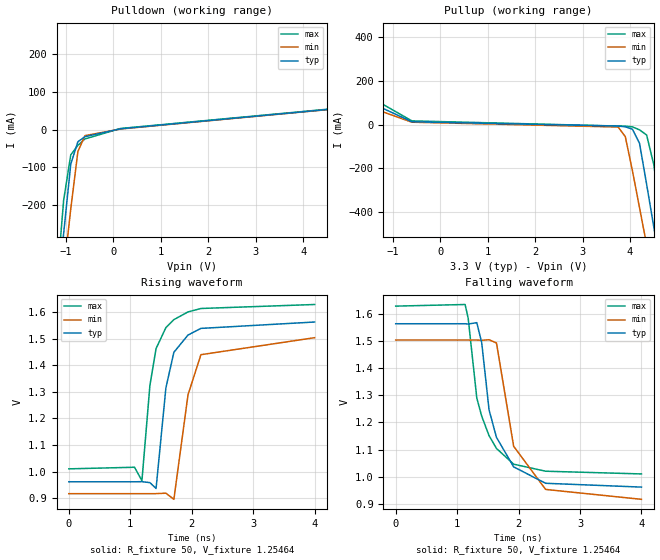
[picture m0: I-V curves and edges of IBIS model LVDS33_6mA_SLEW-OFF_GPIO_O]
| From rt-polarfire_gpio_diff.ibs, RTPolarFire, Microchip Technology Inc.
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|   Model LVDS33_6mA_SLEW-OFF_GPIO_O
[Model]   LVDS33_6mA_SLEW-OFF_GPIO_O
Model_type   Output
Polarity   Non-Inverting
Enable   Active-High
Vmeas =   1.2
Cref =   5p
Rref =   100
|   typ   min   max
C_comp_pullup   2.605e-12   2.605e-12   2.76e-12
C_comp_pulldown  2.605e-12   2.605e-12   2.76e-12
[Temperature Range]  25C   125C   -55C
[Voltage Range]  3.3   3.15   3.45
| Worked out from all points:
|   slope of the pulldown table from 0 to 0.495 V, typ, clamps not added: 91 ohm
|   slope of the pullup table from 0 to 0.495 V, typ, clamps not added: 102 ohm
|   rising waveform, R_fixture 50, V_fixture 1.25464: 20-80 % time 217ps typ, 238ps min, 232ps max; typ from 0.961 V to 1.56 V
|   falling waveform, R_fixture 50, V_fixture 1.25464: 20-80 % time 343ps typ, 341ps min, 346ps max; typ from 1.56 V to 0.961 V
[Pulldown]
|Voltage   I(typ)   I(min)   I(max)
-3.3V     -3.224A    -2.962A    -3.689A
-1.2V     -469.5mA   -550.8mA   -416.8mA
-1.05V    -275.6mA   -380.6mA   -187.3mA
-900mV    -91.45mA   -210.5mA   -66.79mA
-750mV    -31.79mA   -58.02mA   -41.54mA
-600mV    -18.41mA   -15.65mA   -24.42mA
150mV     2.545mA    1.949mA    3.354mA
4.5V      53.6mA     53.25mA    54.33mA
5.1V      120.5mA    109.3mA    127.7mA
6V        250.4mA    221.3mA    278.1mA
6.15V     274.9mA    242.6mA    305.6mA
6.6V      354.3mA    309.4mA    392.8mA
[Pullup]
|Voltage   I(typ)   I(min)   I(max)
-3.3V     376.5mA    307.5mA    447.5mA
-1.8V     133.6mA    104.2mA    166.2mA
-600mV    13.4mA     11.28mA    17.4mA
3.75V     -6.487mA   -10.85mA   -6.355mA
3.9V      -9.671mA   -54.64mA   -6.543mA
4.05V     -20.47mA   -210mA     -10.08mA
4.2V      -85.38mA   -379.9mA   -23.71mA
4.35V     -273.1mA   -549.9mA   -47.38mA
4.5V      -466.9mA   -719.7mA   -182.5mA
4.65V     -660.8mA   -889.7mA   -412mA
4.8V      -855mA     -1.06A     -641.6mA
6.6V      -3.219A    -3.132A    -3.444A
[Ramp]
| variable   typ   min   max
dV/dt_r 0.3794/0.2186e-9   0.3655/0.2404e-9   0.3986/0.2268e-9
dV/dt_f 0.3644/0.3414e-9   0.3549/0.3403e-9   0.3759/0.3446e-9
R_load = 50
[Rising waveform]
R_fixture= 50
V_fixture= 1.25464
V_fixture_min= 1.19616
V_fixture_max= 1.31676
|Time   V(typ)   V(min)   V(max)
0s        961.2mV    916.6mV    1.01V
1.07ns    961.2mV    916.6mV    1.016V
1.19ns    961.8mV    916.6mV    965.2mV
1.32ns    958.1mV    916.5mV    1.325V
1.42ns    936.1mV    916.7mV    1.463V
1.58ns    1.315V     918.3mV    1.542V
1.71ns    1.449V     895.2mV    1.572V
1.94ns    1.514V     1.289V     1.601V
2.15ns    1.539V     1.44V      1.614V
4ns       1.563V     1.504V     1.629V
[Falling waveform]
R_fixture= 50
V_fixture= 1.25464
V_fixture_min= 1.19616
V_fixture_max= 1.31676
|Time   V(typ)   V(min)   V(max)
0s        1.564V     1.504V     1.629V
1.13ns    1.564V     1.504V     1.635V
1.18ns    1.563V     1.504V     1.584V
1.32ns    1.568V     1.504V     1.29V
1.4ns     1.494V     1.503V     1.223V
1.52ns    1.246V     1.505V     1.151V
1.64ns    1.145V     1.493V     1.104V
1.92ns    1.036V     1.112V     1.046V
2.44ns    975.5mV    952.8mV    1.02V
4ns       961.4mV    916.3mV    1.01V
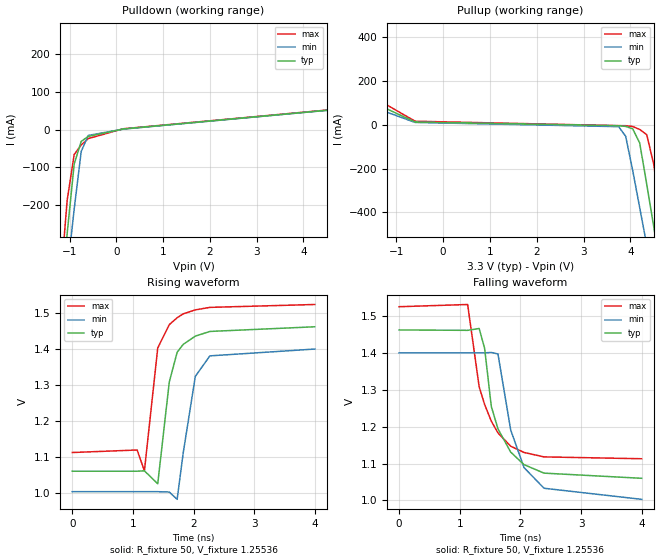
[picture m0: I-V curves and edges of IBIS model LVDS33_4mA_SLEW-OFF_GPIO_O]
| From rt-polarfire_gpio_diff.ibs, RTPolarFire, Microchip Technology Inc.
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|   Model LVDS33_4mA_SLEW-OFF_GPIO_O
[Model]   LVDS33_4mA_SLEW-OFF_GPIO_O
Model_type   Output
Polarity   Non-Inverting
Enable   Active-High
Vmeas =   1.2
Cref =   5p
Rref =   100
|   typ   min   max
C_comp_pullup   2.605e-12   2.605e-12   2.76e-12
C_comp_pulldown  2.605e-12   2.605e-12   2.76e-12
[Temperature Range]  25C   125C   -55C
[Voltage Range]  3.3   3.15   3.45
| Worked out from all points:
|   slope of the pulldown table from 0 to 0.495 V, typ, clamps not added: 137 ohm
|   slope of the pullup table from 0 to 0.495 V, typ, clamps not added: 138 ohm
|   rising waveform, R_fixture 50, V_fixture 1.25536: 20-80 % time 214ps typ, 213ps min, 229ps max; typ from 1.06 V to 1.46 V
|   falling waveform, R_fixture 50, V_fixture 1.25536: 20-80 % time 367ps typ, 352ps min, 364ps max; typ from 1.46 V to 1.06 V
[Pulldown]
|Voltage   I(typ)   I(min)   I(max)
-3.3V     -3.224A    -2.962A    -3.688A
-1.2V     -469.2mA   -550.5mA   -416.4mA
-1.05V    -275.2mA   -380.3mA   -186.9mA
-900mV    -90.84mA   -210.2mA   -65.68mA
-750mV    -30.98mA   -57.57mA   -40.48mA
-600mV    -17.67mA   -15.12mA   -23.45mA
150mV     2.057mA    1.632mA    2.625mA
4.5V      51.56mA    51.45mA    52.21mA
5.1V      118.4mA    107.5mA    125.6mA
6V        248.2mA    219.3mA    275.8mA
6.15V     272.7mA    240.6mA    303.2mA
6.6V      351.9mA    307.2mA    390.3mA
[Pullup]
|Voltage   I(typ)   I(min)   I(max)
-3.3V     375.9mA    307.3mA    445.8mA
-1.8V     131.5mA    103.2mA    163.5mA
-600mV    12.28mA    10.41mA    15.98mA
3.75V     -4.424mA   -8.823mA   -4.266mA
3.9V      -7.63mA    -52.76mA   -4.457mA
4.05V     -18.46mA   -208.2mA   -8.018mA
4.2V      -83.59mA   -378.1mA   -21.68mA
4.35V     -271.4mA   -548.1mA   -45.37mA
4.5V      -465.1mA   -717.9mA   -180.8mA
4.65V     -659.1mA   -887.9mA   -410.3mA
4.8V      -853.2mA   -1.058A    -639.9mA
6.6V      -3.217A    -3.13A     -3.442A
[Ramp]
| variable   typ   min   max
dV/dt_r 0.2623/0.2137e-9   0.2538/0.2185e-9   0.2782/0.2158e-9
dV/dt_f 0.2437/0.3650e-9   0.2408/0.3504e-9   0.2521/0.3622e-9
R_load = 50
[Rising waveform]
R_fixture= 50
V_fixture= 1.25536
V_fixture_min= 1.19490
V_fixture_max= 1.31638
|Time   V(typ)   V(min)   V(max)
0s        1.06V      1.003V     1.112V
1.07ns    1.06V      1.003V     1.119V
1.19ns    1.061V     1.003V     1.061V
1.41ns    1.025V     1.003V     1.403V
1.6ns     1.308V     1.002V     1.468V
1.73ns    1.391V     981.7mV    1.487V
1.83ns    1.413V     1.111V     1.498V
2.03ns    1.436V     1.324V     1.509V
2.27ns    1.449V     1.381V     1.516V
4ns       1.462V     1.4V       1.524V
[Falling waveform]
R_fixture= 50
V_fixture= 1.25536
V_fixture_min= 1.19490
V_fixture_max= 1.31638
|Time   V(typ)   V(min)   V(max)
0s        1.462V     1.4V       1.525V
1.13ns    1.461V     1.4V       1.531V
1.32ns    1.466V     1.4V       1.308V
1.41ns    1.412V     1.4V       1.26V
1.52ns    1.255V     1.401V     1.215V
1.63ns    1.194V     1.397V     1.183V
1.84ns    1.131V     1.191V     1.147V
2.06ns    1.097V     1.089V     1.13V
2.39ns    1.074V     1.033V     1.118V
4ns       1.06V      1.003V     1.113V
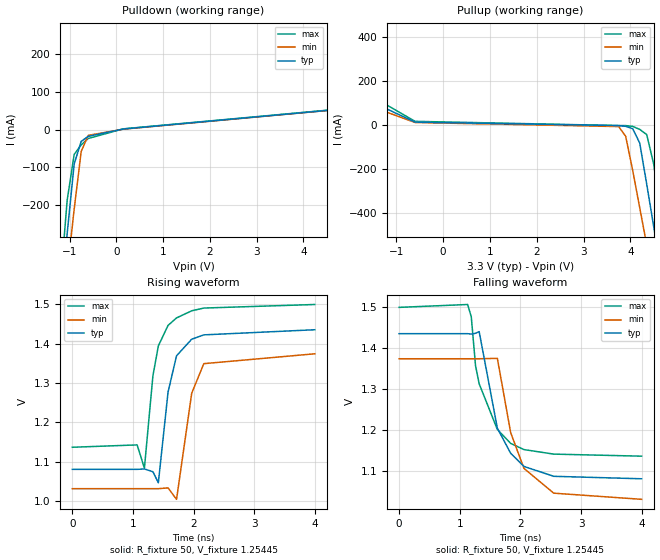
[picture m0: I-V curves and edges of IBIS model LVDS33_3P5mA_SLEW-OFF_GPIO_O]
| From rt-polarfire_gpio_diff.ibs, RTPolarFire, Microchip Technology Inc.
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|   Model LVDS33_3P5mA_SLEW-OFF_GPIO_O
[Model]   LVDS33_3P5mA_SLEW-OFF_GPIO_O
Model_type   Output
Polarity   Non-Inverting
Enable   Active-High
Vmeas =   1.2
Cref =   5p
Rref =   100
|   typ   min   max
C_comp_pullup   2.605e-12   2.605e-12   2.76e-12
C_comp_pulldown  2.605e-12   2.605e-12   2.76e-12
[Temperature Range]  25C   125C   -55C
[Voltage Range]  3.3   3.15   3.45
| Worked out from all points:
|   slope of the pulldown table from 0 to 0.495 V, typ, clamps not added: 154 ohm
|   slope of the pullup table from 0 to 0.495 V, typ, clamps not added: 154 ohm
|   rising waveform, R_fixture 50, V_fixture 1.25445: 20-80 % time 210ps typ, 211ps min, 227ps max; typ from 1.08 V to 1.44 V
|   falling waveform, R_fixture 50, V_fixture 1.25445: 20-80 % time 366ps typ, 358ps min, 375ps max; typ from 1.44 V to 1.08 V
[Pulldown]
|Voltage   I(typ)   I(min)   I(max)
-3.3V     -3.224A    -2.962A    -3.688A
-1.2V     -469.1mA   -550.4mA   -416.3mA
-1.05V    -275.1mA   -380.2mA   -186.7mA
-900mV    -90.69mA   -210.1mA   -65.38mA
-750mV    -30.77mA   -57.4mA    -40.19mA
-600mV    -17.48mA   -14.92mA   -23.17mA
150mV     1.916mA    1.491mA    2.401mA
4.5V      51.12mA    50.84mA    51.7mA
5.1V      118mA      106.9mA    125.1mA
6V        247.7mA    218.7mA    275.2mA
6.15V     272.2mA    239.9mA    302.6mA
6.6V      351.3mA    306.5mA    389.6mA
[Pullup]
|Voltage   I(typ)   I(min)   I(max)
-3.3V     375.8mA    307.2mA    445.5mA
-1.8V     130.9mA    103mA      162.8mA
-600mV    11.9mA     10.12mA    15.49mA
3.75V     -3.915mA   -8.323mA   -3.752mA
3.9V      -7.126mA   -52.3mA    -3.944mA
4.05V     -17.97mA   -207.8mA   -7.511mA
4.2V      -83.15mA   -377.7mA   -21.18mA
4.35V     -271mA     -547.6mA   -44.88mA
4.5V      -464.7mA   -717.5mA   -180.4mA
4.65V     -658.6mA   -887.5mA   -409.9mA
4.8V      -852.8mA   -1.058A    -639.5mA
6.6V      -3.216A    -3.13A     -3.442A
[Ramp]
| variable   typ   min   max
dV/dt_r 0.2351/0.2070e-9   0.2218/0.2171e-9   0.2493/0.2113e-9
dV/dt_f 0.2152/0.3633e-9   0.2079/0.3570e-9   0.2220/0.3715e-9
R_load = 50
[Rising waveform]
R_fixture= 50
V_fixture= 1.25445
V_fixture_min= 1.19435
V_fixture_max= 1.31632
|Time   V(typ)   V(min)   V(max)
0s        1.081V     1.032V     1.137V
1.07ns    1.081V     1.032V     1.143V
1.19ns    1.082V     1.032V     1.084V
1.33ns    1.075V     1.032V     1.318V
1.42ns    1.047V     1.032V     1.394V
1.58ns    1.277V     1.034V     1.446V
1.72ns    1.369V     1.005V     1.465V
1.97ns    1.411V     1.274V     1.483V
2.17ns    1.422V     1.349V     1.49V
4ns       1.435V     1.374V     1.499V
[Falling waveform]
R_fixture= 50
V_fixture= 1.25445
V_fixture_min= 1.19435
V_fixture_max= 1.31632
|Time   V(typ)   V(min)   V(max)
0s        1.435V     1.374V     1.499V
1.13ns    1.435V     1.374V     1.506V
1.19ns    1.434V     1.374V     1.476V
1.26ns    1.436V     1.374V     1.357V
1.32ns    1.44V      1.374V     1.313V
1.62ns    1.205V     1.375V     1.202V
1.84ns    1.144V     1.194V     1.168V
2.06ns    1.112V     1.107V     1.153V
2.55ns    1.088V     1.047V     1.142V
4ns       1.082V     1.032V     1.137V
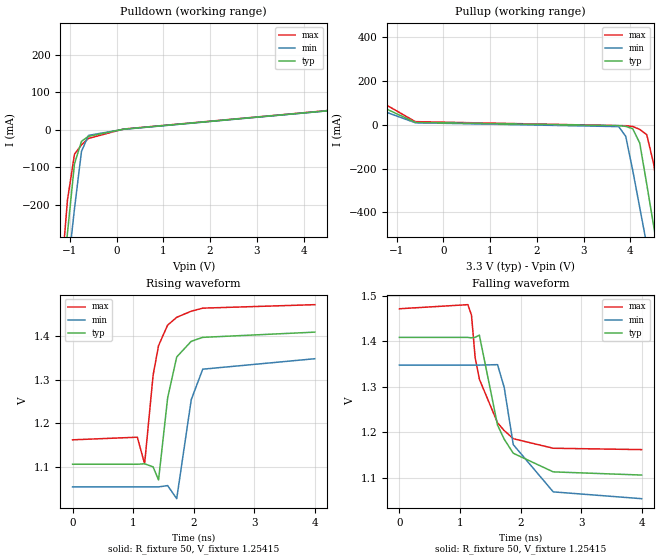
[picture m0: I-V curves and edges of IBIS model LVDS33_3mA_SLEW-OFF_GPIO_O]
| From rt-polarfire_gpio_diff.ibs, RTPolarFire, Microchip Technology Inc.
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|   Model LVDS33_3mA_SLEW-OFF_GPIO_O
[Model]   LVDS33_3mA_SLEW-OFF_GPIO_O
Model_type   Output
Polarity   Non-Inverting
Enable   Active-High
Vmeas =   1.2
Cref =   5p
Rref =   100
|   typ   min   max
C_comp_pullup   2.605e-12   2.605e-12   2.76e-12
C_comp_pulldown  2.605e-12   2.605e-12   2.76e-12
[Temperature Range]  25C   125C   -55C
[Voltage Range]  3.3   3.15   3.45
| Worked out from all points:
|   slope of the pulldown table from 0 to 0.495 V, typ, clamps not added: 181 ohm
|   slope of the pullup table from 0 to 0.495 V, typ, clamps not added: 176 ohm
|   rising waveform, R_fixture 50, V_fixture 1.25415: 20-80 % time 203ps typ, 206ps min, 227ps max; typ from 1.11 V to 1.41 V
|   falling waveform, R_fixture 50, V_fixture 1.25415: 20-80 % time 376ps typ, 366ps min, 386ps max; typ from 1.41 V to 1.11 V
[Pulldown]
|Voltage   I(typ)   I(min)   I(max)
-3.3V     -3.224A    -2.962A    -3.688A
-1.2V     -469mA     -550.4mA   -416.2mA
-1.05V    -275mA     -380.1mA   -186.6mA
-900mV    -90.51mA   -210mA     -65.03mA
-750mV    -30.52mA   -57.26mA   -39.85mA
-600mV    -17.24mA   -14.75mA   -22.86mA
150mV     1.734mA    1.364mA    2.137mA
4.5V      50.6mA     50.37mA    51.17mA
5.1V      117.5mA    106.4mA    124.6mA
6V        247.1mA    218.1mA    274.7mA
6.15V     271.6mA    239.3mA    302mA
6.6V      350.7mA    305.9mA    389mA
[Pullup]
|Voltage   I(typ)   I(min)   I(max)
-3.3V     375.6mA    307.1mA    445.3mA
-1.8V     130.3mA    102.8mA    162.1mA
-600mV    11.44mA    9.762mA    14.9mA
3.75V     -3.395mA   -7.812mA   -3.224mA
3.9V      -6.611mA   -51.82mA   -3.417mA
4.05V     -17.46mA   -207.3mA   -6.99mA
4.2V      -82.7mA    -377.2mA   -20.67mA
4.35V     -270.5mA   -547.2mA   -44.38mA
4.5V      -464.3mA   -717mA     -179.9mA
4.65V     -658.2mA   -887.1mA   -409.4mA
4.8V      -852.4mA   -1.057A    -639mA
6.6V      -3.216A    -3.129A    -3.441A
[Ramp]
| variable   typ   min   max
dV/dt_r 0.2049/0.2069e-9   0.1931/0.2142e-9   0.2187/0.2087e-9
dV/dt_f 0.1847/0.3732e-9   0.1787/0.3651e-9   0.1918/0.3808e-9
R_load = 50
[Rising waveform]
R_fixture= 50
V_fixture= 1.25415
V_fixture_min= 1.19418
V_fixture_max= 1.31585
|Time   V(typ)   V(min)   V(max)
0s        1.106V     1.054V     1.162V
1.07ns    1.106V     1.054V     1.168V
1.19ns    1.107V     1.054V     1.107V
1.33ns    1.1V       1.054V     1.31V
1.42ns    1.07V      1.054V     1.378V
1.57ns    1.258V     1.057V     1.425V
1.72ns    1.352V     1.027V     1.443V
1.96ns    1.388V     1.254V     1.457V
2.15ns    1.397V     1.324V     1.464V
4ns       1.409V     1.348V     1.472V
[Falling waveform]
R_fixture= 50
V_fixture= 1.25415
V_fixture_min= 1.19418
V_fixture_max= 1.31585
|Time   V(typ)   V(min)   V(max)
0s        1.409V     1.348V     1.472V
1.13ns    1.409V     1.348V     1.481V
1.19ns    1.408V     1.348V     1.458V
1.25ns    1.409V     1.348V     1.365V
1.32ns    1.414V     1.348V     1.317V
1.62ns    1.216V     1.349V     1.221V
1.73ns    1.185V     1.299V     1.204V
1.88ns    1.154V     1.173V     1.186V
2.54ns    1.113V     1.069V     1.165V
4ns       1.106V     1.054V     1.162V
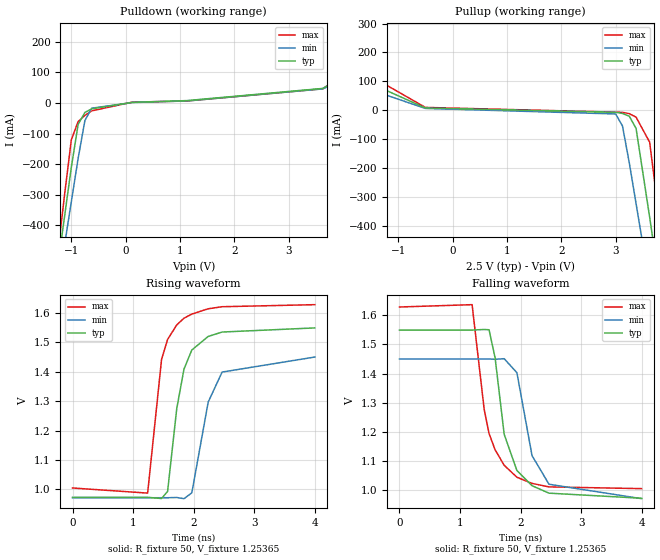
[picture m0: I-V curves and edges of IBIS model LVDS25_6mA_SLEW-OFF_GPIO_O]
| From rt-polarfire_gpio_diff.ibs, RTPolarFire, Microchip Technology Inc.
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|   Model LVDS25_6mA_SLEW-OFF_GPIO_O
[Model]   LVDS25_6mA_SLEW-OFF_GPIO_O
Model_type   Output
Polarity   Non-Inverting
Enable   Active-High
Vmeas =   1.2
Cref =   5p
Rref =   100
|   typ   min   max
C_comp_pullup   2.605e-12   2.605e-12   2.76e-12
C_comp_pulldown  2.605e-12   2.605e-12   2.76e-12
[Temperature Range]  25C   125C   -55C
[Voltage Range]  2.5   2.375   2.625
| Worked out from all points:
|   slope of the pulldown table from 0 to 0.375 V, typ, clamps not added: 79.1 ohm
|   slope of the pullup table from 0 to 0.375 V, typ, clamps not added: 103 ohm
|   rising waveform, R_fixture 50, V_fixture 1.25365: 20-80 % time 246ps typ, 296ps min, 239ps max; typ from 0.973 V to 1.55 V
|   falling waveform, R_fixture 50, V_fixture 1.25365: 20-80 % time 293ps typ, 294ps min, 302ps max; typ from 1.55 V to 0.973 V
[Pulldown]
|Voltage   I(typ)   I(min)   I(max)
-2.5V     -2.164A    -2.035A    -2.425A
-1.25V    -533.8mA   -607mA     -493mA
-1.125V   -372.1mA   -465.2mA   -301.5mA
-1V       -210.6mA   -323.3mA   -120.6mA
-875mV    -70.3mA    -181.7mA   -60.99mA
-750mV    -30.89mA   -57.23mA   -40.67mA
-625mV    -19.32mA   -17.05mA   -25.85mA
125mV     2.003mA    1.397mA    2.795mA
1.125V    7.725mA    6.579mA    6.369mA
3.625V    47.6mA     46.02mA    46.43mA
4.25V     111.7mA    97.85mA    122.6mA
5V        215.8mA    185.5mA    244.4mA
[Pullup]
|Voltage   I(typ)   I(min)   I(max)
-2.5V     231mA      182.9mA    284.8mA
-1.5V     92.37mA    70.56mA    117.7mA
-500mV    8.223mA    6.452mA    10.05mA
3V        -6.914mA   -12.63mA   -6.367mA
3.125V    -10.83mA   -54.39mA   -6.994mA
3.25V     -20.45mA   -181.5mA   -11.53mA
3.375V    -62.83mA   -323mA     -23.69mA
3.625V    -370mA     -606.3mA   -110.5mA
3.75V     -531.5mA   -747.8mA   -297.3mA
3.875V    -693.1mA   -889.5mA   -488.6mA
4V        -855mA     -1.031A    -679.9mA
5V        -2.159A    -2.177A    -2.222A
[Ramp]
| variable   typ   min   max
dV/dt_r 0.3510/0.2469e-9   0.2898/0.2956e-9   0.3843/0.2379e-9
dV/dt_f 0.3489/0.2929e-9   0.2898/0.2949e-9   0.3790/0.3006e-9
R_load = 50
[Rising waveform]
R_fixture= 50
V_fixture= 1.25365
V_fixture_min= 1.19649
V_fixture_max= 1.31735
|Time   V(typ)   V(min)   V(max)
0s        973.3mV    971.9mV    1.005V
1.24ns    973.3mV    971.9mV    987.7mV
1.47ns    969.3mV    971.9mV    1.442V
1.57ns    993.7mV    971.9mV    1.51V
1.72ns    1.274V     972.8mV    1.559V
1.84ns    1.409V     968.7mV    1.582V
1.97ns    1.474V     988.8mV    1.596V
2.24ns    1.52V      1.297V     1.614V
2.47ns    1.535V     1.399V     1.621V
4ns       1.549V     1.45V      1.628V
[Falling waveform]
R_fixture= 50
V_fixture= 1.25365
V_fixture_min= 1.19649
V_fixture_max= 1.31735
|Time   V(typ)   V(min)   V(max)
0s        1.549V     1.45V      1.628V
1.2ns     1.549V     1.45V      1.636V
1.4ns     1.551V     1.45V      1.277V
1.48ns    1.55V      1.45V      1.195V
1.58ns    1.454V     1.449V     1.139V
1.73ns    1.192V     1.451V     1.086V
1.94ns    1.068V     1.403V     1.045V
2.19ns    1.016V     1.119V     1.024V
2.47ns    990.5mV    1.021V     1.012V
4ns       973.1mV    971.6mV    1.006V
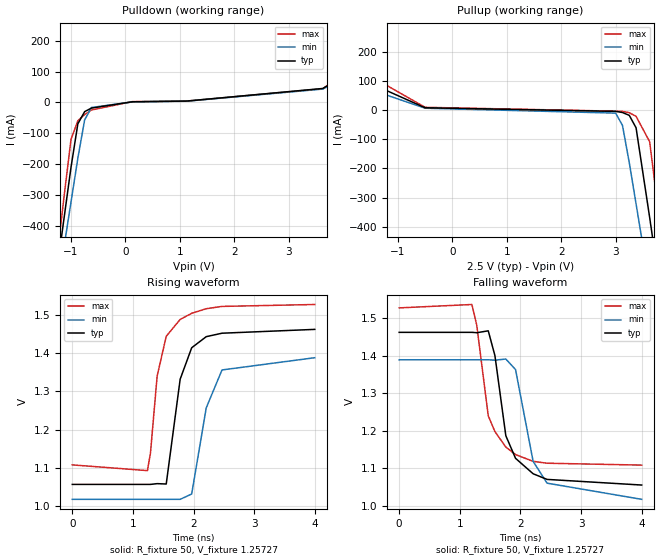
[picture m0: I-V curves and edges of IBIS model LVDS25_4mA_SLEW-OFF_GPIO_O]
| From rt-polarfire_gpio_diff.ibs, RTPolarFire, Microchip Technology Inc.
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|   Model LVDS25_4mA_SLEW-OFF_GPIO_O
[Model]   LVDS25_4mA_SLEW-OFF_GPIO_O
Model_type   Output
Polarity   Non-Inverting
Enable   Active-High
Vmeas =   1.2
Cref =   5p
Rref =   100
|   typ   min   max
C_comp_pullup   2.605e-12   2.605e-12   2.76e-12
C_comp_pulldown  2.605e-12   2.605e-12   2.76e-12
[Temperature Range]  25C   125C   -55C
[Voltage Range]  2.5   2.375   2.625
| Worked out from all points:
|   slope of the pulldown table from 0 to 0.375 V, typ, clamps not added: 105 ohm
|   slope of the pullup table from 0 to 0.375 V, typ, clamps not added: 129 ohm
|   rising waveform, R_fixture 50, V_fixture 1.25727: 20-80 % time 229ps typ, 269ps min, 230ps max; typ from 1.06 V to 1.46 V
|   falling waveform, R_fixture 50, V_fixture 1.25727: 20-80 % time 285ps typ, 299ps min, 295ps max; typ from 1.46 V to 1.06 V
[Pulldown]
|Voltage   I(typ)   I(min)   I(max)
-2.5V     -2.163A    -2.035A    -2.424A
-1.25V    -533.5mA   -606.9mA   -492.7mA
-1.125V   -371.8mA   -465.1mA   -301.1mA
-1V       -210.3mA   -323.2mA   -119.8mA
-875mV    -69.77mA   -181.5mA   -59.99mA
-750mV    -30.27mA   -56.99mA   -39.71mA
-625mV    -18.74mA   -16.77mA   -24.95mA
125mV     1.712mA    1.256mA    2.274mA
1.125V    4.045mA    3.602mA    4.215mA
3.625V    44.96mA    43.06mA    44.34mA
4.25V     110mA      96.86mA    120.4mA
5V        214mA      184.5mA    242.1mA
[Pullup]
|Voltage   I(typ)   I(min)   I(max)
-2.5V     229.4mA    182.5mA    282.3mA
-1.5V     90.6mA     69.32mA    115.4mA
-500mV    7.398mA    5.901mA    8.984mA
3V        -4.874mA   -10.84mA   -4.281mA
3.125V    -8.808mA   -52.72mA   -4.916mA
3.25V     -18.45mA   -179.9mA   -9.476mA
3.375V    -60.99mA   -321.4mA   -21.67mA
3.625V    -368.2mA   -604.7mA   -108.8mA
3.75V     -529.7mA   -746.2mA   -295.5mA
3.875V    -691.4mA   -887.9mA   -486.8mA
4V        -853.2mA   -1.03A     -678.2mA
5V        -2.158A    -2.175A    -2.221A
[Ramp]
| variable   typ   min   max
dV/dt_r 0.2476/0.2305e-9   0.2254/0.2707e-9   0.2606/0.2267e-9
dV/dt_f 0.2468/0.2839e-9   0.2248/0.3002e-9   0.2572/0.2923e-9
R_load = 50
[Rising waveform]
R_fixture= 50
V_fixture= 1.25727
V_fixture_min= 1.19545
V_fixture_max= 1.31876
|Time   V(typ)   V(min)   V(max)
0s        1.057V     1.018V     1.108V
1.24ns    1.057V     1.018V     1.093V
1.29ns    1.057V     1.018V     1.139V
1.4ns     1.059V     1.018V     1.34V
1.55ns    1.058V     1.018V     1.444V
1.78ns    1.332V     1.018V     1.488V
1.97ns    1.414V     1.032V     1.504V
2.21ns    1.443V     1.257V     1.516V
2.47ns    1.452V     1.356V     1.522V
4ns       1.462V     1.388V     1.527V
[Falling waveform]
R_fixture= 50
V_fixture= 1.25727
V_fixture_min= 1.19545
V_fixture_max= 1.31876
|Time   V(typ)   V(min)   V(max)
0s        1.462V     1.389V     1.527V
1.2ns     1.462V     1.389V     1.536V
1.28ns    1.461V     1.389V     1.481V
1.47ns    1.466V     1.389V     1.24V
1.58ns    1.4V       1.388V     1.198V
1.76ns    1.187V     1.391V     1.157V
1.92ns    1.127V     1.363V     1.137V
2.21ns    1.086V     1.119V     1.119V
2.44ns    1.071V     1.061V     1.114V
4ns       1.056V     1.018V     1.109V
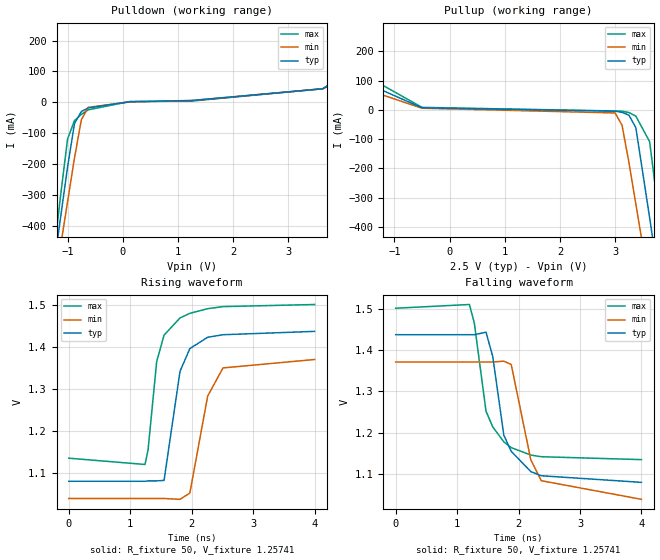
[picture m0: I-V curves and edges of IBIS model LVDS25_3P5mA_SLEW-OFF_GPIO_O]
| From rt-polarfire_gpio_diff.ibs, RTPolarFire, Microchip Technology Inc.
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|   Model LVDS25_3P5mA_SLEW-OFF_GPIO_O
[Model]   LVDS25_3P5mA_SLEW-OFF_GPIO_O
Model_type   Output
Polarity   Non-Inverting
Enable   Active-High
Vmeas =   1.2
Cref =   5p
Rref =   100
|   typ   min   max
C_comp_pullup   2.605e-12   2.605e-12   2.76e-12
C_comp_pulldown  2.605e-12   2.605e-12   2.76e-12
[Temperature Range]  25C   125C   -55C
[Voltage Range]  2.5   2.375   2.625
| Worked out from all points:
|   slope of the pulldown table from 0 to 0.375 V, typ, clamps not added: 118 ohm
|   slope of the pullup table from 0 to 0.375 V, typ, clamps not added: 141 ohm
|   rising waveform, R_fixture 50, V_fixture 1.25741: 20-80 % time 230ps typ, 264ps min, 227ps max; typ from 1.08 V to 1.44 V
|   falling waveform, R_fixture 50, V_fixture 1.25741: 20-80 % time 293ps typ, 278ps min, 293ps max; typ from 1.44 V to 1.08 V
[Pulldown]
|Voltage   I(typ)   I(min)   I(max)
-2.5V     -2.163A    -2.035A    -2.424A
-1.25V    -533.5mA   -606.8mA   -492.6mA
-1.125V   -371.7mA   -465mA     -301mA
-1V       -210.2mA   -323.1mA   -119.6mA
-875mV    -69.6mA    -181.5mA   -59.67mA
-750mV    -30.07mA   -56.89mA   -39.41mA
-625mV    -18.56mA   -16.65mA   -24.67mA
125mV     1.606mA    1.189mA    2.093mA
1.25V     5.644mA    5.273mA    3.76mA
3.625V    43.49mA    43.68mA    43.78mA
4.25V     109.6mA    96.47mA    119.9mA
5V        213.5mA    184mA      241.5mA
[Pullup]
|Voltage   I(typ)   I(min)   I(max)
-2.5V     229.1mA    182.4mA    281.7mA
-1.5V     90.1mA     69.01mA    114.7mA
-500mV    7.112mA    5.707mA    8.615mA
3V        -4.368mA   -10.36mA   -3.767mA
3.125V    -8.306mA   -52.28mA   -4.405mA
3.25V     -17.96mA   -179.5mA   -8.971mA
3.375V    -60.54mA   -321mA     -21.17mA
3.625V    -367.8mA   -604.2mA   -108.3mA
3.75V     -529.3mA   -745.8mA   -295.1mA
3.875V    -691mA     -887.5mA   -486.4mA
4V        -852.8mA   -1.029A    -677.7mA
5V        -2.157A    -2.175A    -2.22A
[Ramp]
| variable   typ   min   max
dV/dt_r 0.2195/0.2297e-9   0.2021/0.2664e-9   0.2292/0.2263e-9
dV/dt_f 0.2180/0.2930e-9   0.2017/0.2807e-9   0.2255/0.2891e-9
R_load = 50
[Rising waveform]
R_fixture= 50
V_fixture= 1.25741
V_fixture_min= 1.19791
V_fixture_max= 1.31823
|Time   V(typ)   V(min)   V(max)
0s        1.08V      1.039V     1.135V
1.24ns    1.08V      1.039V     1.12V
1.29ns    1.081V     1.039V     1.155V
1.43ns    1.081V     1.039V     1.365V
1.55ns    1.082V     1.039V     1.428V
1.81ns    1.342V     1.037V     1.469V
1.97ns    1.396V     1.052V     1.48V
2.26ns    1.423V     1.283V     1.491V
2.51ns    1.429V     1.35V      1.496V
4ns       1.437V     1.37V      1.501V
[Falling waveform]
R_fixture= 50
V_fixture= 1.25741
V_fixture_min= 1.19791
V_fixture_max= 1.31823
|Time   V(typ)   V(min)   V(max)
0s        1.437V     1.371V     1.501V
1.2ns     1.437V     1.371V     1.51V
1.28ns    1.437V     1.371V     1.465V
1.47ns    1.443V     1.371V     1.252V
1.58ns    1.384V     1.371V     1.214V
1.76ns    1.194V     1.373V     1.178V
1.88ns    1.155V     1.365V     1.164V
2.2ns     1.106V     1.134V     1.146V
2.37ns    1.096V     1.084V     1.142V
4ns       1.08V      1.039V     1.135V
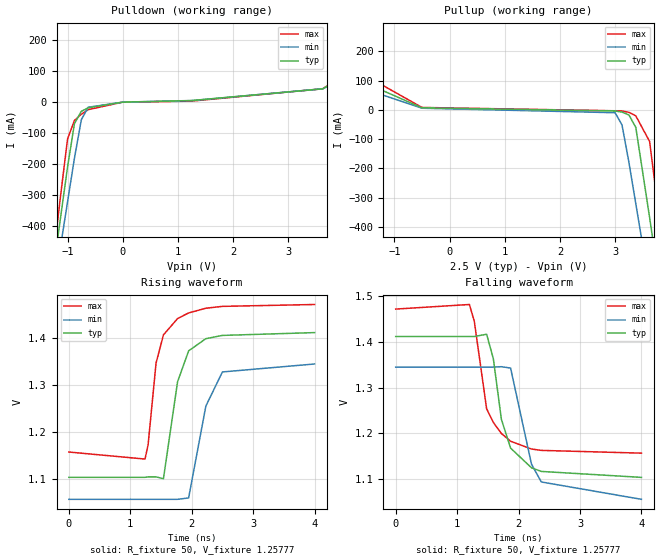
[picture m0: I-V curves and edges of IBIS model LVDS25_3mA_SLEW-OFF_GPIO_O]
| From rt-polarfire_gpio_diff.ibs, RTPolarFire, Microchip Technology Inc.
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|   Model LVDS25_3mA_SLEW-OFF_GPIO_O
[Model]   LVDS25_3mA_SLEW-OFF_GPIO_O
Model_type   Output
Polarity   Non-Inverting
Enable   Active-High
Vmeas =   1.2
Cref =   5p
Rref =   100
|   typ   min   max
C_comp_pullup   2.605e-12   2.605e-12   2.76e-12
C_comp_pulldown  2.605e-12   2.605e-12   2.76e-12
[Temperature Range]  25C   125C   -55C
[Voltage Range]  2.5   2.375   2.625
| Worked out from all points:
|   slope of the pulldown table from 0 to 0.375 V, typ, clamps not added: 135 ohm
|   slope of the pullup table from 0 to 0.375 V, typ, clamps not added: 158 ohm
|   rising waveform, R_fixture 50, V_fixture 1.25777: 20-80 % time 221ps typ, 252ps min, 225ps max; typ from 1.1 V to 1.41 V
|   falling waveform, R_fixture 50, V_fixture 1.25777: 20-80 % time 278ps typ, 273ps min, 293ps max; typ from 1.41 V to 1.1 V
[Pulldown]
|Voltage   I(typ)   I(min)   I(max)
-2.5V     -2.163A    -2.035A    -2.424A
-1.25V    -533.4mA   -606.7mA   -492.5mA
-1.125V   -371.6mA   -464.9mA   -300.9mA
-1V       -210.1mA   -323.1mA   -119.4mA
-875mV    -69.42mA   -181.4mA   -59.37mA
-750mV    -29.85mA   -56.78mA   -39.11mA
-625mV    -18.36mA   -16.51mA   -24.39mA
0V        -62.81uA   -53.34uA   -77.3uA
1.25V     5.17mA     4.865mA    3.241mA
3.625V    43.03mA    43.28mA    43.28mA
4.25V     109.1mA    96.06mA    119.4mA
5V        213mA      183.6mA    241mA
[Pullup]
|Voltage   I(typ)   I(min)   I(max)
-2.5V     228.9mA    182.4mA    281mA
-1.5V     89.55mA    68.71mA    114mA
-500mV    6.764mA    5.471mA    8.163mA
3V        -3.849mA   -9.862mA   -3.24mA
3.125V    -7.793mA   -51.81mA   -3.879mA
3.25V     -17.45mA   -179.1mA   -8.452mA
3.375V    -60.07mA   -320.6mA   -20.66mA
3.625V    -367.4mA   -603.8mA   -107.9mA
3.75V     -528.9mA   -745.3mA   -294.7mA
3.875V    -690.6mA   -887mA     -486mA
4V        -852.4mA   -1.029A    -677.3mA
5V        -2.157A    -2.174A    -2.22A
[Ramp]
| variable   typ   min   max
dV/dt_r 0.1904/0.2241e-9   0.1770/0.2550e-9   0.1987/0.2228e-9
dV/dt_f 0.1888/0.2766e-9   0.1763/0.2755e-9   0.1952/0.2896e-9
R_load = 50
[Rising waveform]
R_fixture= 50
V_fixture= 1.25777
V_fixture_min= 1.19496
V_fixture_max= 1.31587
|Time   V(typ)   V(min)   V(max)
0s        1.103V     1.056V     1.157V
1.24ns    1.103V     1.056V     1.142V
1.29ns    1.104V     1.056V     1.172V
1.42ns    1.104V     1.056V     1.347V
1.54ns    1.1V       1.056V     1.407V
1.77ns    1.307V     1.056V     1.442V
1.95ns    1.373V     1.059V     1.454V
2.23ns    1.399V     1.255V     1.464V
2.5ns     1.406V     1.328V     1.468V
4ns       1.412V     1.345V     1.472V
[Falling waveform]
R_fixture= 50
V_fixture= 1.25777
V_fixture_min= 1.19496
V_fixture_max= 1.31587
|Time   V(typ)   V(min)   V(max)
0s        1.412V     1.345V     1.472V
1.2ns     1.412V     1.345V     1.482V
1.28ns    1.412V     1.345V     1.445V
1.48ns    1.417V     1.345V     1.254V
1.59ns    1.363V     1.345V     1.224V
1.72ns    1.231V     1.346V     1.2V
1.87ns    1.168V     1.343V     1.183V
2.21ns    1.125V     1.133V     1.166V
2.37ns    1.117V     1.094V     1.163V
4ns       1.104V     1.056V     1.157V
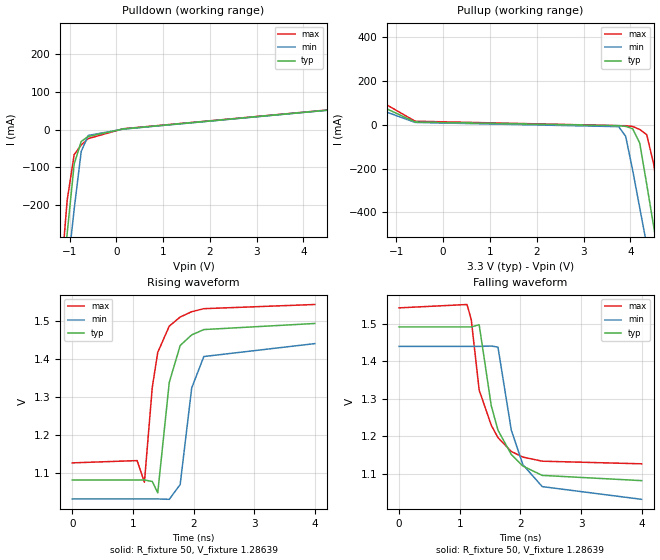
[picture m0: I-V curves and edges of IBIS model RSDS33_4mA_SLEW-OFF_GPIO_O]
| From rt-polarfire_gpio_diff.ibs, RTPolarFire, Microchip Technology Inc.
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|   Model RSDS33_4mA_SLEW-OFF_GPIO_O
[Model]   RSDS33_4mA_SLEW-OFF_GPIO_O
Model_type   Output
Polarity   Non-Inverting
Enable   Active-High
Vmeas =   1.2
Cref =   5p
Rref =   100
|   typ   min   max
C_comp_pullup   2.605e-12   2.605e-12   2.76e-12
C_comp_pulldown  2.605e-12   2.605e-12   2.76e-12
[Temperature Range]  25C   125C   -55C
[Voltage Range]  3.3   3.15   3.45
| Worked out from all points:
|   slope of the pulldown table from 0 to 0.495 V, typ, clamps not added: 131 ohm
|   slope of the pullup table from 0 to 0.495 V, typ, clamps not added: 138 ohm
|   rising waveform, R_fixture 50, V_fixture 1.28639: 20-80 % time 217ps typ, 219ps min, 227ps max; typ from 1.08 V to 1.49 V
|   falling waveform, R_fixture 50, V_fixture 1.28639: 20-80 % time 361ps typ, 347ps min, 369ps max; typ from 1.49 V to 1.08 V
[Pulldown]
|Voltage   I(typ)   I(min)   I(max)
-3.3V     -3.224A    -2.962A    -3.688A
-1.2V     -469.2mA   -550.6mA   -416.4mA
-1.05V    -275.2mA   -380.3mA   -186.9mA
-900mV    -90.9mA    -210.2mA   -65.72mA
-750mV    -31.06mA   -57.62mA   -40.52mA
-600mV    -17.74mA   -15.19mA   -23.48mA
150mV     2.109mA    1.673mA    2.65mA
4.5V      51.75mA    51.65mA    52.27mA
5.1V      118.6mA    107.7mA    125.7mA
6V        248.4mA    219.5mA    275.9mA
6.15V     272.9mA    240.8mA    303.3mA
6.6V      352.1mA    307.4mA    390.3mA
[Pullup]
|Voltage   I(typ)   I(min)   I(max)
-3.3V     375.8mA    307.2mA    445.7mA
-1.8V     131.4mA    103.2mA    163.5mA
-600mV    12.28mA    10.41mA    15.97mA
3.75V     -4.425mA   -8.826mA   -4.267mA
3.9V      -7.632mA   -52.76mA   -4.458mA
4.05V     -18.47mA   -208.2mA   -8.02mA
4.2V      -83.6mA    -378.1mA   -21.69mA
4.35V     -271.4mA   -548.1mA   -45.38mA
4.5V      -465.1mA   -717.9mA   -180.8mA
4.65V     -659.1mA   -887.9mA   -410.3mA
4.8V      -853.2mA   -1.058A    -639.9mA
6.6V      -3.217A    -3.13A     -3.442A
[Ramp]
| variable   typ   min   max
dV/dt_r 0.2683/0.2154e-9   0.2601/0.2231e-9   0.2810/0.2141e-9
dV/dt_f 0.2502/0.3593e-9   0.2478/0.3459e-9   0.2555/0.3655e-9
R_load = 50
[Rising waveform]
R_fixture= 50
V_fixture= 1.28639
V_fixture_min= 1.23495
V_fixture_max= 1.33430
|Time   V(typ)   V(min)   V(max)
0s        1.081V     1.031V     1.126V
1.07ns    1.081V     1.031V     1.132V
1.19ns    1.081V     1.031V     1.075V
1.32ns    1.077V     1.031V     1.325V
1.41ns    1.047V     1.031V     1.417V
1.6ns     1.338V     1.03V      1.486V
1.78ns    1.435V     1.069V     1.51V
1.97ns    1.463V     1.323V     1.524V
2.17ns    1.477V     1.406V     1.532V
4ns       1.493V     1.44V      1.543V
[Falling waveform]
R_fixture= 50
V_fixture= 1.28639
V_fixture_min= 1.23495
V_fixture_max= 1.33430
|Time   V(typ)   V(min)   V(max)
0s        1.492V     1.44V      1.543V
1.12ns    1.492V     1.44V      1.552V
1.19ns    1.492V     1.44V      1.511V
1.32ns    1.498V     1.44V      1.323V
1.52ns    1.281V     1.441V     1.229V
1.63ns    1.216V     1.438V     1.196V
1.85ns    1.151V     1.216V     1.159V
2.04ns    1.12V      1.124V     1.144V
2.36ns    1.095V     1.065V     1.133V
4ns       1.081V     1.031V     1.126V
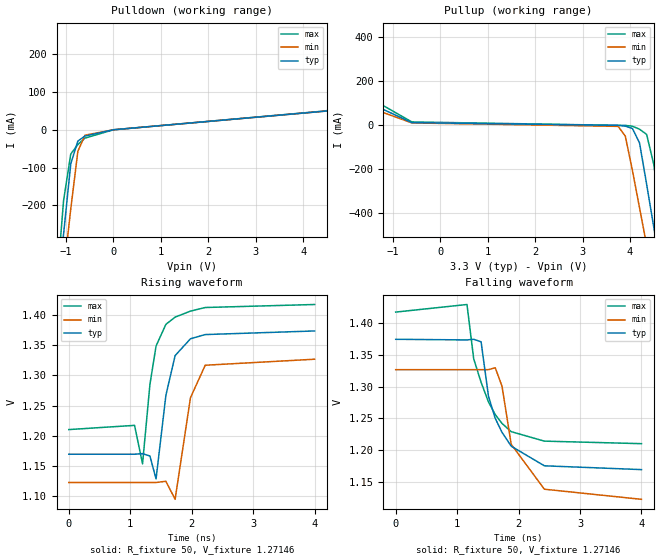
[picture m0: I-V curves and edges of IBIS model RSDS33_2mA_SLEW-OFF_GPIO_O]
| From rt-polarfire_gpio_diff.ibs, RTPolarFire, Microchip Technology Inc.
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|   Model RSDS33_2mA_SLEW-OFF_GPIO_O
[Model]   RSDS33_2mA_SLEW-OFF_GPIO_O
Model_type   Output
Polarity   Non-Inverting
Enable   Active-High
Vmeas =   1.2
Cref =   5p
Rref =   100
|   typ   min   max
C_comp_pullup   2.605e-12   2.605e-12   2.76e-12
C_comp_pulldown  2.605e-12   2.605e-12   2.76e-12
[Temperature Range]  25C   125C   -55C
[Voltage Range]  3.3   3.15   3.45
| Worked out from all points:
|   slope of the pulldown table from 0 to 0.495 V, typ, clamps not added: 267 ohm
|   slope of the pullup table from 0 to 0.495 V, typ, clamps not added: 256 ohm
|   rising waveform, R_fixture 50, V_fixture 1.27146: 20-80 % time 212ps typ, 208ps min, 240ps max; typ from 1.17 V to 1.37 V
|   falling waveform, R_fixture 50, V_fixture 1.27146: 20-80 % time 395ps typ, 381ps min, 417ps max; typ from 1.37 V to 1.17 V
[Pulldown]
|Voltage   I(typ)   I(min)   I(max)
-3.3V     -3.224A    -2.962A    -3.688A
-1.2V     -468.8mA   -550.2mA   -415.9mA
-1.05V    -274.8mA   -380mA     -186.3mA
-900mV    -90.14mA   -209.9mA   -64.27mA
-750mV    -30.01mA   -57.01mA   -39.12mA
-600mV    -16.77mA   -14.45mA   -22.17mA
0V        -62.59uA   -54.71uA   -75.48uA
4.5V      49.65mA    49.58mA    50.15mA
5.1V      116.5mA    105.6mA    123.6mA
6V        246mA      217.2mA    273.5mA
6.15V     270.4mA    238.4mA    300.8mA
6.6V      349.5mA    304.9mA    387.7mA
[Pullup]
|Voltage   I(typ)   I(min)   I(max)
-3.3V     375.4mA    307mA      445mA
-1.8V     129.3mA    102.6mA    160.7mA
-600mV    10.23mA    8.856mA    13.36mA
3.75V     -2.36mA    -6.798mA   -2.175mA
3.9V      -5.587mA   -50.88mA   -2.369mA
4.05V     -16.46mA   -206.5mA   -5.954mA
4.2V      -81.81mA   -376.3mA   -19.65mA
4.35V     -269.7mA   -546.3mA   -43.38mA
4.5V      -463.4mA   -716.1mA   -179.1mA
4.65V     -657.3mA   -886.2mA   -408.6mA
4.8V      -851.5mA   -1.056A    -638.2mA
6.6V      -3.215A    -3.128A    -3.44A
[Ramp]
| variable   typ   min   max
dV/dt_r 0.1484/0.2067e-9   0.1412/0.2192e-9   0.1597/0.2101e-9
dV/dt_f 0.1273/0.3909e-9   0.1260/0.3784e-9   0.1319/0.4079e-9
R_load = 50
[Rising waveform]
R_fixture= 50
V_fixture= 1.27146
V_fixture_min= 1.22475
V_fixture_max= 1.31409
|Time   V(typ)   V(min)   V(max)
0s        1.169V     1.122V     1.21V
1.07ns    1.169V     1.122V     1.217V
1.2ns     1.17V      1.122V     1.153V
1.32ns    1.166V     1.122V     1.285V
1.42ns    1.128V     1.122V     1.349V
1.58ns    1.267V     1.124V     1.385V
1.73ns    1.333V     1.094V     1.397V
1.98ns    1.361V     1.263V     1.407V
2.22ns    1.368V     1.317V     1.413V
4ns       1.374V     1.327V     1.418V
[Falling waveform]
R_fixture= 50
V_fixture= 1.27146
V_fixture_min= 1.22475
V_fixture_max= 1.31409
|Time   V(typ)   V(min)   V(max)
0s        1.375V     1.327V     1.418V
1.16ns    1.374V     1.327V     1.43V
1.27ns    1.375V     1.327V     1.344V
1.39ns    1.371V     1.327V     1.307V
1.51ns    1.285V     1.327V     1.276V
1.62ns    1.25V      1.33V      1.256V
1.73ns    1.228V     1.301V     1.242V
1.88ns    1.206V     1.209V     1.229V
2.42ns    1.175V     1.138V     1.214V
4ns       1.169V     1.122V     1.21V
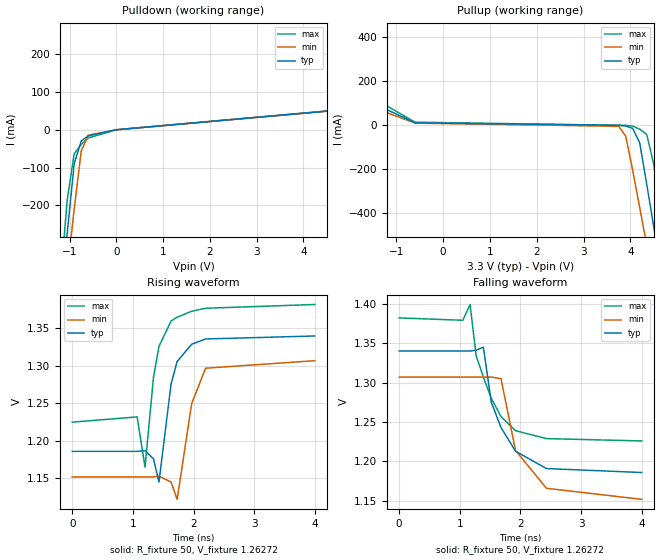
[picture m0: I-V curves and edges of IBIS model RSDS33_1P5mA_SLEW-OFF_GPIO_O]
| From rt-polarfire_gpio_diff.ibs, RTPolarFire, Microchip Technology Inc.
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|   Model RSDS33_1P5mA_SLEW-OFF_GPIO_O
[Model]   RSDS33_1P5mA_SLEW-OFF_GPIO_O
Model_type   Output
Polarity   Non-Inverting
Enable   Active-High
Vmeas =   1.2
Cref =   5p
Rref =   100
|   typ   min   max
C_comp_pullup   2.605e-12   2.605e-12   2.76e-12
C_comp_pulldown  2.605e-12   2.605e-12   2.76e-12
[Temperature Range]  25C   125C   -55C
[Voltage Range]  3.3   3.15   3.45
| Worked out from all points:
|   slope of the pulldown table from 0 to 0.495 V, typ, clamps not added: 360 ohm
|   slope of the pullup table from 0 to 0.495 V, typ, clamps not added: 335 ohm
|   rising waveform, R_fixture 50, V_fixture 1.26272: 20-80 % time 213ps typ, 204ps min, 251ps max; typ from 1.19 V to 1.34 V
|   falling waveform, R_fixture 50, V_fixture 1.26272: 20-80 % time 424ps typ, 411ps min, 439ps max; typ from 1.34 V to 1.19 V
[Pulldown]
|Voltage   I(typ)   I(min)   I(max)
-3.3V     -3.224A    -2.962A    -3.688A
-1.2V     -468.7mA   -550.1mA   -415.8mA
-1.05V    -274.7mA   -379.8mA   -186.1mA
-900mV    -89.9mA    -209.7mA   -63.83mA
-750mV    -29.68mA   -56.81mA   -38.69mA
-600mV    -16.47mA   -14.22mA   -21.77mA
0V        -61.09uA   -53.92uA   -73.62uA
4.5V      49.13mA    49.06mA    49.63mA
5.1V      116mA      105.1mA    123.1mA
6V        245.4mA    216.6mA    272.9mA
6.15V     269.8mA    237.8mA    300.2mA
6.6V      348.9mA    304.3mA    387mA
[Pullup]
|Voltage   I(typ)   I(min)   I(max)
-3.3V     375.3mA    306.9mA    444.9mA
-1.8V     128.9mA    102.5mA    160mA
-600mV    9.431mA    8.282mA    12.31mA
3.75V     -1.849mA   -6.295mA   -1.658mA
3.9V      -5.081mA   -50.42mA   -1.853mA
4.05V     -15.96mA   -206mA     -5.443mA
4.2V      -81.37mA   -375.9mA   -19.15mA
4.35V     -269.2mA   -545.9mA   -42.88mA
4.5V      -463mA     -715.7mA   -178.7mA
4.65V     -656.9mA   -885.7mA   -408.1mA
4.8V      -851.1mA   -1.056A    -637.7mA
6.6V      -3.215A    -3.128A    -3.44A
[Ramp]
| variable   typ   min   max
dV/dt_r 0.1188/0.2116e-9   0.1116/0.2199e-9   0.1304/0.2137e-9
dV/dt_f 97.1275e-3/0.4202e-9   96.2225e-3/0.4029e-9   0.1044/0.4253e-9
R_load = 50
[Rising waveform]
R_fixture= 50
V_fixture= 1.26272
V_fixture_min= 1.23014
V_fixture_max= 1.30355
|Time   V(typ)   V(min)   V(max)
0s        1.186V     1.152V     1.225V
1.07ns    1.186V     1.152V     1.232V
1.2ns     1.187V     1.152V     1.165V
1.34ns    1.176V     1.152V     1.285V
1.43ns    1.145V     1.153V     1.326V
1.63ns    1.276V     1.145V     1.36V
1.73ns    1.306V     1.122V     1.365V
1.97ns    1.329V     1.25V      1.373V
2.2ns     1.336V     1.297V     1.377V
4ns       1.34V      1.307V     1.382V
[Falling waveform]
R_fixture= 50
V_fixture= 1.26272
V_fixture_min= 1.23014
V_fixture_max= 1.30355
|Time   V(typ)   V(min)   V(max)
0s        1.34V      1.307V     1.382V
1.05ns    1.34V      1.307V     1.379V
1.17ns    1.34V      1.307V     1.399V
1.27ns    1.341V     1.307V     1.334V
1.39ns    1.345V     1.307V     1.307V
1.52ns    1.275V     1.307V     1.28V
1.68ns    1.243V     1.305V     1.257V
1.92ns    1.213V     1.214V     1.239V
2.43ns    1.191V     1.166V     1.229V
4ns       1.186V     1.152V     1.226V
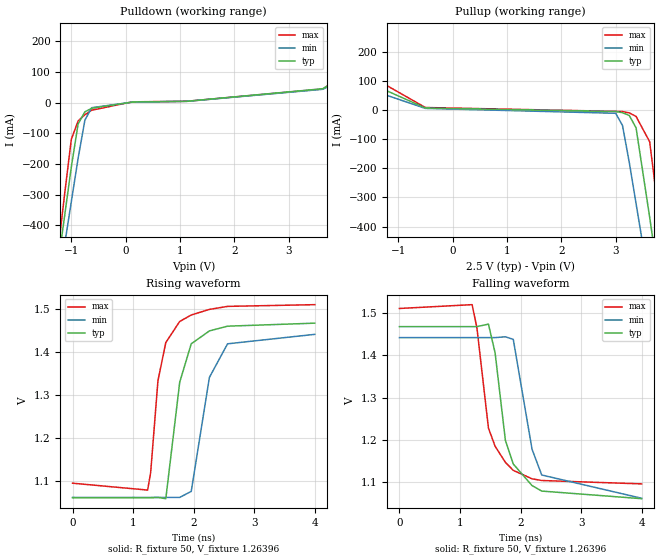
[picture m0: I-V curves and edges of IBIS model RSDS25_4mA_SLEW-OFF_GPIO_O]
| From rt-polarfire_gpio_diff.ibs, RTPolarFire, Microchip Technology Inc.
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|   Model RSDS25_4mA_SLEW-OFF_GPIO_O
[Model]   RSDS25_4mA_SLEW-OFF_GPIO_O
Model_type   Output
Polarity   Non-Inverting
Enable   Active-High
Vmeas =   1.2
Cref =   5p
Rref =   100
|   typ   min   max
C_comp_pullup   2.605e-12   2.605e-12   2.76e-12
C_comp_pulldown  2.605e-12   2.605e-12   2.76e-12
[Temperature Range]  25C   125C   -55C
[Voltage Range]  2.5   2.375   2.625
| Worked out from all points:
|   slope of the pulldown table from 0 to 0.375 V, typ, clamps not added: 104 ohm
|   slope of the pullup table from 0 to 0.375 V, typ, clamps not added: 129 ohm
|   rising waveform, R_fixture 50, V_fixture 1.26396: 20-80 % time 237ps typ, 278ps min, 234ps max; typ from 1.06 V to 1.47 V
|   falling waveform, R_fixture 50, V_fixture 1.26396: 20-80 % time 285ps typ, 277ps min, 298ps max; typ from 1.47 V to 1.06 V
[Pulldown]
|Voltage   I(typ)   I(min)   I(max)
-2.5V     -2.163A    -2.035A    -2.424A
-1.25V    -533.5mA   -606.9mA   -492.7mA
-1.125V   -371.8mA   -465.1mA   -301.1mA
-1V       -210.3mA   -323.2mA   -119.8mA
-875mV    -69.78mA   -181.6mA   -59.96mA
-750mV    -30.28mA   -57.04mA   -39.68mA
-625mV    -18.76mA   -16.82mA   -24.92mA
125mV     1.72mA     1.283mA    2.259mA
1.125V    4.083mA    3.793mA    4.153mA
3.625V    45mA       43.23mA    44.29mA
4.25V     110.1mA    97.03mA    120.4mA
5V        214mA      184.6mA    242.1mA
[Pullup]
|Voltage   I(typ)   I(min)   I(max)
-2.5V     229.4mA    182.5mA    282.3mA
-1.5V     90.6mA     69.32mA    115.4mA
-500mV    7.398mA    5.899mA    8.985mA
3V        -4.875mA   -10.84mA   -4.28mA
3.125V    -8.809mA   -52.73mA   -4.915mA
3.25V     -18.45mA   -179.9mA   -9.474mA
3.375V    -60.99mA   -321.4mA   -21.67mA
3.625V    -368.2mA   -604.7mA   -108.8mA
3.75V     -529.7mA   -746.2mA   -295.5mA
3.875V    -691.4mA   -887.9mA   -486.8mA
4V        -853.2mA   -1.03A     -678.2mA
5V        -2.158A    -2.175A    -2.221A
[Ramp]
| variable   typ   min   max
dV/dt_r 0.2489/0.2374e-9   0.2301/0.2798e-9   0.2596/0.2304e-9
dV/dt_f 0.2480/0.2848e-9   0.2301/0.2785e-9   0.2549/0.2952e-9
R_load = 50
[Rising waveform]
R_fixture= 50
V_fixture= 1.26396
V_fixture_min= 1.25128
V_fixture_max= 1.30289
|Time   V(typ)   V(min)   V(max)
0s        1.062V     1.063V     1.096V
1.24ns    1.062V     1.063V     1.08V
1.29ns    1.062V     1.063V     1.121V
1.41ns    1.063V     1.063V     1.334V
1.54ns    1.06V      1.063V     1.423V
1.77ns    1.331V     1.063V     1.472V
1.96ns    1.42V      1.077V     1.487V
2.26ns    1.45V      1.342V     1.5V
2.56ns    1.461V     1.42V      1.507V
4ns       1.468V     1.442V     1.511V
[Falling waveform]
R_fixture= 50
V_fixture= 1.26396
V_fixture_min= 1.25128
V_fixture_max= 1.30289
|Time   V(typ)   V(min)   V(max)
0s        1.468V     1.442V     1.511V
1.2ns     1.468V     1.442V     1.52V
1.28ns    1.468V     1.442V     1.465V
1.47ns    1.474V     1.442V     1.228V
1.58ns    1.406V     1.442V     1.185V
1.75ns    1.199V     1.444V     1.147V
1.88ns    1.143V     1.438V     1.128V
2.19ns    1.092V     1.178V     1.108V
2.35ns    1.079V     1.117V     1.104V
4ns       1.061V     1.062V     1.096V
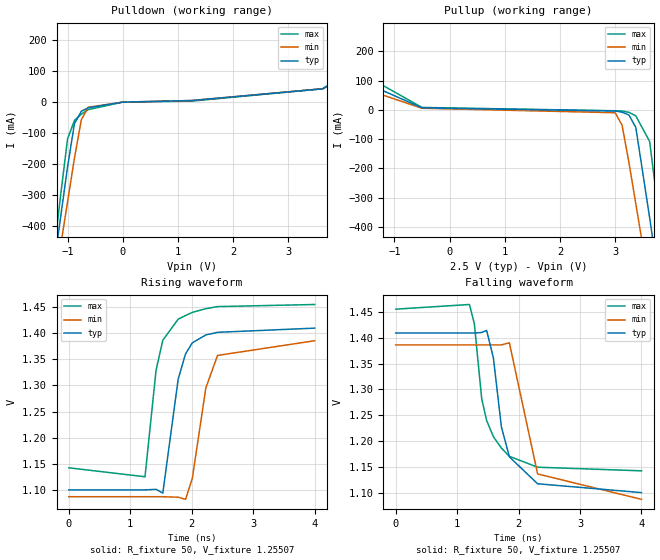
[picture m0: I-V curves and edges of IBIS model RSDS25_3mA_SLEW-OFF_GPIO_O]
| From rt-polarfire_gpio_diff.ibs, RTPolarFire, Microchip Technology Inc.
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|   Model RSDS25_3mA_SLEW-OFF_GPIO_O
[Model]   RSDS25_3mA_SLEW-OFF_GPIO_O
Model_type   Output
Polarity   Non-Inverting
Enable   Active-High
Vmeas =   1.2
Cref =   5p
Rref =   100
|   typ   min   max
C_comp_pullup   2.605e-12   2.605e-12   2.76e-12
C_comp_pulldown  2.605e-12   2.605e-12   2.76e-12
[Temperature Range]  25C   125C   -55C
[Voltage Range]  2.5   2.375   2.625
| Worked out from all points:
|   slope of the pulldown table from 0 to 0.375 V, typ, clamps not added: 136 ohm
|   slope of the pullup table from 0 to 0.375 V, typ, clamps not added: 158 ohm
|   rising waveform, R_fixture 50, V_fixture 1.25507: 20-80 % time 221ps typ, 255ps min, 220ps max; typ from 1.1 V to 1.41 V
|   falling waveform, R_fixture 50, V_fixture 1.25507: 20-80 % time 281ps typ, 271ps min, 296ps max; typ from 1.41 V to 1.1 V
[Pulldown]
|Voltage   I(typ)   I(min)   I(max)
-2.5V     -2.163A    -2.035A    -2.424A
-1.25V    -533.4mA   -606.8mA   -492.4mA
-1.125V   -371.6mA   -465mA     -300.9mA
-1V       -210.1mA   -323.1mA   -119.3mA
-875mV    -69.41mA   -181.4mA   -59.34mA
-750mV    -29.85mA   -56.83mA   -39.08mA
-625mV    -18.35mA   -16.57mA   -24.36mA
0V        -62.69uA   -54.79uA   -76.42uA
1.25V     5.159mA    5.034mA    3.187mA
3.625V    43.02mA    43.43mA    43.24mA
4.25V     109.1mA    96.22mA    119.3mA
5V        213mA      183.7mA    240.9mA
[Pullup]
|Voltage   I(typ)   I(min)   I(max)
-2.5V     228.9mA    182.4mA    281mA
-1.5V     89.55mA    68.71mA    114mA
-500mV    6.765mA    5.47mA     8.164mA
3V        -3.849mA   -9.865mA   -3.239mA
3.125V    -7.793mA   -51.82mA   -3.878mA
3.25V     -17.45mA   -179.1mA   -8.45mA
3.375V    -60.07mA   -320.6mA   -20.66mA
3.625V    -367.4mA   -603.8mA   -107.9mA
3.75V     -528.9mA   -745.3mA   -294.7mA
3.875V    -690.6mA   -887mA     -486mA
4V        -852.4mA   -1.029A    -677.3mA
5V        -2.157A    -2.174A    -2.22A
[Ramp]
| variable   typ   min   max
dV/dt_r 0.1901/0.2238e-9   0.1817/0.2585e-9   0.1971/0.2179e-9
dV/dt_f 0.1889/0.2803e-9   0.1815/0.2734e-9   0.1931/0.2913e-9
R_load = 50
[Rising waveform]
R_fixture= 50
V_fixture= 1.25507
V_fixture_min= 1.23614
V_fixture_max= 1.29855
|Time   V(typ)   V(min)   V(max)
0s        1.101V     1.088V     1.143V
1.24ns    1.101V     1.088V     1.126V
1.42ns    1.102V     1.088V     1.329V
1.53ns    1.095V     1.088V     1.386V
1.78ns    1.312V     1.087V     1.426V
1.9ns     1.36V      1.083V     1.433V
2.01ns    1.381V     1.123V     1.439V
2.23ns    1.396V     1.295V     1.446V
2.42ns    1.401V     1.357V     1.45V
4ns       1.409V     1.385V     1.454V
[Falling waveform]
R_fixture= 50
V_fixture= 1.25507
V_fixture_min= 1.23614
V_fixture_max= 1.29855
|Time   V(typ)   V(min)   V(max)
0s        1.409V     1.386V     1.455V
1.2ns     1.409V     1.386V     1.464V
1.28ns    1.409V     1.386V     1.427V
1.4ns     1.41V      1.386V     1.282V
1.48ns    1.414V     1.386V     1.24V
1.59ns    1.361V     1.386V     1.209V
1.72ns    1.228V     1.386V     1.187V
1.85ns    1.17V      1.39V      1.171V
2.31ns    1.118V     1.137V     1.15V
4ns       1.101V     1.088V     1.143V
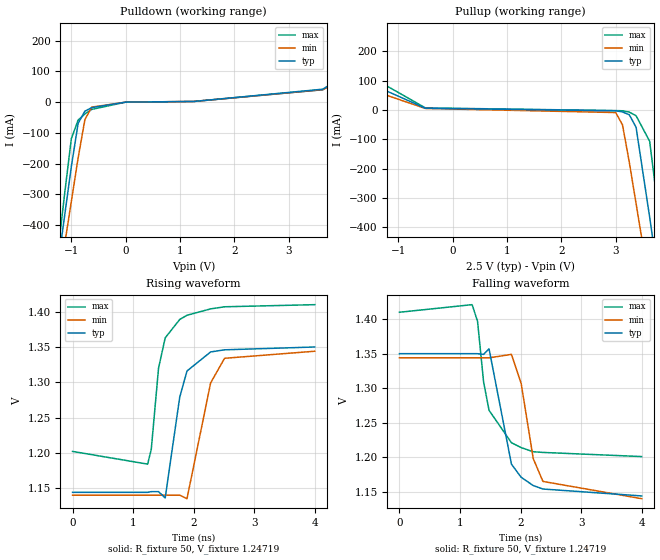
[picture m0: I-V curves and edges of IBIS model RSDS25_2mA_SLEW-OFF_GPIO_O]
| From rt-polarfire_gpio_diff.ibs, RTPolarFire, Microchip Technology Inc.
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|   Model RSDS25_2mA_SLEW-OFF_GPIO_O
[Model]   RSDS25_2mA_SLEW-OFF_GPIO_O
Model_type   Output
Polarity   Non-Inverting
Enable   Active-High
Vmeas =   1.2
Cref =   5p
Rref =   100
|   typ   min   max
C_comp_pullup   2.605e-12   2.605e-12   2.76e-12
C_comp_pulldown  2.605e-12   2.605e-12   2.76e-12
[Temperature Range]  25C   125C   -55C
[Voltage Range]  2.5   2.375   2.625
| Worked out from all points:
|   slope of the pulldown table from 0 to 0.375 V, typ, clamps not added: 205 ohm
|   slope of the pullup table from 0 to 0.375 V, typ, clamps not added: 218 ohm
|   rising waveform, R_fixture 50, V_fixture 1.24719: 20-80 % time 208ps typ, 248ps min, 227ps max; typ from 1.14 V to 1.35 V
|   falling waveform, R_fixture 50, V_fixture 1.24719: 20-80 % time 260ps typ, 254ps min, 304ps max; typ from 1.35 V to 1.14 V
[Pulldown]
|Voltage   I(typ)   I(min)   I(max)
-2.5V     -2.163A    -2.035A    -2.424A
-1.25V    -533.2mA   -606.6mA   -492.2mA
-1.125V   -371.4mA   -464.8mA   -300.6mA
-1V       -209.9mA   -322.9mA   -118.8mA
-875mV    -68.97mA   -181.3mA   -58.61mA
-750mV    -29.33mA   -56.54mA   -38.37mA
-625mV    -17.87mA   -16.23mA   -23.69mA
0V        -60.23uA   -53.32uA   -74.21uA
1.25V     2.109mA    2.079mA    2.112mA
3.625V    41.99mA    40.49mA    40.18mA
4.25V     108mA      95.24mA    118.3mA
5V        211.8mA    182.7mA    239.7mA
[Pullup]
|Voltage   I(typ)   I(min)   I(max)
-2.5V     228.6mA    182.3mA    279.8mA
-1.5V     88.49mA    68.24mA    112.6mA
-500mV    5.853mA    5.055mA    6.983mA
3V        -2.816mA   -8.861mA   -2.191mA
3.125V    -6.77mA    -50.88mA   -2.835mA
3.25V     -16.44mA   -178.2mA   -7.419mA
3.375V    -59.15mA   -319.7mA   -19.64mA
3.625V    -366.5mA   -602.9mA   -107mA
3.75V     -528mA     -744.5mA   -293.8mA
3.875V    -689.7mA   -886.1mA   -485.1mA
4V        -851.5mA   -1.028A    -676.4mA
5V        -2.156A    -2.174A    -2.219A
[Ramp]
| variable   typ   min   max
dV/dt_r 0.1293/0.2102e-9   0.1258/0.2521e-9   0.1356/0.2162e-9
dV/dt_f 0.1277/0.2585e-9   0.1258/0.2596e-9   0.1320/0.2965e-9
R_load = 50
[Rising waveform]
R_fixture= 50
V_fixture= 1.24719
V_fixture_min= 1.24240
V_fixture_max= 1.30595
|Time   V(typ)   V(min)   V(max)
0s        1.144V     1.14V      1.202V
1.24ns    1.144V     1.14V      1.184V
1.3ns     1.145V     1.14V      1.205V
1.42ns    1.145V     1.14V      1.32V
1.53ns    1.136V     1.14V      1.363V
1.77ns    1.279V     1.14V      1.389V
1.89ns    1.316V     1.135V     1.395V
2.28ns    1.343V     1.299V     1.404V
2.51ns    1.346V     1.334V     1.407V
4ns       1.35V      1.344V     1.41V
[Falling waveform]
R_fixture= 50
V_fixture= 1.24719
V_fixture_min= 1.24240
V_fixture_max= 1.30595
|Time   V(typ)   V(min)   V(max)
0s        1.35V      1.344V     1.41V
1.2ns     1.35V      1.344V     1.421V
1.29ns    1.35V      1.344V     1.397V
1.39ns    1.349V     1.344V     1.309V
1.48ns    1.357V     1.344V     1.268V
1.85ns    1.19V      1.349V     1.221V
2.01ns    1.171V     1.307V     1.214V
2.21ns    1.159V     1.198V     1.208V
2.37ns    1.154V     1.165V     1.207V
4ns       1.144V     1.14V      1.201V
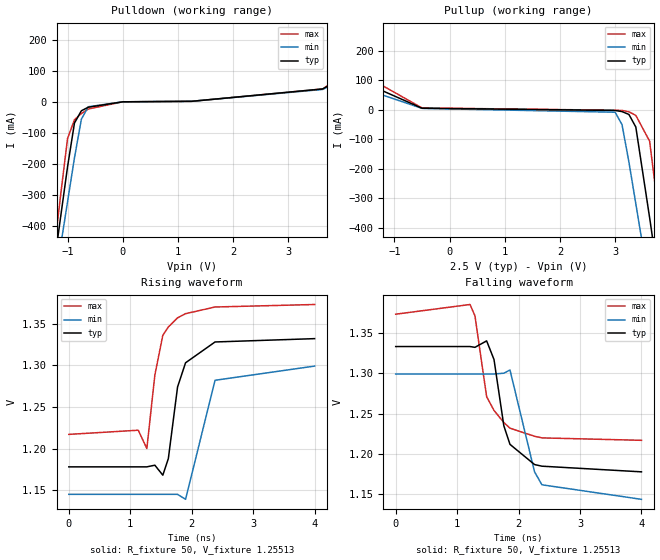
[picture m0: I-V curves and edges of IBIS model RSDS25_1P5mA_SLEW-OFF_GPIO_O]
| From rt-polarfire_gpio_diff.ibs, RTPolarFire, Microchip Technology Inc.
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|   Model RSDS25_1P5mA_SLEW-OFF_GPIO_O
[Model]   RSDS25_1P5mA_SLEW-OFF_GPIO_O
Model_type   Output
Polarity   Non-Inverting
Enable   Active-High
Vmeas =   1.2
Cref =   5p
Rref =   100
|   typ   min   max
C_comp_pullup   2.605e-12   2.605e-12   2.76e-12
C_comp_pulldown  2.605e-12   2.605e-12   2.76e-12
[Temperature Range]  25C   125C   -55C
[Voltage Range]  2.5   2.375   2.625
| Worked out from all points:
|   slope of the pulldown table from 0 to 0.375 V, typ, clamps not added: 278 ohm
|   slope of the pullup table from 0 to 0.375 V, typ, clamps not added: 279 ohm
|   rising waveform, R_fixture 50, V_fixture 1.25513: 20-80 % time 238ps typ, 241ps min, 237ps max; typ from 1.18 V to 1.33 V
|   falling waveform, R_fixture 50, V_fixture 1.25513: 20-80 % time 252ps typ, 249ps min, 317ps max; typ from 1.33 V to 1.18 V
[Pulldown]
|Voltage   I(typ)   I(min)   I(max)
-2.5V     -2.163A    -2.035A    -2.424A
-1.25V    -533mA     -606.5mA   -492mA
-1.125V   -371.3mA   -464.7mA   -300.5mA
-1V       -209.8mA   -322.8mA   -118.5mA
-875mV    -68.71mA   -181.2mA   -58.17mA
-750mV    -29.02mA   -56.37mA   -37.95mA
-625mV    -17.57mA   -16.02mA   -23.29mA
0V        -59.52uA   -51.69uA   -72.38uA
1.25V     1.571mA    1.577mA    1.564mA
3.625V    41.46mA    40mA       41.64mA
4.25V     107.5mA    94.74mA    117.7mA
5V        211.2mA    182.1mA    239.1mA
[Pullup]
|Voltage   I(typ)   I(min)   I(max)
-2.5V     228.5mA    182.2mA    279.3mA
-1.5V     87.98mA    68.07mA    111.9mA
-500mV    5.224mA    4.609mA    6.169mA
3V        -2.308mA   -8.358mA   -1.674mA
3.125V    -6.267mA   -50.41mA   -2.32mA
3.25V     -15.95mA   -177.7mA   -6.91mA
3.375V    -58.69mA   -319.2mA   -19.14mA
3.625V    -366.1mA   -602.5mA   -106.6mA
3.75V     -527.6mA   -744mA     -293.4mA
3.875V    -689.3mA   -885.7mA   -484.7mA
4V        -851.1mA   -1.028A    -676mA
5V        -2.156A    -2.173A    -2.218A
[Ramp]
| variable   typ   min   max
dV/dt_r 98.8284e-3/0.2384e-9   97.1399e-3/0.2512e-9   0.1054/0.2205e-9
dV/dt_f 97.7235e-3/0.2493e-9   96.6032e-3/0.2549e-9   0.1011/0.3045e-9
R_load = 50
[Rising waveform]
R_fixture= 50
V_fixture= 1.25513
V_fixture_min= 1.22206
V_fixture_max= 1.29493
|Time   V(typ)   V(min)   V(max)
0s        1.178V     1.145V     1.217V
1.13ns    1.178V     1.145V     1.222V
1.27ns    1.178V     1.145V     1.2V
1.4ns     1.18V      1.145V     1.288V
1.53ns    1.168V     1.145V     1.336V
1.62ns    1.188V     1.145V     1.346V
1.77ns    1.274V     1.145V     1.357V
1.9ns     1.303V     1.139V     1.362V
2.38ns    1.328V     1.282V     1.37V
4ns       1.332V     1.299V     1.373V
[Falling waveform]
R_fixture= 50
V_fixture= 1.25513
V_fixture_min= 1.22206
V_fixture_max= 1.29493
|Time   V(typ)   V(min)   V(max)
0s        1.333V     1.299V     1.373V
1.21ns    1.333V     1.299V     1.385V
1.29ns    1.332V     1.299V     1.371V
1.48ns    1.34V      1.299V     1.271V
1.6ns     1.317V     1.299V     1.254V
1.76ns    1.235V     1.3V       1.239V
1.86ns    1.212V     1.304V     1.232V
2.26ns    1.187V     1.178V     1.222V
2.38ns    1.185V     1.162V     1.22V
4ns       1.178V     1.144V     1.217V
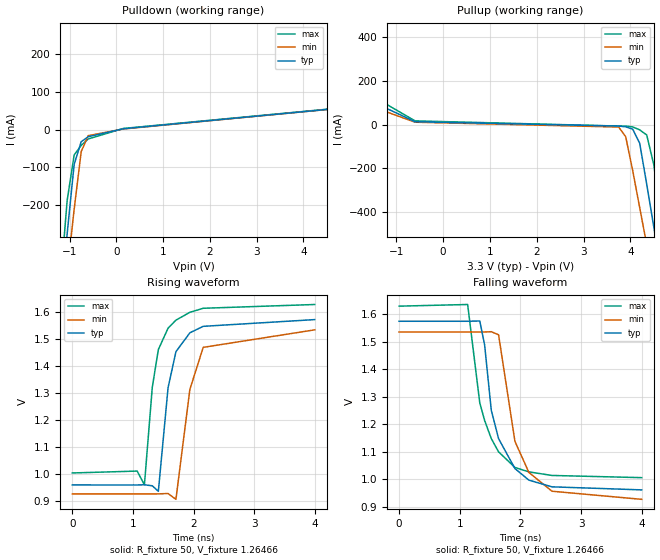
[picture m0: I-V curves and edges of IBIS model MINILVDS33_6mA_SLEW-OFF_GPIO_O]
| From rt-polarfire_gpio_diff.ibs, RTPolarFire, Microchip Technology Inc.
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|   Model MINILVDS33_6mA_SLEW-OFF_GPIO_O
[Model]   MINILVDS33_6mA_SLEW-OFF_GPIO_O
Model_type   Output
Polarity   Non-Inverting
Enable   Active-High
Vmeas =   1.2
Cref =   5p
Rref =   100
|   typ   min   max
C_comp_pullup   2.605e-12   2.605e-12   2.76e-12
C_comp_pulldown  2.605e-12   2.605e-12   2.76e-12
[Temperature Range]  25C   125C   -55C
[Voltage Range]  3.3   3.15   3.45
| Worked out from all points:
|   slope of the pulldown table from 0 to 0.495 V, typ, clamps not added: 87.8 ohm
|   slope of the pullup table from 0 to 0.495 V, typ, clamps not added: 102 ohm
|   rising waveform, R_fixture 50, V_fixture 1.26466: 20-80 % time 221ps typ, 241ps min, 232ps max; typ from 0.96 V to 1.57 V
|   falling waveform, R_fixture 50, V_fixture 1.26466: 20-80 % time 340ps typ, 338ps min, 346ps max; typ from 1.57 V to 0.961 V
[Pulldown]
|Voltage   I(typ)   I(min)   I(max)
-3.3V     -3.224A    -2.962A    -3.689A
-1.2V     -469.6mA   -550.9mA   -416.8mA
-1.05V    -275.6mA   -380.6mA   -187.4mA
-900mV    -91.51mA   -210.5mA   -66.84mA
-750mV    -31.88mA   -58.11mA   -41.59mA
-600mV    -18.49mA   -15.76mA   -24.47mA
150mV     2.591mA    2.01mA     3.387mA
4.5V      53.84mA    53.69mA    54.45mA
5.1V      120.7mA    109.8mA    127.8mA
6V        250.7mA    221.8mA    278.2mA
6.15V     275.2mA    243.1mA    305.7mA
6.6V      354.6mA    309.9mA    392.9mA
[Pullup]
|Voltage   I(typ)   I(min)   I(max)
-3.3V     376.5mA    307.5mA    447.5mA
-1.8V     133.6mA    104.2mA    166.2mA
-600mV    13.4mA     11.28mA    17.4mA
3.75V     -6.487mA   -10.85mA   -6.355mA
3.9V      -9.67mA    -54.64mA   -6.542mA
4.05V     -20.47mA   -210mA     -10.08mA
4.2V      -85.38mA   -379.9mA   -23.71mA
4.35V     -273.1mA   -549.9mA   -47.38mA
4.5V      -466.9mA   -719.7mA   -182.5mA
4.65V     -660.8mA   -889.7mA   -412mA
4.8V      -855mA     -1.06A     -641.6mA
6.6V      -3.219A    -3.132A    -3.444A
[Ramp]
| variable   typ   min   max
dV/dt_r 0.3863/0.2177e-9   0.3780/0.2430e-9   0.4016/0.2273e-9
dV/dt_f 0.3709/0.3390e-9   0.3680/0.3372e-9   0.3791/0.3443e-9
R_load = 50
[Rising waveform]
R_fixture= 50
V_fixture= 1.26466
V_fixture_min= 1.22785
V_fixture_max= 1.31682
|Time   V(typ)   V(min)   V(max)
0s        959.6mV    926.3mV    1.004V
1.07ns    959.5mV    926.3mV    1.011V
1.19ns    960.2mV    926.3mV    960.3mV
1.32ns    956.4mV    926.2mV    1.322V
1.42ns    936mV      926.4mV    1.462V
1.58ns    1.32V      927.8mV    1.541V
1.71ns    1.454V     906.2mV    1.571V
1.94ns    1.524V     1.314V     1.6V
2.16ns    1.548V     1.47V      1.615V
4ns       1.573V     1.535V     1.629V
[Falling waveform]
R_fixture= 50
V_fixture= 1.26466
V_fixture_min= 1.22785
V_fixture_max= 1.31682
|Time   V(typ)   V(min)   V(max)
0s        1.574V     1.535V     1.629V
1.13ns    1.574V     1.535V     1.635V
1.33ns    1.575V     1.535V     1.277V
1.41ns    1.488V     1.535V     1.213V
1.52ns    1.25V      1.536V     1.147V
1.64ns    1.147V     1.525V     1.099V
1.91ns    1.038V     1.137V     1.042V
2.14ns    995.9mV    1.024V     1.026V
2.52ns    971.6mV    955.6mV    1.013V
4ns       960.5mV    926.1mV    1.005V
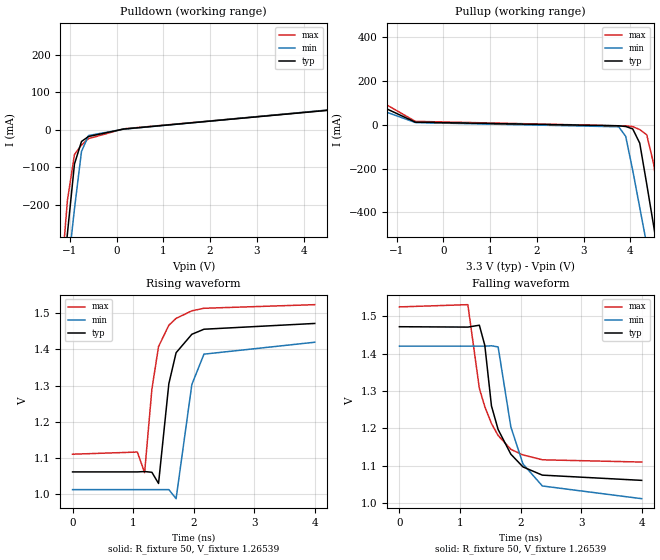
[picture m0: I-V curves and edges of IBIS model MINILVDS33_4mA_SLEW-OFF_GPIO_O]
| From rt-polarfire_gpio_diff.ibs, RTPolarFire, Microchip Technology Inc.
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|   Model MINILVDS33_4mA_SLEW-OFF_GPIO_O
[Model]   MINILVDS33_4mA_SLEW-OFF_GPIO_O
Model_type   Output
Polarity   Non-Inverting
Enable   Active-High
Vmeas =   1.2
Cref =   5p
Rref =   100
|   typ   min   max
C_comp_pullup   2.605e-12   2.605e-12   2.76e-12
C_comp_pulldown  2.605e-12   2.605e-12   2.76e-12
[Temperature Range]  25C   125C   -55C
[Voltage Range]  3.3   3.15   3.45
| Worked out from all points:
|   slope of the pulldown table from 0 to 0.495 V, typ, clamps not added: 131 ohm
|   slope of the pullup table from 0 to 0.495 V, typ, clamps not added: 138 ohm
|   rising waveform, R_fixture 50, V_fixture 1.26539: 20-80 % time 215ps typ, 219ps min, 232ps max; typ from 1.06 V to 1.47 V
|   falling waveform, R_fixture 50, V_fixture 1.26539: 20-80 % time 354ps typ, 349ps min, 364ps max; typ from 1.47 V to 1.06 V
[Pulldown]
|Voltage   I(typ)   I(min)   I(max)
-3.3V     -3.224A    -2.962A    -3.688A
-1.2V     -469.2mA   -550.6mA   -416.4mA
-1.05V    -275.2mA   -380.3mA   -186.9mA
-900mV    -90.9mA    -210.2mA   -65.71mA
-750mV    -31.06mA   -57.63mA   -40.51mA
-600mV    -17.74mA   -15.19mA   -23.47mA
150mV     2.11mA     1.675mA    2.647mA
4.5V      51.75mA    52.66mA    52.26mA
5.1V      118.6mA    107.7mA    125.7mA
6V        248.4mA    219.5mA    275.9mA
6.15V     272.9mA    240.8mA    303.3mA
6.6V      352.1mA    307.4mA    390.3mA
[Pullup]
|Voltage   I(typ)   I(min)   I(max)
-3.3V     375.9mA    307.2mA    445.8mA
-1.8V     131.5mA    103.2mA    163.5mA
-600mV    12.28mA    10.41mA    15.98mA
3.75V     -4.424mA   -8.824mA   -4.266mA
3.9V      -7.63mA    -52.76mA   -4.457mA
4.05V     -18.46mA   -208.2mA   -8.018mA
4.2V      -83.59mA   -378.1mA   -21.68mA
4.35V     -271.4mA   -548.1mA   -45.37mA
4.5V      -465.1mA   -717.9mA   -180.8mA
4.65V     -659.1mA   -887.9mA   -410.3mA
4.8V      -853.2mA   -1.058A    -639.9mA
6.6V      -3.217A    -3.13A     -3.442A
[Ramp]
| variable   typ   min   max
dV/dt_r 0.2678/0.2157e-9   0.2600/0.2226e-9   0.2795/0.2177e-9
dV/dt_f 0.2493/0.3518e-9   0.2474/0.3488e-9   0.2536/0.3619e-9
R_load = 50
[Rising waveform]
R_fixture= 50
V_fixture= 1.26539
V_fixture_min= 1.21493
V_fixture_max= 1.31643
|Time   V(typ)   V(min)   V(max)
0s        1.061V     1.012V     1.11V
1.07ns    1.061V     1.012V     1.116V
1.19ns    1.062V     1.012V     1.059V
1.31ns    1.06V      1.012V     1.29V
1.42ns    1.029V     1.012V     1.408V
1.59ns    1.305V     1.012V     1.467V
1.71ns    1.391V     986.9mV    1.486V
1.97ns    1.442V     1.303V     1.507V
2.17ns    1.456V     1.387V     1.514V
4ns       1.472V     1.42V      1.524V
[Falling waveform]
R_fixture= 50
V_fixture= 1.26539
V_fixture_min= 1.21493
V_fixture_max= 1.31643
|Time   V(typ)   V(min)   V(max)
0s        1.472V     1.42V      1.525V
1.13ns    1.471V     1.42V      1.531V
1.32ns    1.476V     1.42V      1.307V
1.41ns    1.422V     1.42V      1.258V
1.52ns    1.26V      1.421V     1.213V
1.63ns    1.197V     1.418V     1.181V
1.84ns    1.131V     1.204V     1.144V
2.04ns    1.097V     1.105V     1.129V
2.36ns    1.075V     1.046V     1.116V
4ns       1.061V     1.012V     1.11V
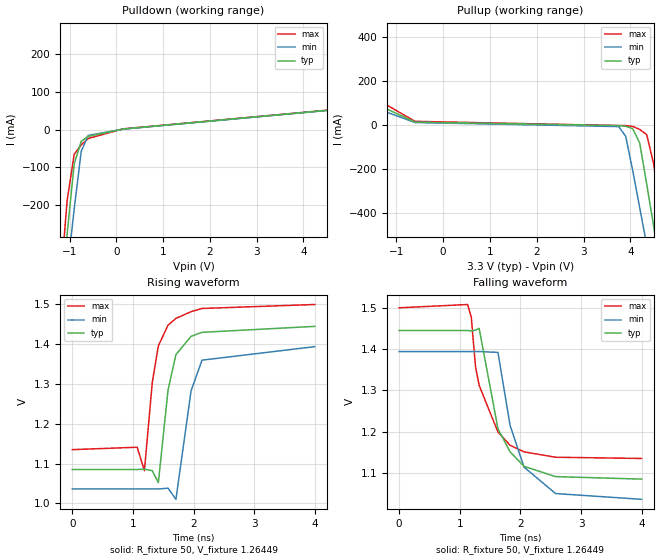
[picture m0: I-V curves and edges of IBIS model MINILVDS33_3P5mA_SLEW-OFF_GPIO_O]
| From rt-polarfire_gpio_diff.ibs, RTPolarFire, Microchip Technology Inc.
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|   Model MINILVDS33_3P5mA_SLEW-OFF_GPIO_O
[Model]   MINILVDS33_3P5mA_SLEW-OFF_GPIO_O
Model_type   Output
Polarity   Non-Inverting
Enable   Active-High
Vmeas =   1.2
Cref =   5p
Rref =   100
|   typ   min   max
C_comp_pullup   2.605e-12   2.605e-12   2.76e-12
C_comp_pulldown  2.605e-12   2.605e-12   2.76e-12
[Temperature Range]  25C   125C   -55C
[Voltage Range]  3.3   3.15   3.45
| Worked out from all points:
|   slope of the pulldown table from 0 to 0.495 V, typ, clamps not added: 149 ohm
|   slope of the pullup table from 0 to 0.495 V, typ, clamps not added: 154 ohm
|   rising waveform, R_fixture 50, V_fixture 1.26449: 20-80 % time 211ps typ, 211ps min, 224ps max; typ from 1.08 V to 1.45 V
|   falling waveform, R_fixture 50, V_fixture 1.26449: 20-80 % time 364ps typ, 352ps min, 371ps max; typ from 1.45 V to 1.08 V
[Pulldown]
|Voltage   I(typ)   I(min)   I(max)
-3.3V     -3.224A    -2.962A    -3.688A
-1.2V     -469.1mA   -550.5mA   -416.3mA
-1.05V    -275.2mA   -380.2mA   -186.7mA
-900mV    -90.73mA   -210.1mA   -65.42mA
-750mV    -30.83mA   -57.49mA   -40.23mA
-600mV    -17.53mA   -15.03mA   -23.21mA
150mV     1.956mA    1.567mA    2.432mA
4.5V      51.24mA    51.16mA    51.77mA
5.1V      118.1mA    107.2mA    125.2mA
6V        247.8mA    219mA      275.3mA
6.15V     272.3mA    240.2mA    302.7mA
6.6V      351.5mA    306.8mA    389.7mA
[Pullup]
|Voltage   I(typ)   I(min)   I(max)
-3.3V     375.7mA    307.2mA    445.5mA
-1.8V     130.9mA    103mA      162.8mA
-600mV    11.9mA     10.12mA    15.49mA
3.75V     -3.915mA   -8.323mA   -3.752mA
3.9V      -7.126mA   -52.3mA    -3.943mA
4.05V     -17.97mA   -207.8mA   -7.51mA
4.2V      -83.15mA   -377.7mA   -21.18mA
4.35V     -271mA     -547.6mA   -44.88mA
4.5V      -464.7mA   -717.5mA   -180.4mA
4.65V     -658.7mA   -887.5mA   -409.9mA
4.8V      -852.8mA   -1.058A    -639.5mA
6.6V      -3.216A    -3.13A     -3.442A
[Ramp]
| variable   typ   min   max
dV/dt_r 0.2385/0.2084e-9   0.2308/0.2175e-9   0.2511/0.2156e-9
dV/dt_f 0.2190/0.3612e-9   0.2177/0.3509e-9   0.2246/0.3670e-9
R_load = 50
[Rising waveform]
R_fixture= 50
V_fixture= 1.26449
V_fixture_min= 1.21440
V_fixture_max= 1.31725
|Time   V(typ)   V(min)   V(max)
0s        1.085V     1.036V     1.135V
1.07ns    1.085V     1.036V     1.141V
1.19ns    1.086V     1.036V     1.082V
1.32ns    1.082V     1.036V     1.304V
1.42ns    1.052V     1.036V     1.396V
1.58ns    1.285V     1.038V     1.448V
1.71ns    1.374V     1.01V      1.465V
1.96ns    1.42V      1.283V     1.482V
2.14ns    1.43V      1.36V      1.49V
4ns       1.445V     1.394V     1.5V
[Falling waveform]
R_fixture= 50
V_fixture= 1.26449
V_fixture_min= 1.21440
V_fixture_max= 1.31725
|Time   V(typ)   V(min)   V(max)
0s        1.445V     1.394V     1.5V
1.13ns    1.445V     1.394V     1.508V
1.19ns    1.444V     1.394V     1.477V
1.26ns    1.446V     1.394V     1.357V
1.32ns    1.45V      1.394V     1.312V
1.63ns    1.207V     1.392V     1.199V
1.83ns    1.151V     1.215V     1.167V
2.06ns    1.116V     1.114V     1.151V
2.58ns    1.091V     1.05V      1.138V
4ns       1.085V     1.036V     1.135V
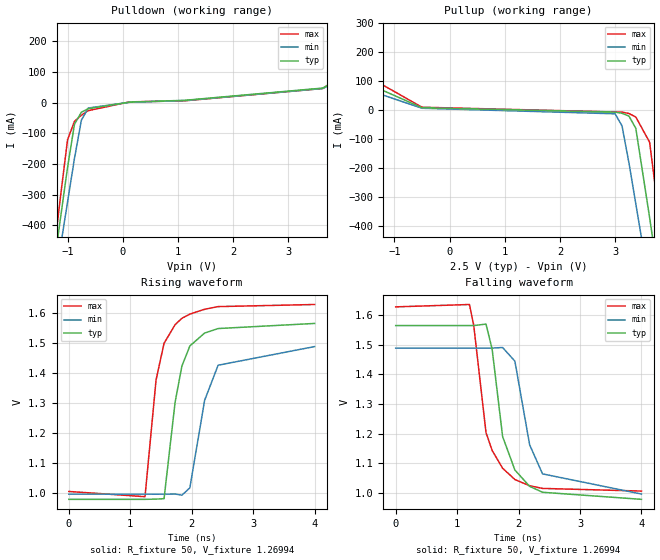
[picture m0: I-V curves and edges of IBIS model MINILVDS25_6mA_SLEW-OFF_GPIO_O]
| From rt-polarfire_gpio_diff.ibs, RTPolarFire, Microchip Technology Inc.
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|   Model MINILVDS25_6mA_SLEW-OFF_GPIO_O
[Model]   MINILVDS25_6mA_SLEW-OFF_GPIO_O
Model_type   Output
Polarity   Non-Inverting
Enable   Active-High
Vmeas =   1.2
Cref =   5p
Rref =   100
|   typ   min   max
C_comp_pullup   2.605e-12   2.605e-12   2.76e-12
C_comp_pulldown  2.605e-12   2.605e-12   2.76e-12
[Temperature Range]  25C   125C   -55C
[Voltage Range]  2.5   2.375   2.625
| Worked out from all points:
|   slope of the pulldown table from 0 to 0.375 V, typ, clamps not added: 77.2 ohm
|   slope of the pullup table from 0 to 0.375 V, typ, clamps not added: 103 ohm
|   rising waveform, R_fixture 50, V_fixture 1.26994: 20-80 % time 246ps typ, 295ps min, 239ps max; typ from 0.979 V to 1.56 V
|   falling waveform, R_fixture 50, V_fixture 1.26994: 20-80 % time 290ps typ, 296ps min, 302ps max; typ from 1.56 V to 0.978 V
[Pulldown]
|Voltage   I(typ)   I(min)   I(max)
-2.5V     -2.164A    -2.035A    -2.425A
-1.25V    -533.8mA   -607.1mA   -493mA
-1.125V   -372.1mA   -465.3mA   -301.5mA
-1V       -210.6mA   -323.4mA   -120.6mA
-875mV    -70.37mA   -181.7mA   -60.98mA
-750mV    -30.96mA   -57.31mA   -40.66mA
-625mV    -19.38mA   -17.15mA   -25.84mA
125mV     2.033mA    1.441mA    2.791mA
1.125V    7.937mA    6.946mA    6.35mA
3.625V    47.81mA    46.37mA    46.41mA
4.25V     111.9mA    98.2mA     122.5mA
5V        216mA      185.9mA    244.4mA
[Pullup]
|Voltage   I(typ)   I(min)   I(max)
-2.5V     231mA      182.9mA    284.8mA
-1.5V     92.37mA    70.56mA    117.7mA
-500mV    8.222mA    6.451mA    10.05mA
3V        -6.915mA   -12.63mA   -6.367mA
3.125V    -10.83mA   -54.39mA   -6.994mA
3.25V     -20.45mA   -181.5mA   -11.53mA
3.375V    -62.83mA   -323mA     -23.69mA
3.625V    -370mA     -606.3mA   -110.5mA
3.75V     -531.5mA   -747.8mA   -297.3mA
3.875V    -693.2mA   -889.5mA   -488.6mA
4V        -855mA     -1.031A    -679.9mA
5V        -2.159A    -2.177A    -2.222A
[Ramp]
| variable   typ   min   max
dV/dt_r 0.3562/0.2473e-9   0.2974/0.2949e-9   0.3837/0.2379e-9
dV/dt_f 0.3552/0.2901e-9   0.2979/0.2959e-9   0.3785/0.3006e-9
R_load = 50
[Rising waveform]
R_fixture= 50
V_fixture= 1.26994
V_fixture_min= 1.23959
V_fixture_max= 1.31635
|Time   V(typ)   V(min)   V(max)
0s        978.8mV    996mV      1.005V
1.24ns    978.8mV    996mV      987.6mV
1.42ns    979.5mV    995.9mV    1.376V
1.55ns    981mV      996mV      1.498V
1.73ns    1.302V     996.5mV    1.56V
1.84ns    1.422V     992.5mV    1.581V
1.97ns    1.489V     1.017V     1.595V
2.21ns    1.532V     1.308V     1.611V
2.43ns    1.547V     1.425V     1.62V
4ns       1.564V     1.487V     1.627V
[Falling waveform]
R_fixture= 50
V_fixture= 1.26994
V_fixture_min= 1.23959
V_fixture_max= 1.31635
|Time   V(typ)   V(min)   V(max)
0s        1.564V     1.488V     1.627V
1.2ns     1.564V     1.488V     1.635V
1.27ns    1.564V     1.488V     1.565V
1.47ns    1.569V     1.488V     1.203V
1.57ns    1.484V     1.488V     1.143V
1.74ns    1.19V      1.49V      1.083V
1.94ns    1.077V     1.444V     1.045V
2.18ns    1.022V     1.162V     1.024V
2.39ns    1.002V     1.064V     1.015V
4ns       978.2mV    996mV      1.006V
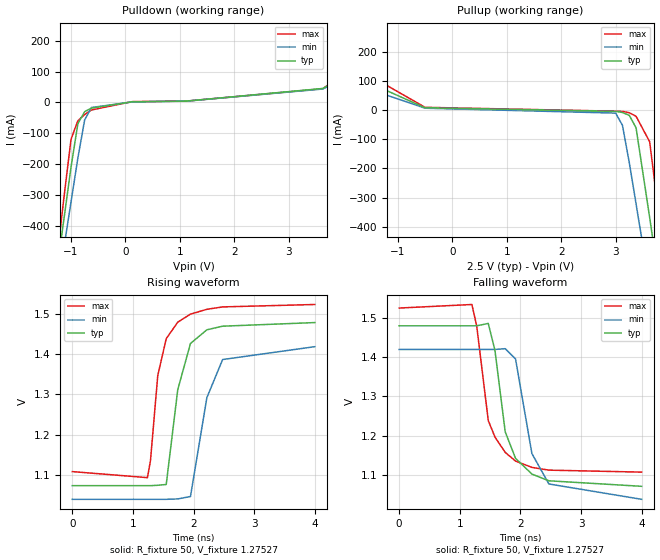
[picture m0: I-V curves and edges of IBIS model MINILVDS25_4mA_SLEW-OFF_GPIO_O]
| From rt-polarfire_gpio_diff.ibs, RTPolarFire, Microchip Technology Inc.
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|   Model MINILVDS25_4mA_SLEW-OFF_GPIO_O
[Model]   MINILVDS25_4mA_SLEW-OFF_GPIO_O
Model_type   Output
Polarity   Non-Inverting
Enable   Active-High
Vmeas =   1.2
Cref =   5p
Rref =   100
|   typ   min   max
C_comp_pullup   2.605e-12   2.605e-12   2.76e-12
C_comp_pulldown  2.605e-12   2.605e-12   2.76e-12
[Temperature Range]  25C   125C   -55C
[Voltage Range]  2.5   2.375   2.625
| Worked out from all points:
|   slope of the pulldown table from 0 to 0.375 V, typ, clamps not added: 104 ohm
|   slope of the pullup table from 0 to 0.375 V, typ, clamps not added: 129 ohm
|   rising waveform, R_fixture 50, V_fixture 1.27527: 20-80 % time 229ps typ, 272ps min, 236ps max; typ from 1.07 V to 1.48 V
|   falling waveform, R_fixture 50, V_fixture 1.27527: 20-80 % time 284ps typ, 290ps min, 295ps max; typ from 1.48 V to 1.07 V
[Pulldown]
|Voltage   I(typ)   I(min)   I(max)
-2.5V     -2.163A    -2.035A    -2.424A
-1.25V    -533.5mA   -606.9mA   -492.7mA
-1.125V   -371.8mA   -465.1mA   -301.1mA
-1V       -210.3mA   -323.2mA   -119.8mA
-875mV    -69.78mA   -181.6mA   -59.96mA
-750mV    -30.28mA   -57.04mA   -39.68mA
-625mV    -18.75mA   -16.83mA   -24.92mA
125mV     1.717mA    1.287mA    2.257mA
1.125V    4.077mA    3.809mA    4.158mA
3.625V    44.98mA    43.26mA    44.29mA
4.25V     110.1mA    97.06mA    120.4mA
5V        214mA      184.7mA    242.1mA
[Pullup]
|Voltage   I(typ)   I(min)   I(max)
-2.5V     229.4mA    182.5mA    282.3mA
-1.5V     90.6mA     69.32mA    115.4mA
-500mV    7.397mA    5.9mA      8.984mA
3V        -4.875mA   -10.84mA   -4.281mA
3.125V    -8.81mA    -52.72mA   -4.916mA
3.25V     -18.46mA   -179.9mA   -9.476mA
3.375V    -61mA      -321.4mA   -21.67mA
3.625V    -368.2mA   -604.7mA   -108.8mA
3.75V     -529.7mA   -746.2mA   -295.5mA
3.875V    -691.4mA   -887.9mA   -486.8mA
4V        -853.2mA   -1.03A     -678.2mA
5V        -2.158A    -2.175A    -2.221A
[Ramp]
| variable   typ   min   max
dV/dt_r 0.2483/0.2312e-9   0.2309/0.2738e-9   0.2595/0.2322e-9
dV/dt_f 0.2480/0.2833e-9   0.2306/0.2903e-9   0.2555/0.2925e-9
R_load = 50
[Rising waveform]
R_fixture= 50
V_fixture= 1.27527
V_fixture_min= 1.22745
V_fixture_max= 1.31572
|Time   V(typ)   V(min)   V(max)
0s        1.073V     1.039V     1.108V
1.24ns    1.073V     1.039V     1.093V
1.29ns    1.073V     1.039V     1.135V
1.41ns    1.074V     1.039V     1.347V
1.55ns    1.076V     1.039V     1.439V
1.74ns    1.312V     1.04V      1.48V
1.95ns    1.427V     1.046V     1.5V
2.22ns    1.461V     1.292V     1.512V
2.48ns    1.47V      1.387V     1.518V
4ns       1.479V     1.419V     1.524V
[Falling waveform]
R_fixture= 50
V_fixture= 1.27527
V_fixture_min= 1.22745
V_fixture_max= 1.31572
|Time   V(typ)   V(min)   V(max)
0s        1.479V     1.419V     1.524V
1.2ns     1.479V     1.419V     1.533V
1.28ns    1.479V     1.419V     1.478V
1.47ns    1.485V     1.419V     1.239V
1.58ns    1.417V     1.419V     1.197V
1.75ns    1.21V      1.421V     1.158V
1.92ns    1.143V     1.395V     1.136V
2.19ns    1.103V     1.155V     1.12V
2.47ns    1.086V     1.078V     1.113V
4ns       1.072V     1.039V     1.108V
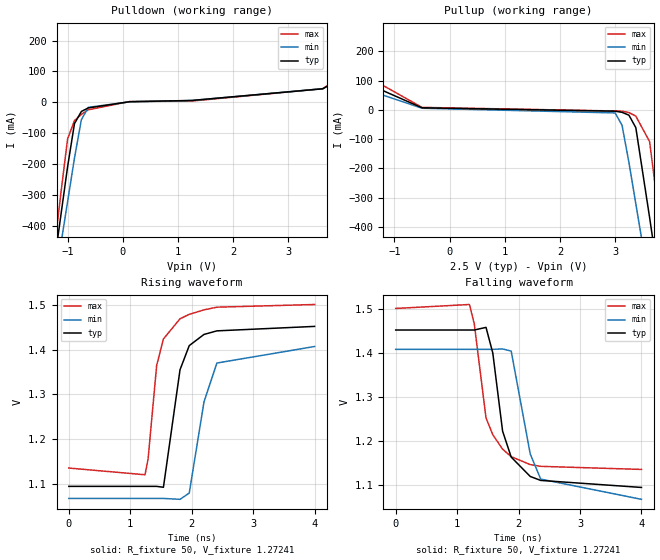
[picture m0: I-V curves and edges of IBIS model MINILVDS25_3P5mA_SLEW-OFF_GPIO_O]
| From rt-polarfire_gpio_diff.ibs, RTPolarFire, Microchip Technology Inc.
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|   Model MINILVDS25_3P5mA_SLEW-OFF_GPIO_O
[Model]   MINILVDS25_3P5mA_SLEW-OFF_GPIO_O
Model_type   Output
Polarity   Non-Inverting
Enable   Active-High
Vmeas =   1.2
Cref =   5p
Rref =   100
|   typ   min   max
C_comp_pullup   2.605e-12   2.605e-12   2.76e-12
C_comp_pulldown  2.605e-12   2.605e-12   2.76e-12
[Temperature Range]  25C   125C   -55C
[Voltage Range]  2.5   2.375   2.625
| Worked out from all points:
|   slope of the pulldown table from 0 to 0.375 V, typ, clamps not added: 117 ohm
|   slope of the pullup table from 0 to 0.375 V, typ, clamps not added: 141 ohm
|   rising waveform, R_fixture 50, V_fixture 1.27241: 20-80 % time 229ps typ, 265ps min, 227ps max; typ from 1.09 V to 1.45 V
|   falling waveform, R_fixture 50, V_fixture 1.27241: 20-80 % time 268ps typ, 273ps min, 293ps max; typ from 1.45 V to 1.09 V
[Pulldown]
|Voltage   I(typ)   I(min)   I(max)
-2.5V     -2.163A    -2.035A    -2.424A
-1.25V    -533.5mA   -606.8mA   -492.6mA
-1.125V   -371.7mA   -465mA     -301mA
-1V       -210.2mA   -323.2mA   -119.6mA
-875mV    -69.6mA    -181.5mA   -59.67mA
-750mV    -30.07mA   -56.94mA   -39.41mA
-625mV    -18.56mA   -16.71mA   -24.67mA
125mV     1.608mA    1.22mA     2.093mA
1.25V     5.661mA    5.459mA    3.76mA
3.625V    43.5mA     43.85mA    43.78mA
4.25V     109.6mA    96.65mA    119.9mA
5V        213.5mA    184.2mA    241.5mA
[Pullup]
|Voltage   I(typ)   I(min)   I(max)
-2.5V     229.1mA    182.4mA    281.7mA
-1.5V     90.1mA     69.01mA    114.7mA
-500mV    7.111mA    5.706mA    8.615mA
3V        -4.369mA   -10.36mA   -3.767mA
3.125V    -8.308mA   -52.28mA   -4.405mA
3.25V     -17.96mA   -179.5mA   -8.971mA
3.375V    -60.54mA   -321mA     -21.17mA
3.625V    -367.8mA   -604.2mA   -108.3mA
3.75V     -529.3mA   -745.8mA   -295.1mA
3.875V    -691mA     -887.5mA   -486.4mA
4V        -852.8mA   -1.029A    -677.7mA
5V        -2.157A    -2.175A    -2.22A
[Ramp]
| variable   typ   min   max
dV/dt_r 0.2200/0.2303e-9   0.2071/0.2667e-9   0.2292/0.2263e-9
dV/dt_f 0.2187/0.2674e-9   0.2072/0.2751e-9   0.2255/0.2891e-9
R_load = 50
[Rising waveform]
R_fixture= 50
V_fixture= 1.27241
V_fixture_min= 1.23619
V_fixture_max= 1.31823
|Time   V(typ)   V(min)   V(max)
0s        1.094V     1.067V     1.135V
1.24ns    1.094V     1.067V     1.12V
1.29ns    1.094V     1.067V     1.155V
1.43ns    1.094V     1.067V     1.365V
1.54ns    1.092V     1.067V     1.424V
1.81ns    1.355V     1.065V     1.469V
1.96ns    1.409V     1.079V     1.479V
2.2ns     1.434V     1.283V     1.489V
2.41ns    1.442V     1.37V      1.495V
4ns       1.452V     1.407V     1.501V
[Falling waveform]
R_fixture= 50
V_fixture= 1.27241
V_fixture_min= 1.23619
V_fixture_max= 1.31823
|Time   V(typ)   V(min)   V(max)
0s        1.452V     1.408V     1.501V
1.2ns     1.452V     1.408V     1.51V
1.28ns    1.452V     1.408V     1.465V
1.47ns    1.458V     1.408V     1.252V
1.58ns    1.4V       1.408V     1.214V
1.74ns    1.222V     1.409V     1.181V
1.88ns    1.163V     1.404V     1.164V
2.19ns    1.119V     1.17V      1.146V
2.36ns    1.11V      1.113V     1.142V
4ns       1.094V     1.067V     1.135V
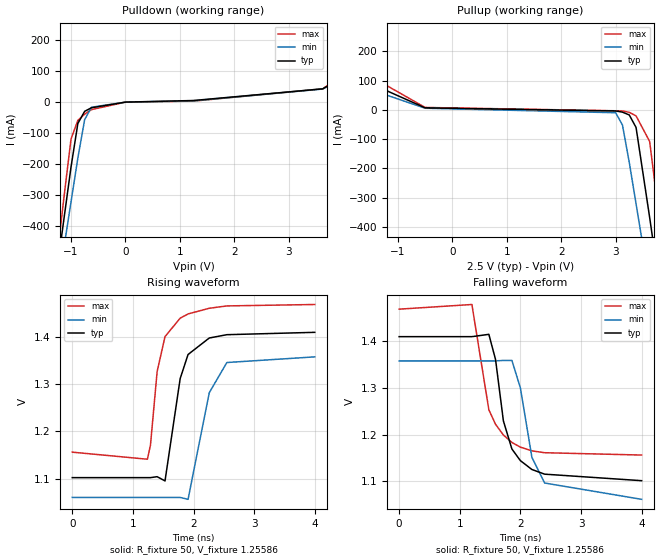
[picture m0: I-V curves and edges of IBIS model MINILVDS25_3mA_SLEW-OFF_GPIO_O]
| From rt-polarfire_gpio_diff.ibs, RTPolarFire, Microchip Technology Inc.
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|   Model MINILVDS25_3mA_SLEW-OFF_GPIO_O
[Model]   MINILVDS25_3mA_SLEW-OFF_GPIO_O
Model_type   Output
Polarity   Non-Inverting
Enable   Active-High
Vmeas =   1.2
Cref =   5p
Rref =   100
|   typ   min   max
C_comp_pullup   2.605e-12   2.605e-12   2.76e-12
C_comp_pulldown  2.605e-12   2.605e-12   2.76e-12
[Temperature Range]  25C   125C   -55C
[Voltage Range]  2.5   2.375   2.625
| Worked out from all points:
|   slope of the pulldown table from 0 to 0.375 V, typ, clamps not added: 135 ohm
|   slope of the pullup table from 0 to 0.375 V, typ, clamps not added: 158 ohm
|   rising waveform, R_fixture 50, V_fixture 1.25586: 20-80 % time 221ps typ, 261ps min, 224ps max; typ from 1.1 V to 1.41 V
|   falling waveform, R_fixture 50, V_fixture 1.25586: 20-80 % time 281ps typ, 269ps min, 292ps max; typ from 1.41 V to 1.1 V
[Pulldown]
|Voltage   I(typ)   I(min)   I(max)
-2.5V     -2.163A    -2.035A    -2.424A
-1.25V    -533.4mA   -606.8mA   -492.4mA
-1.125V   -371.6mA   -465mA     -300.9mA
-1V       -210.1mA   -323.1mA   -119.3mA
-875mV    -69.41mA   -181.4mA   -59.35mA
-750mV    -29.85mA   -56.83mA   -39.09mA
-625mV    -18.36mA   -16.57mA   -24.37mA
0V        -62.73uA   -53.8uA    -77.15uA
1.25V     5.161mA    4.037mA    3.201mA
3.625V    43.02mA    42.44mA    43.24mA
4.25V     109.1mA    96.23mA    119.3mA
5V        213mA      183.8mA    240.9mA
[Pullup]
|Voltage   I(typ)   I(min)   I(max)
-2.5V     228.9mA    182.4mA    281mA
-1.5V     89.55mA    68.71mA    114mA
-500mV    6.765mA    5.47mA     8.163mA
3V        -3.849mA   -9.862mA   -3.24mA
3.125V    -7.793mA   -51.81mA   -3.879mA
3.25V     -17.45mA   -179.1mA   -8.452mA
3.375V    -60.07mA   -320.6mA   -20.66mA
3.625V    -367.4mA   -603.8mA   -107.9mA
3.75V     -528.9mA   -745.3mA   -294.7mA
3.875V    -690.6mA   -887mA     -486mA
4V        -852.4mA   -1.029A    -677.3mA
5V        -2.157A    -2.174A    -2.22A
[Ramp]
| variable   typ   min   max
dV/dt_r 0.1902/0.2239e-9   0.1817/0.2632e-9   0.1976/0.2223e-9
dV/dt_f 0.1890/0.2802e-9   0.1806/0.2721e-9   0.1939/0.2893e-9
R_load = 50
[Rising waveform]
R_fixture= 50
V_fixture= 1.25586
V_fixture_min= 1.20819
V_fixture_max= 1.31287
|Time   V(typ)   V(min)   V(max)
0s        1.102V     1.06V      1.156V
1.24ns    1.102V     1.06V      1.141V
1.29ns    1.102V     1.06V      1.171V
1.4ns     1.104V     1.06V      1.327V
1.53ns    1.095V     1.06V      1.401V
1.78ns    1.312V     1.06V      1.44V
1.91ns    1.363V     1.056V     1.449V
2.26ns    1.398V     1.282V     1.461V
2.55ns    1.405V     1.346V     1.466V
4ns       1.41V      1.358V     1.469V
[Falling waveform]
R_fixture= 50
V_fixture= 1.25586
V_fixture_min= 1.20819
V_fixture_max= 1.31287
|Time   V(typ)   V(min)   V(max)
0s        1.41V      1.358V     1.469V
1.2ns     1.41V      1.358V     1.479V
1.48ns    1.415V     1.358V     1.253V
1.59ns    1.361V     1.358V     1.222V
1.72ns    1.229V     1.359V     1.199V
1.86ns    1.169V     1.359V     1.183V
2ns       1.144V     1.3V       1.173V
2.19ns    1.125V     1.151V     1.165V
2.4ns     1.115V     1.096V     1.161V
4ns       1.101V     1.061V     1.156V
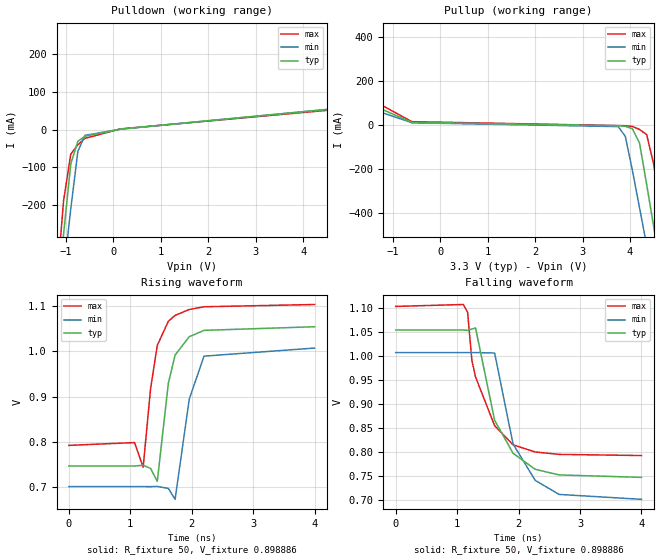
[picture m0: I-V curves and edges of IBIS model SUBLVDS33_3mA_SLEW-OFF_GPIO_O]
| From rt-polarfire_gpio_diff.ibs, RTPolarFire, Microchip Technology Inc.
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|   Model SUBLVDS33_3mA_SLEW-OFF_GPIO_O
[Model]   SUBLVDS33_3mA_SLEW-OFF_GPIO_O
Model_type   Output
Polarity   Non-Inverting
Enable   Active-High
Vmeas =   0.9
Cref =   5p
Rref =   100
|   typ   min   max
C_comp_pullup   2.605e-12   2.605e-12   2.76e-12
C_comp_pulldown  2.605e-12   2.605e-12   2.76e-12
[Temperature Range]  25C   125C   -55C
[Voltage Range]  3.3   3.15   3.45
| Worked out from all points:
|   slope of the pulldown table from 0 to 0.495 V, typ, clamps not added: 171 ohm
|   slope of the pullup table from 0 to 0.495 V, typ, clamps not added: 176 ohm
|   rising waveform, R_fixture 50, V_fixture 0.898886: 20-80 % time 213ps typ, 206ps min, 213ps max; typ from 0.747 V to 1.05 V
|   falling waveform, R_fixture 50, V_fixture 0.898886: 20-80 % time 418ps typ, 411ps min, 405ps max; typ from 1.05 V to 0.747 V
[Pulldown]
|Voltage   I(typ)   I(min)   I(max)
-3.3V     -3.224A    -2.962A    -3.688A
-1.2V     -469mA     -550.4mA   -416.1mA
-1.05V    -275mA     -380.2mA   -186.6mA
-900mV    -90.53mA   -210.1mA   -65.04mA
-750mV    -30.57mA   -57.34mA   -39.87mA
-600mV    -17.3mA    -14.85mA   -22.89mA
150mV     1.814mA    1.475mA    2.206mA
4.5V      53.8mA     53.75mA    51.33mA
5.1V      117.8mA    106.8mA    124.8mA
6V        247.4mA    218.6mA    274.9mA
6.15V     271.9mA    239.9mA    302.3mA
6.6V      351.1mA    306.5mA    389.3mA
[Pullup]
|Voltage   I(typ)   I(min)   I(max)
-3.3V     376.6mA    307.7mA    446.4mA
-1.65V    110.7mA    87.05mA    138.5mA
-600mV    11.45mA    9.774mA    14.93mA
3.75V     -3.373mA   -7.762mA   -3.204mA
3.9V      -6.563mA   -51.77mA   -3.393mA
4.05V     -17.37mA   -207.3mA   -6.939mA
4.2V      -82.62mA   -377.2mA   -20.57mA
4.35V     -270.5mA   -547.2mA   -44.24mA
4.5V      -464.2mA   -717mA     -179.9mA
4.65V     -658.2mA   -887mA     -409.3mA
4.8V      -852.3mA   -1.057A    -638.8mA
6.6V      -3.216A    -3.129A    -3.441A
[Ramp]
| variable   typ   min   max
dV/dt_r 0.2069/0.2152e-9   0.2003/0.2147e-9   0.2159/0.2091e-9
dV/dt_f 0.1869/0.4150e-9   0.1867/0.4100e-9   0.1891/0.4033e-9
R_load = 50
[Rising waveform]
R_fixture= 50
V_fixture= 0.898886
V_fixture_min= 0.853055
V_fixture_max= 0.946985
|Time   V(typ)   V(min)   V(max)
0s        747.2mV    701.7mV    792.5mV
1.07ns    747.1mV    701.7mV    798.7mV
1.21ns    748.6mV    701.7mV    744.2mV
1.33ns    741.7mV    701.6mV    916.7mV
1.44ns    713.3mV    702mV      1.013V
1.62ns    929.6mV    697.7mV    1.066V
1.73ns    991.7mV    673.6mV    1.079V
1.96ns    1.032V     894.2mV    1.092V
2.2ns     1.046V     989.2mV    1.098V
4ns       1.054V     1.007V     1.103V
[Falling waveform]
R_fixture= 50
V_fixture= 0.898886
V_fixture_min= 0.853055
V_fixture_max= 0.946985
|Time   V(typ)   V(min)   V(max)
0s        1.054V     1.007V     1.103V
1.1ns     1.054V     1.007V     1.107V
1.17ns    1.053V     1.007V     1.091V
1.24ns    1.056V     1.007V     990.6mV
1.3ns     1.058V     1.007V     956mV
1.61ns    866.1mV    1.006V     855mV
1.91ns    797.5mV    816.8mV    815mV
2.27ns    764.1mV    741.1mV    800.2mV
2.66ns    752.4mV    711.8mV    795.1mV
4ns       747.3mV    701.6mV    792.7mV
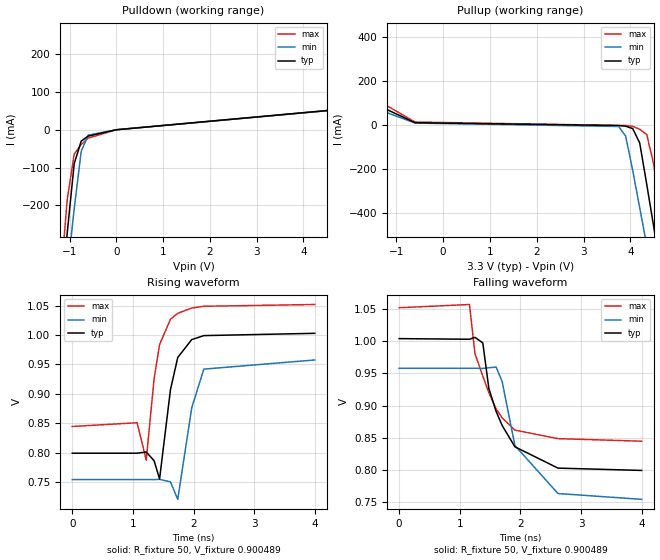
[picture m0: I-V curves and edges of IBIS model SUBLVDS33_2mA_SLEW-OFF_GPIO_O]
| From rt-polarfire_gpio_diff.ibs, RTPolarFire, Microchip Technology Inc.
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|   Model SUBLVDS33_2mA_SLEW-OFF_GPIO_O
[Model]   SUBLVDS33_2mA_SLEW-OFF_GPIO_O
Model_type   Output
Polarity   Non-Inverting
Enable   Active-High
Vmeas =   0.9
Cref =   5p
Rref =   100
|   typ   min   max
C_comp_pullup   2.605e-12   2.605e-12   2.76e-12
C_comp_pulldown  2.605e-12   2.605e-12   2.76e-12
[Temperature Range]  25C   125C   -55C
[Voltage Range]  3.3   3.15   3.45
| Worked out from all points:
|   slope of the pulldown table from 0 to 0.495 V, typ, clamps not added: 259 ohm
|   slope of the pullup table from 0 to 0.495 V, typ, clamps not added: 256 ohm
|   rising waveform, R_fixture 50, V_fixture 0.900489: 20-80 % time 201ps typ, 213ps min, 217ps max; typ from 0.799 V to 1 V
|   falling waveform, R_fixture 50, V_fixture 0.900489: 20-80 % time 442ps typ, 446ps min, 437ps max; typ from 1 V to 0.799 V
[Pulldown]
|Voltage   I(typ)   I(min)   I(max)
-3.3V     -3.224A    -2.962A    -3.688A
-1.2V     -468.8mA   -550.2mA   -415.9mA
-1.05V    -274.8mA   -380mA     -186.2mA
-900mV    -90.12mA   -209.8mA   -64.26mA
-750mV    -30mA      -57mA      -39.12mA
-600mV    -16.77mA   -14.44mA   -22.18mA
0V        -45.85uA   -39.7uA    -56.12uA
4.5V      50.74mA    50.67mA    50.27mA
5.1V      116.7mA    105.8mA    123.7mA
6V        246.3mA    217.4mA    273.7mA
6.15V     270.7mA    238.6mA    301.1mA
6.6V      349.8mA    305.2mA    387.9mA
[Pullup]
|Voltage   I(typ)   I(min)   I(max)
-3.3V     376.3mA    307.5mA    446mA
-1.8V     129.6mA    102.7mA    161.1mA
-600mV    10.25mA    8.868mA    13.39mA
3.75V     -2.338mA   -6.748mA   -2.155mA
3.9V      -5.54mA    -50.83mA   -2.346mA
4.05V     -16.37mA   -206.4mA   -5.905mA
4.2V      -81.72mA   -376.3mA   -19.55mA
4.35V     -269.6mA   -546.3mA   -43.22mA
4.5V      -463.3mA   -716.1mA   -179mA
4.65V     -657.3mA   -886.1mA   -408.5mA
4.8V      -851.4mA   -1.056A    -637.9mA
6.6V      -3.215A    -3.128A    -3.44A
[Ramp]
| variable   typ   min   max
dV/dt_r 0.1497/0.4588e-9   0.1433/0.2234e-9   0.1600/0.2133e-9
dV/dt_f 0.1254/0.4377e-9   0.1251/0.4455e-9   0.1276/0.4354e-9
R_load = 50
[Rising waveform]
R_fixture= 50
V_fixture= 0.900489
V_fixture_min= 0.855159
V_fixture_max= 0.948409
|Time   V(typ)   V(min)   V(max)
0s        799.1mV    754.3mV    844.6mV
1.07ns    799.1mV    754.3mV    850.9mV
1.22ns    801.3mV    754.3mV    787.3mV
1.35ns    786.3mV    754.2mV    925.8mV
1.44ns    755.2mV    754.7mV    983.8mV
1.62ns    907.3mV    750.4mV    1.027V
1.74ns    961.9mV    720.7mV    1.037V
1.97ns    992.3mV    876mV      1.046V
2.17ns    999.1mV    942.1mV    1.049V
4ns       1.003V     957.7mV    1.052V
[Falling waveform]
R_fixture= 50
V_fixture= 0.900489
V_fixture_min= 0.855159
V_fixture_max= 0.948409
|Time   V(typ)   V(min)   V(max)
0s        1.004V     957.9mV    1.052V
1.16ns    1.003V     957.9mV    1.057V
1.25ns    1.006V     957.9mV    980.7mV
1.38ns    997.3mV    957.7mV    945.8mV
1.48ns    926.5mV    958.7mV    919.8mV
1.6ns     890.8mV    959.8mV    894.6mV
1.7ns     868.9mV    937.1mV    880.8mV
1.91ns    835.9mV    837.9mV    861.8mV
2.62ns    802.8mV    763.3mV    848.6mV
4ns       799.2mV    754.3mV    844.6mV
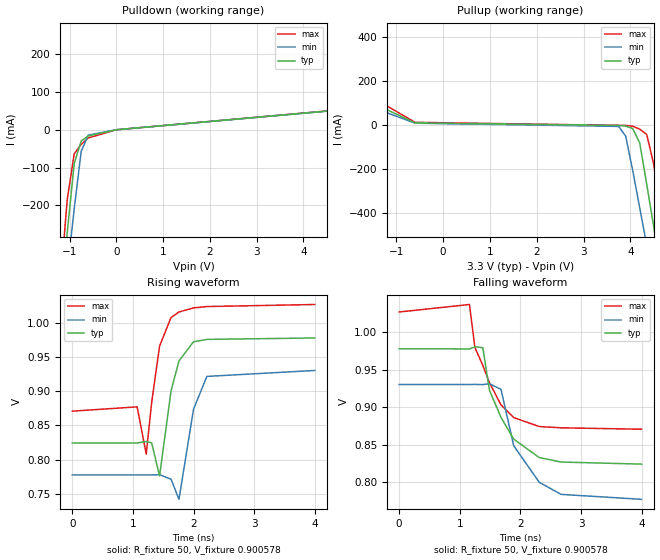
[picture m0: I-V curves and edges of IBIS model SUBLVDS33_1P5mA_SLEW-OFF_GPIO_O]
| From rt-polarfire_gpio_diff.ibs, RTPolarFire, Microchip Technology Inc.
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|   Model SUBLVDS33_1P5mA_SLEW-OFF_GPIO_O
[Model]   SUBLVDS33_1P5mA_SLEW-OFF_GPIO_O
Model_type   Output
Polarity   Non-Inverting
Enable   Active-High
Vmeas =   0.9
Cref =   5p
Rref =   100
|   typ   min   max
C_comp_pullup   2.605e-12   2.605e-12   2.76e-12
C_comp_pulldown  2.605e-12   2.605e-12   2.76e-12
[Temperature Range]  25C   125C   -55C
[Voltage Range]  3.3   3.15   3.45
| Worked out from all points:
|   slope of the pulldown table from 0 to 0.495 V, typ, clamps not added: 347 ohm
|   slope of the pullup table from 0 to 0.495 V, typ, clamps not added: 335 ohm
|   rising waveform, R_fixture 50, V_fixture 0.900578: 20-80 % time 213ps typ, 208ps min, 228ps max; typ from 0.824 V to 0.978 V
|   falling waveform, R_fixture 50, V_fixture 0.900578: 20-80 % time 470ps typ, 476ps min, 466ps max; typ from 0.978 V to 0.824 V
[Pulldown]
|Voltage   I(typ)   I(min)   I(max)
-3.3V     -3.224A    -2.962A    -3.688A
-1.2V     -468.6mA   -550.1mA   -415.7mA
-1.05V    -274.7mA   -379.8mA   -186mA
-900mV    -89.88mA   -209.7mA   -63.79mA
-750mV    -29.67mA   -56.8mA    -38.67mA
-600mV    -16.47mA   -14.21mA   -21.76mA
0V        -44.72uA   -38.59uA   -54.8uA
4.5V      49.21mA    49.14mA    49.72mA
5.1V      116.2mA    105.2mA    123.2mA
6V        245.7mA    216.8mA    273.1mA
6.15V     270mA      238mA      300.4mA
6.6V      349.1mA    304.5mA    387.2mA
[Pullup]
|Voltage   I(typ)   I(min)   I(max)
-3.3V     376.2mA    307.5mA    445.8mA
-1.8V     129.2mA    102.6mA    160.4mA
-600mV    9.446mA    8.295mA    12.34mA
3.75V     -1.827mA   -6.246mA   -1.639mA
3.9V      -5.035mA   -50.36mA   -1.83mA
4.05V     -15.87mA   -206mA     -5.396mA
4.2V      -81.27mA   -375.9mA   -19.05mA
4.35V     -269.2mA   -545.8mA   -42.72mA
4.5V      -462.9mA   -715.7mA   -178.6mA
4.65V     -656.9mA   -885.7mA   -408mA
4.8V      -851mA     -1.056A    -637.5mA
6.6V      -3.215A    -3.128A    -3.44A
[Ramp]
| variable   typ   min   max
dV/dt_r 0.1218/0.2205e-9   0.1153/0.5920e-9   0.1317/0.2118e-9
dV/dt_f 94.9196e-3/0.4670e-9   94.4457e-3/0.4734e-9   99.9939e-3/0.4585e-9
R_load = 50
[Rising waveform]
R_fixture= 50
V_fixture= 0.900578
V_fixture_min= 0.853258
V_fixture_max= 0.948392
|Time   V(typ)   V(min)   V(max)
0s        824.2mV    777.4mV    870.8mV
1.07ns    824.2mV    777.4mV    877.1mV
1.22ns    826.4mV    777.4mV    808mV
1.31ns    824.3mV    777.4mV    883.8mV
1.44ns    775.9mV    777.8mV    966mV
1.63ns    900.7mV    771.2mV    1.008V
1.76ns    944.3mV    741.7mV    1.016V
2ns       972.4mV    873.5mV    1.022V
2.22ns    975.9mV    921.7mV    1.024V
4ns       978mV      930.4mV    1.027V
[Falling waveform]
R_fixture= 50
V_fixture= 0.900578
V_fixture_min= 0.853258
V_fixture_max= 0.948392
|Time   V(typ)   V(min)   V(max)
0s        978mV      930.4mV    1.027V
1.16ns    977.8mV    930.4mV    1.037V
1.25ns    980.6mV    930.5mV    979.6mV
1.38ns    979.5mV    930.3mV    955.9mV
1.49ns    922.6mV    931.4mV    932.8mV
1.68ns    886.6mV    924mV      903.2mV
1.89ns    857.6mV    848.8mV    886.3mV
2.31ns    833.1mV    800.2mV    874.4mV
2.67ns    827.1mV    784mV      872.7mV
4ns       824.3mV    777.4mV    870.8mV
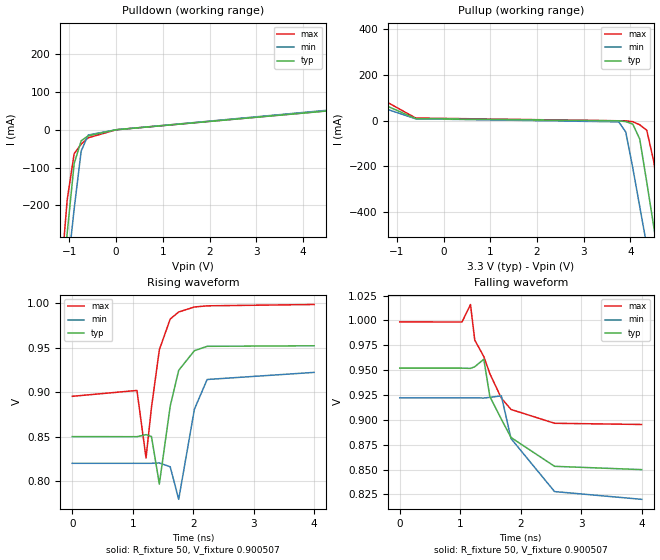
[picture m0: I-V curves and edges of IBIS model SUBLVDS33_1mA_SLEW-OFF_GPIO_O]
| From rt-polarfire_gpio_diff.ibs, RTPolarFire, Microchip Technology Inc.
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|   Model SUBLVDS33_1mA_SLEW-OFF_GPIO_O
[Model]   SUBLVDS33_1mA_SLEW-OFF_GPIO_O
Model_type   Output
Polarity   Non-Inverting
Enable   Active-High
Vmeas =   0.9
Cref =   5p
Rref =   100
|   typ   min   max
C_comp_pullup   2.605e-12   2.605e-12   2.76e-12
C_comp_pulldown  2.605e-12   2.605e-12   2.76e-12
[Temperature Range]  25C   125C   -55C
[Voltage Range]  3.3   3.15   3.45
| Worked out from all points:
|   slope of the pulldown table from 0 to 0.495 V, typ, clamps not added: 533 ohm
|   slope of the pullup table from 0 to 0.495 V, typ, clamps not added: 495 ohm
|   rising waveform, R_fixture 50, V_fixture 0.900507: 20-80 % time 226ps typ, 216ps min, 227ps max; typ from 0.85 V to 0.952 V
|   falling waveform, R_fixture 50, V_fixture 0.900507: 20-80 % time 519ps typ, 531ps min, 506ps max; typ from 0.952 V to 0.85 V
[Pulldown]
|Voltage   I(typ)   I(min)   I(max)
-3.3V     -3.223A    -2.962A    -3.688A
-1.2V     -468.5mA   -549.9mA   -415.5mA
-1.05V    -274.5mA   -379.7mA   -185.8mA
-900mV    -89.6mA    -209.6mA   -63.26mA
-750mV    -29.27mA   -56.56mA   -38.14mA
-600mV    -16.09mA   -13.91mA   -21.27mA
0V        -43.57uA   -38.27uA   -53.36uA
4.5V      49.42mA    51.32mA    49.86mA
5.1V      107.6mA    93.31mA    116.9mA
6.15V     242.5mA    202mA      278.2mA
6.3V      263.8mA    218.8mA    302.7mA
6.6V      307.6mA    252.5mA    353mA
[Pullup]
|Voltage   I(typ)   I(min)   I(max)
-3.3V     335.5mA    261.9mA    407.7mA
-1.65V    102.3mA    79.1mA     129.9mA
-600mV    8.394mA    7.543mA    10.94mA
3.75V     -1.307mA   -5.739mA   -1.111mA
3.9V      -4.521mA   -49.89mA   -1.303mA
4.05V     -15.36mA   -205.5mA   -4.876mA
4.2V      -80.82mA   -375.4mA   -18.54mA
4.35V     -268.7mA   -545.4mA   -42.21mA
4.5V      -462.5mA   -715.2mA   -178.1mA
4.65V     -656.4mA   -885.2mA   -407.6mA
4.8V      -850.6mA   -1.056A    -637mA
6.6V      -3.214A    -3.127A    -3.439A
[Ramp]
| variable   typ   min   max
dV/dt_r 93.3555e-3/0.2232e-9   87.1165e-3/0.2413e-9   0.1036/0.2219e-9
dV/dt_f 67.0868e-3/0.5121e-9   63.5041e-3/0.5237e-9   72.7160e-3/0.4878e-9
R_load = 50
[Rising waveform]
R_fixture= 50
V_fixture= 0.900507
V_fixture_min= 0.870719
V_fixture_max= 0.946468
|Time   V(typ)   V(min)   V(max)
0s        849.9mV    819.9mV    895.2mV
1.07ns    849.8mV    819.9mV    901.8mV
1.22ns    852.1mV    819.9mV    825.9mV
1.31ns    850mV      819.9mV    882.6mV
1.44ns    796.6mV    820.3mV    947.5mV
1.62ns    884.2mV    816mV      982.1mV
1.76ns    924.4mV    779.4mV    990mV
2.02ns    946.5mV    880.7mV    995.6mV
2.23ns    951.4mV    914.1mV    996.9mV
4ns       952mV      922.1mV    998.4mV
[Falling waveform]
R_fixture= 50
V_fixture= 0.900507
V_fixture_min= 0.870719
V_fixture_max= 0.946468
|Time   V(typ)   V(min)   V(max)
0s        952mV      922.1mV    998.5mV
1.03ns    952mV      922.1mV    998.4mV
1.17ns    951.7mV    922.1mV    1.016V
1.24ns    953.4mV    922.1mV    980.2mV
1.39ns    960.9mV    921.9mV    963.6mV
1.49ns    923.4mV    922.6mV    946.4mV
1.68ns    900.6mV    924.1mV    921.8mV
1.84ns    882.2mV    881.1mV    910.4mV
2.56ns    853.2mV    827.8mV    896.5mV
4ns       849.9mV    820mV      895.3mV
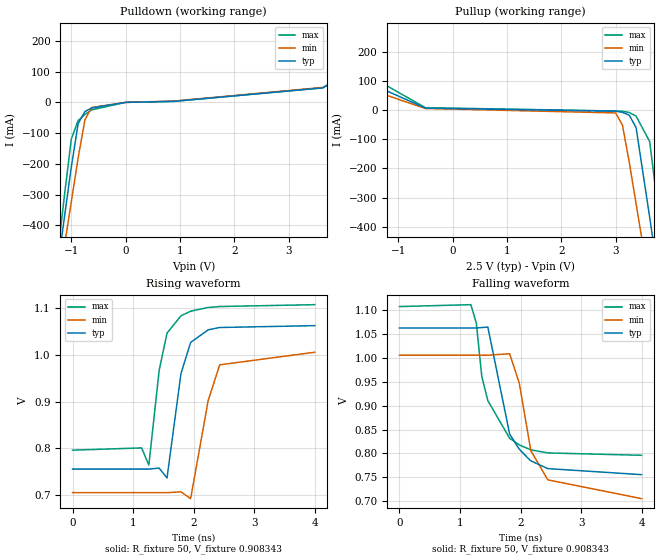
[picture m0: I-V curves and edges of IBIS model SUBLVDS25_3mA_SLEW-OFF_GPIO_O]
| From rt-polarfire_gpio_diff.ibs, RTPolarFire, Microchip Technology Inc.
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|   Model SUBLVDS25_3mA_SLEW-OFF_GPIO_O
[Model]   SUBLVDS25_3mA_SLEW-OFF_GPIO_O
Model_type   Output
Polarity   Non-Inverting
Enable   Active-High
Vmeas =   0.9
Cref =   5p
Rref =   100
|   typ   min   max
C_comp_pullup   2.605e-12   2.605e-12   2.76e-12
C_comp_pulldown  2.605e-12   2.605e-12   2.76e-12
[Temperature Range]  25C   125C   -55C
[Voltage Range]  2.5   2.375   2.625
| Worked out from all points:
|   slope of the pulldown table from 0 to 0.375 V, typ, clamps not added: 133 ohm
|   slope of the pullup table from 0 to 0.375 V, typ, clamps not added: 158 ohm
|   rising waveform, R_fixture 50, V_fixture 0.908343: 20-80 % time 207ps typ, 247ps min, 209ps max; typ from 0.755 V to 1.06 V
|   falling waveform, R_fixture 50, V_fixture 0.908343: 20-80 % time 339ps typ, 331ps min, 357ps max; typ from 1.06 V to 0.755 V
[Pulldown]
|Voltage   I(typ)   I(min)   I(max)
-2.5V     -2.163A    -2.035A    -2.424A
-1.25V    -533.4mA   -606.8mA   -492.4mA
-1.125V   -371.6mA   -465mA     -300.9mA
-1V       -210.1mA   -323.1mA   -119.3mA
-875mV    -69.39mA   -181.4mA   -59.32mA
-750mV    -29.84mA   -56.83mA   -39.07mA
-625mV    -18.35mA   -16.58mA   -24.36mA
0V        -47.8uA    -40.61uA   -58.53uA
875mV     3.145mA    4.065mA    3.178mA
3.625V    47.11mA    48.59mA    47.33mA
4.25V     109.2mA    96.4mA     119.5mA
5V        213.1mA    184mA      241.1mA
[Pullup]
|Voltage   I(typ)   I(min)   I(max)
-2.5V     229mA      182.5mA    281.2mA
-1.5V     89.57mA    68.73mA    114mA
-500mV    6.781mA    5.482mA    8.183mA
3V        -3.823mA   -9.81mA    -3.22mA
3.125V    -7.744mA   -51.76mA   -3.851mA
3.25V     -17.37mA   -179mA     -8.397mA
3.375V    -59.99mA   -320.5mA   -20.56mA
3.625V    -367.3mA   -603.8mA   -107.8mA
3.75V     -528.8mA   -745.3mA   -294.6mA
3.875V    -690.5mA   -887mA     -485.9mA
4V        -852.3mA   -1.029A    -677mA
5V        -2.157A    -2.174A    -2.22A
[Ramp]
| variable   typ   min   max
dV/dt_r 0.1965/0.2126e-9   0.1895/0.2539e-9   0.2066/0.2117e-9
dV/dt_f 0.1873/0.3380e-9   0.1836/0.3334e-9   0.1900/0.3550e-9
R_load = 50
[Rising waveform]
R_fixture= 50
V_fixture= 0.908343
V_fixture_min= 0.852650
V_fixture_max= 0.951521
|Time   V(typ)   V(min)   V(max)
0s        755.3mV    704.8mV    795.9mV
1.14ns    755.3mV    704.8mV    800.7mV
1.26ns    755.3mV    704.8mV    764mV
1.43ns    757.4mV    704.8mV    967mV
1.56ns    736.2mV    704.7mV    1.047V
1.79ns    959.9mV    706.5mV    1.084V
1.95ns    1.027V     691.8mV    1.094V
2.24ns    1.054V     902.5mV    1.102V
2.43ns    1.059V     978.9mV    1.104V
4ns       1.063V     1.006V     1.108V
[Falling waveform]
R_fixture= 50
V_fixture= 0.908343
V_fixture_min= 0.852650
V_fixture_max= 0.951521
|Time   V(typ)   V(min)   V(max)
0s        1.063V     1.006V     1.108V
1.18ns    1.063V     1.006V     1.112V
1.27ns    1.063V     1.006V     1.073V
1.36ns    1.064V     1.006V     961.4mV
1.46ns    1.065V     1.006V     910.7mV
1.82ns    840.6mV    1.009V     831.7mV
1.98ns    808.6mV    946.9mV    817.7mV
2.17ns    784.3mV    805.8mV    807.4mV
2.45ns    768.1mV    744.6mV    801mV
4ns       755.4mV    705mV      796mV
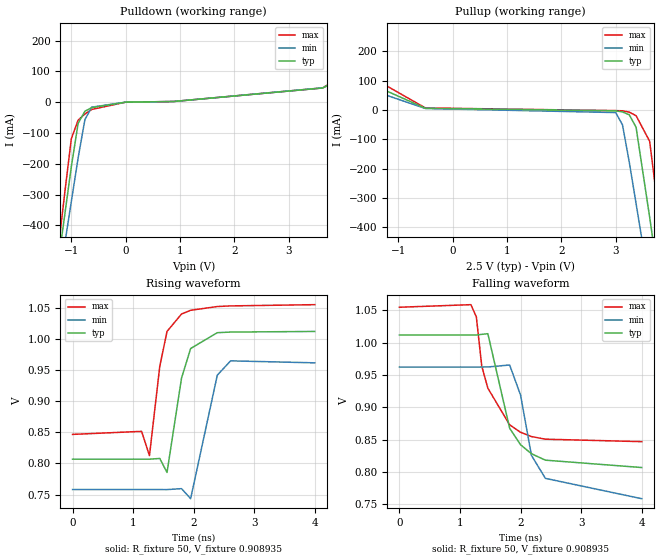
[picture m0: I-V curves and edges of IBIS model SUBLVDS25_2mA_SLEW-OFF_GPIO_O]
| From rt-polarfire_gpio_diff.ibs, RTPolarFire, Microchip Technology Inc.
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|   Model SUBLVDS25_2mA_SLEW-OFF_GPIO_O
[Model]   SUBLVDS25_2mA_SLEW-OFF_GPIO_O
Model_type   Output
Polarity   Non-Inverting
Enable   Active-High
Vmeas =   0.9
Cref =   5p
Rref =   100
|   typ   min   max
C_comp_pullup   2.605e-12   2.605e-12   2.76e-12
C_comp_pulldown  2.605e-12   2.605e-12   2.76e-12
[Temperature Range]  25C   125C   -55C
[Voltage Range]  2.5   2.375   2.625
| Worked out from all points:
|   slope of the pulldown table from 0 to 0.375 V, typ, clamps not added: 201 ohm
|   slope of the pullup table from 0 to 0.375 V, typ, clamps not added: 218 ohm
|   rising waveform, R_fixture 50, V_fixture 0.908935: 20-80 % time 210ps typ, 228ps min, 201ps max; typ from 0.807 V to 1.01 V
|   falling waveform, R_fixture 50, V_fixture 0.908935: 20-80 % time 356ps typ, 335ps min, 376ps max; typ from 1.01 V to 0.807 V
[Pulldown]
|Voltage   I(typ)   I(min)   I(max)
-2.5V     -2.163A    -2.035A    -2.424A
-1.25V    -533.1mA   -606.6mA   -492.1mA
-1.125V   -371.4mA   -464.8mA   -300.6mA
-1V       -209.9mA   -322.9mA   -118.8mA
-875mV    -68.95mA   -181.3mA   -58.58mA
-750mV    -29.31mA   -56.54mA   -38.36mA
-625mV    -17.86mA   -16.23mA   -23.68mA
0V        -45.59uA   -38.93uA   -55.81uA
875mV     2.083mA    2.08mA     2.088mA
3.625V    46.06mA    46.6mA     46.25mA
4.25V     108.1mA    95.39mA    118.4mA
5V        211.9mA    182.8mA    239.9mA
[Pullup]
|Voltage   I(typ)   I(min)   I(max)
-2.5V     228.7mA    182.3mA    279.9mA
-1.5V     88.51mA    68.26mA    112.6mA
-500mV    5.869mA    5.067mA    7.002mA
3V        -2.791mA   -8.809mA   -2.172mA
3.125V    -6.724mA   -50.83mA   -2.807mA
3.25V     -16.36mA   -178.1mA   -7.366mA
3.375V    -59.06mA   -319.6mA   -19.55mA
3.625V    -366.4mA   -602.9mA   -106.9mA
3.75V     -528mA     -744.4mA   -293.7mA
3.875V    -689.6mA   -886.1mA   -485mA
4V        -851.4mA   -1.028A    -676.2mA
5V        -2.156A    -2.174A    -2.219A
[Ramp]
| variable   typ   min   max
dV/dt_r 0.1363/0.2198e-9   0.1336/0.2471e-9   0.1454/0.2060e-9
dV/dt_f 0.1258/0.3544e-9   0.1249/0.3373e-9   0.1276/0.3736e-9
R_load = 50
[Rising waveform]
R_fixture= 50
V_fixture= 0.908935
V_fixture_min= 0.859516
V_fixture_max= 0.950603
|Time   V(typ)   V(min)   V(max)
0s        806.9mV    758.2mV    846.7mV
1.14ns    806.9mV    758.2mV    851.6mV
1.27ns    806.9mV    758.2mV    812.6mV
1.44ns    808.1mV    758.2mV    955.7mV
1.56ns    785.6mV    758.1mV    1.012V
1.8ns     937.2mV    759.6mV    1.04V
1.95ns    984.6mV    743.5mV    1.046V
2.39ns    1.01V      941.7mV    1.052V
2.61ns    1.011V     964.8mV    1.053V
4ns       1.012V     961.6mV    1.055V
[Falling waveform]
R_fixture= 50
V_fixture= 0.908935
V_fixture_min= 0.859516
V_fixture_max= 0.950603
|Time   V(typ)   V(min)   V(max)
0s        1.012V     962.3mV    1.055V
1.18ns    1.012V     962.3mV    1.059V
1.27ns    1.012V     962.3mV    1.04V
1.36ns    1.013V     962.4mV    963.6mV
1.46ns    1.014V     962.4mV    929.6mV
1.82ns    867.5mV    965.5mV    872.8mV
2ns       841.9mV    919mV      861.2mV
2.18ns    828mV      825.5mV    854.6mV
2.41ns    818mV      789.8mV    850.5mV
4ns       806.6mV    758.3mV    846.7mV
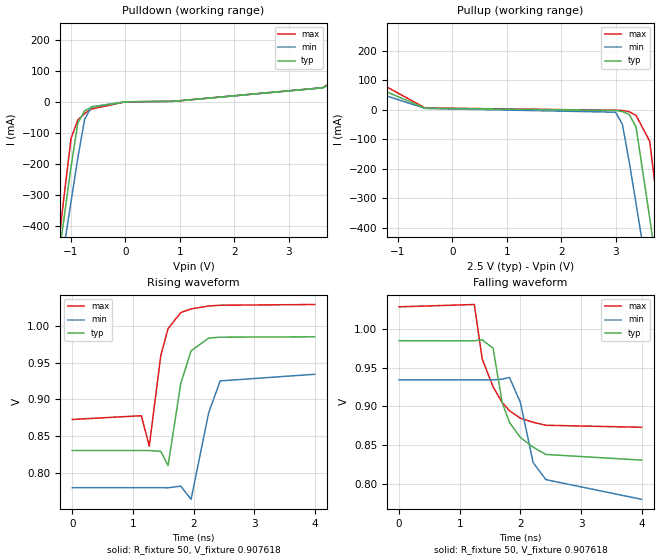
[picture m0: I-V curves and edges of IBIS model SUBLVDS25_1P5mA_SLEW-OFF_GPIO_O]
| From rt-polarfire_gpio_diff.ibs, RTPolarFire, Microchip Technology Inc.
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|   Model SUBLVDS25_1P5mA_SLEW-OFF_GPIO_O
[Model]   SUBLVDS25_1P5mA_SLEW-OFF_GPIO_O
Model_type   Output
Polarity   Non-Inverting
Enable   Active-High
Vmeas =   0.9
Cref =   5p
Rref =   100
|   typ   min   max
C_comp_pullup   2.605e-12   2.605e-12   2.76e-12
C_comp_pulldown  2.605e-12   2.605e-12   2.76e-12
[Temperature Range]  25C   125C   -55C
[Voltage Range]  2.5   2.375   2.625
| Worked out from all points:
|   slope of the pulldown table from 0 to 0.375 V, typ, clamps not added: 270 ohm
|   slope of the pullup table from 0 to 0.375 V, typ, clamps not added: 279 ohm
|   rising waveform, R_fixture 50, V_fixture 0.907618: 20-80 % time 202ps typ, 215ps min, 211ps max; typ from 0.831 V to 0.985 V
|   falling waveform, R_fixture 50, V_fixture 0.907618: 20-80 % time 375ps typ, 350ps min, 399ps max; typ from 0.985 V to 0.831 V
[Pulldown]
|Voltage   I(typ)   I(min)   I(max)
-2.5V     -2.163A    -2.035A    -2.424A
-1.25V    -533mA     -606.5mA   -491.9mA
-1.125V   -371.3mA   -464.7mA   -300.4mA
-1V       -209.8mA   -322.8mA   -118.4mA
-875mV    -68.69mA   -181.1mA   -58.15mA
-750mV    -29.01mA   -56.37mA   -37.94mA
-625mV    -17.57mA   -16.01mA   -23.28mA
0V        -44.43uA   -37.85uA   -54.52uA
875mV     1.558mA    1.572mA    1.553mA
3.625V    45.53mA    45.09mA    45.71mA
4.25V     107.6mA    94.86mA    117.9mA
5V        211.3mA    182.3mA    239.2mA
[Pullup]
|Voltage   I(typ)   I(min)   I(max)
-2.5V     228.6mA    182.3mA    279.4mA
-1.375V   74.04mA    56.89mA    94.9mA
-500mV    5.241mA    4.621mA    6.188mA
3V        -2.282mA   -8.309mA   -1.655mA
3.125V    -6.22mA    -50.36mA   -2.293mA
3.25V     -15.87mA   -177.7mA   -6.859mA
3.375V    -58.6mA    -319.2mA   -19.05mA
3.625V    -366mA     -602.4mA   -106.5mA
3.75V     -527.5mA   -744mA     -293.3mA
3.875V    -689.2mA   -885.7mA   -484.5mA
4V        -851mA     -1.028A    -675.7mA
5V        -2.155A    -2.173A    -2.218A
[Ramp]
| variable   typ   min   max
dV/dt_r 0.1068/0.2069e-9   0.1045/0.2383e-9   0.1156/0.4618e-9
dV/dt_f 95.3703e-3/0.3728e-9   95.1117e-3/0.3501e-9   96.6584e-3/0.3930e-9
R_load = 50
[Rising waveform]
R_fixture= 50
V_fixture= 0.907618
V_fixture_min= 0.856988
V_fixture_max= 0.950984
|Time   V(typ)   V(min)   V(max)
0s        830.6mV    780.1mV    872.8mV
1.14ns    830.6mV    780.1mV    877.9mV
1.27ns    830.6mV    780.1mV    836.5mV
1.46ns    829.5mV    780.1mV    959.5mV
1.58ns    810.1mV    780mV      996.3mV
1.79ns    921.8mV    782.2mV    1.018V
1.96ns    966mV      764.3mV    1.023V
2.25ns    983.4mV    881.9mV    1.027V
2.44ns    984.6mV    925.2mV    1.028V
4ns       985.1mV    934.2mV    1.029V
[Falling waveform]
R_fixture= 50
V_fixture= 0.907618
V_fixture_min= 0.856988
V_fixture_max= 0.950984
|Time   V(typ)   V(min)   V(max)
0s        985.1mV    934.4mV    1.029V
1.24ns    985mV      934.4mV    1.032V
1.37ns    986.3mV    934.4mV    961.5mV
1.55ns    975.3mV    934.3mV    925.3mV
1.7ns     905mV      935.4mV    905.1mV
1.82ns    879.3mV    937.5mV    894.4mV
2ns       859.8mV    905.2mV    884.7mV
2.21ns    847.2mV    827.3mV    879.5mV
2.42ns    837.8mV    805.2mV    875.6mV
4ns       830.5mV    779.7mV    873mV
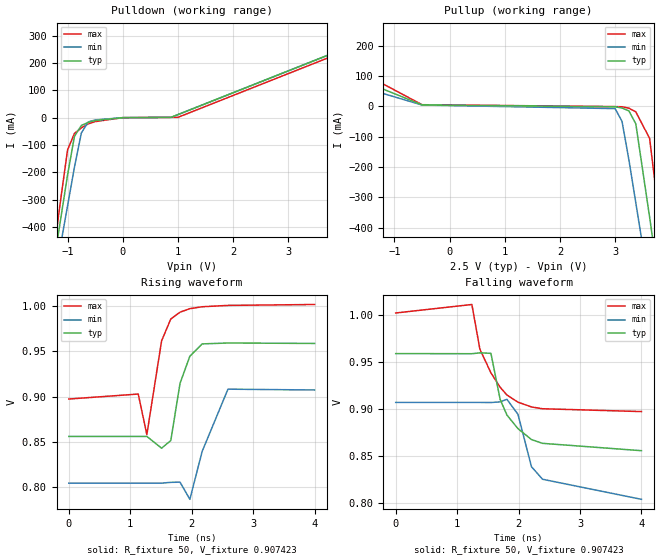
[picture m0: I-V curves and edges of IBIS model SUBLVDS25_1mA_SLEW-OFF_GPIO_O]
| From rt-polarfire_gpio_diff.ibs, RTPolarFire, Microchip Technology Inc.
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|   Model SUBLVDS25_1mA_SLEW-OFF_GPIO_O
[Model]   SUBLVDS25_1mA_SLEW-OFF_GPIO_O
Model_type   Output
Polarity   Non-Inverting
Enable   Active-High
Vmeas =   0.9
Cref =   5p
Rref =   100
|   typ   min   max
C_comp_pullup   2.605e-12   2.605e-12   2.76e-12
C_comp_pulldown  2.605e-12   2.605e-12   2.76e-12
[Temperature Range]  25C   125C   -55C
[Voltage Range]  2.5   2.375   2.625
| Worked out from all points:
|   slope of the pulldown table from 0 to 0.375 V, typ, clamps not added: 414 ohm
|   slope of the pullup table from 0 to 0.375 V, typ, clamps not added: 404 ohm
|   rising waveform, R_fixture 50, V_fixture 0.907423: 20-80 % time 200ps typ, 222ps min, 214ps max; typ from 0.856 V to 0.959 V
|   falling waveform, R_fixture 50, V_fixture 0.907423: 20-80 % time 420ps typ, 382ps min, 435ps max; typ from 0.959 V to 0.856 V
[Pulldown]
|Voltage   I(typ)   I(min)   I(max)
-2.5V     -2.163A    -2.035A    -2.424A
-1.25V    -532.9mA   -606.3mA   -491.8mA
-1.125V   -371.1mA   -464.5mA   -300.2mA
-1V       -209.6mA   -322.7mA   -118.1mA
-875mV    -68.38mA   -181mA     -57.65mA
-750mV    -28.63mA   -56.14mA   -37.45mA
-625mV    -17.22mA   -15.74mA   -22.82mA
-500mV    -10.64mA   -8.338mA   -14.54mA
0V        -43.3uA    -36.8uA    -53.12uA
875mV     1.025mA    1.039mA    1.03mA
1V        11.08mA    11.08mA    1.104mA
5V        331mA      331mA      321mA
[Pullup]
|Voltage   I(typ)   I(min)   I(max)
-2.5V     206.3mA    156mA      259.4mA
-1.375V   69.25mA    51.3mA     90.02mA
-500mV    4.398mA    4.016mA    5.092mA
3V        -1.763mA   -7.801mA   -1.128mA
3.125V    -5.707mA   -49.89mA   -1.768mA
3.25V     -15.36mA   -177.2mA   -6.34mA
3.375V    -58.14mA   -318.7mA   -18.54mA
3.625V    -365.6mA   -602mA     -106mA
3.75V     -527.1mA   -743.5mA   -292.9mA
3.875V    -688.8mA   -885.2mA   -484.1mA
4V        -850.6mA   -1.027A    -675.2mA
5V        -2.155A    -2.173A    -2.218A
[Ramp]
| variable   typ   min   max
dV/dt_r 77.6451e-3/0.6484e-9   74.8294e-3/0.2576e-9   86.2363e-3/0.2062e-9
dV/dt_f 64.3223e-3/0.4124e-9   63.8106e-3/0.3766e-9   68.3333e-3/0.4211e-9
R_load = 50
[Rising waveform]
R_fixture= 50
V_fixture= 0.907423
V_fixture_min= 0.855621
V_fixture_max= 0.949514
|Time   V(typ)   V(min)   V(max)
0s        856mV      804.3mV    897.4mV
1.13ns    856mV      804.3mV    902.9mV
1.27ns    856mV      804.3mV    858mV
1.51ns    843mV      804.3mV    961.8mV
1.66ns    851.5mV    805.2mV    986mV
1.81ns    914.8mV    805.4mV    993.5mV
1.97ns    944.8mV    786.4mV    997.4mV
2.17ns    958.4mV    839.4mV    999.5mV
2.59ns    959.4mV    908.3mV    1.001V
4ns       958.9mV    907.4mV    1.002V
[Falling waveform]
R_fixture= 50
V_fixture= 0.907423
V_fixture_min= 0.855621
V_fixture_max= 0.949514
|Time   V(typ)   V(min)   V(max)
0s        958.9mV    907.1mV    1.002V
1.24ns    958.8mV    907.1mV    1.011V
1.37ns    959.7mV    907.1mV    963.6mV
1.55ns    959.2mV    907mV      938.5mV
1.7ns     910.3mV    907.7mV    923.2mV
1.81ns    893.8mV    910.4mV    915mV
1.99ns    879.3mV    894.5mV    907.4mV
2.21ns    867.7mV    838.9mV    902.3mV
2.39ns    863.7mV    825.6mV    900.4mV
4ns       855.9mV    804.3mV    897.4mV
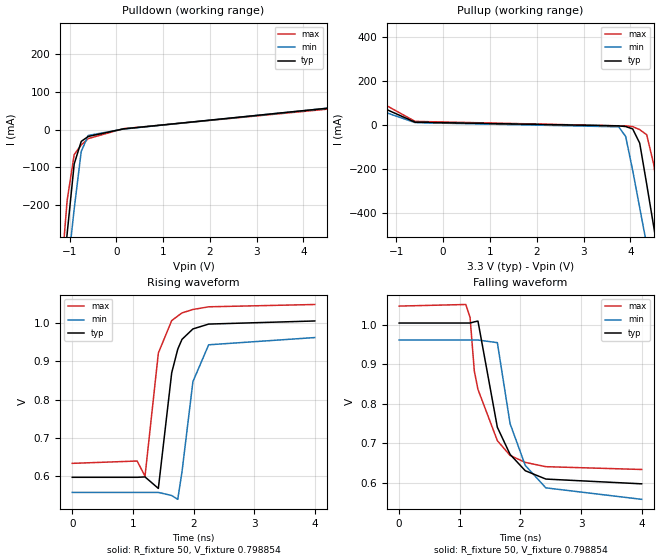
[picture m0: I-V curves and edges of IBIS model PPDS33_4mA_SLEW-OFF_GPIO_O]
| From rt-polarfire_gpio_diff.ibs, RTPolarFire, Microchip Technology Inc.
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|   Model PPDS33_4mA_SLEW-OFF_GPIO_O
[Model]   PPDS33_4mA_SLEW-OFF_GPIO_O
Model_type   Output
Polarity   Non-Inverting
Enable   Active-High
Vmeas =   0.8
Cref =   5p
Rref =   100
|   typ   min   max
C_comp_pullup   2.605e-12   2.605e-12   2.76e-12
C_comp_pulldown  2.605e-12   2.605e-12   2.76e-12
[Temperature Range]  25C   125C   -55C
[Voltage Range]  3.3   3.15   3.45
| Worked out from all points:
|   slope of the pulldown table from 0 to 0.495 V, typ, clamps not added: 125 ohm
|   slope of the pullup table from 0 to 0.495 V, typ, clamps not added: 138 ohm
|   rising waveform, R_fixture 50, V_fixture 0.798854: 20-80 % time 213ps typ, 218ps min, 218ps max; typ from 0.597 V to 1 V
|   falling waveform, R_fixture 50, V_fixture 0.798854: 20-80 % time 388ps typ, 388ps min, 383ps max; typ from 1 V to 0.597 V
[Pulldown]
|Voltage   I(typ)   I(min)   I(max)
-3.3V     -3.224A    -2.962A    -3.688A
-1.2V     -469.2mA   -550.6mA   -416.4mA
-1.05V    -275.2mA   -380.3mA   -186.8mA
-900mV    -90.89mA   -210.2mA   -65.73mA
-750mV    -31.06mA   -57.63mA   -40.54mA
-600mV    -17.76mA   -15.2mA    -23.51mA
150mV     2.168mA    1.726mA    2.732mA
4.5V      56.92mA    56.86mA    54.49mA
5.1V      118.9mA    108mA      126mA
6V        248.7mA    219.9mA    276.2mA
6.15V     273.2mA    241.2mA    303.6mA
6.6V      352.5mA    307.9mA    390.7mA
[Pullup]
|Voltage   I(typ)   I(min)   I(max)
-3.3V     377.2mA    308mA      447.3mA
-1.65V    111.9mA    87.55mA    140mA
-600mV    12.3mA     10.43mA    16.03mA
3.75V     -4.395mA   -8.756mA   -4.24mA
3.9V      -7.565mA   -52.69mA   -4.426mA
4.05V     -18.35mA   -208.2mA   -7.949mA
4.2V      -83.5mA    -378.1mA   -21.54mA
4.35V     -271.3mA   -548mA     -45.23mA
4.5V      -465.1mA   -717.9mA   -180.7mA
4.65V     -659mA     -887.9mA   -410.2mA
4.8V      -853.2mA   -1.058A    -639.6mA
6.6V      -3.217A    -3.13A     -3.442A
[Ramp]
| variable   typ   min   max
dV/dt_r 0.2629/0.2113e-9   0.2563/0.2218e-9   0.2704/0.2137e-9
dV/dt_f 0.2484/0.3855e-9   0.2462/0.3859e-9   0.2518/0.3816e-9
R_load = 50
[Rising waveform]
R_fixture= 50
V_fixture= 0.798854
V_fixture_min= 0.756448
V_fixture_max= 0.839681
|Time   V(typ)   V(min)   V(max)
0s        596.9mV    557.5mV    633.3mV
1.07ns    596.9mV    557.5mV    639.4mV
1.2ns     597.9mV    557.5mV    599.8mV
1.42ns    567.9mV    557.5mV    921.3mV
1.64ns    869.5mV    549.3mV    1.006V
1.74ns    931.3mV    539.4mV    1.018V
1.81ns    957mV      611.1mV    1.026V
1.99ns    984.2mV    846.5mV    1.035V
2.25ns    996.9mV    942.8mV    1.042V
4ns       1.005V     961.7mV    1.048V
[Falling waveform]
R_fixture= 50
V_fixture= 0.798854
V_fixture_min= 0.756448
V_fixture_max= 0.839681
|Time   V(typ)   V(min)   V(max)
0s        1.005V     961.9mV    1.048V
1.1ns     1.005V     961.9mV    1.052V
1.17ns    1.005V     961.9mV    1.019V
1.24ns    1.008V     961.9mV    883.3mV
1.3ns     1.01V      961.9mV    836.7mV
1.62ns    740.6mV    955.3mV    706.7mV
1.83ns    671.8mV    749.8mV    669.2mV
2.08ns    630.5mV    644mV      651.6mV
2.42ns    609.3mV    587mV      640.7mV
4ns       597.2mV    557.9mV    633.6mV
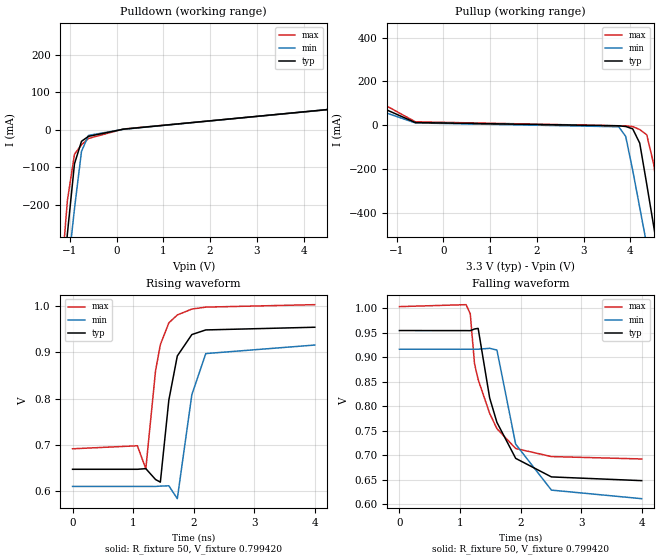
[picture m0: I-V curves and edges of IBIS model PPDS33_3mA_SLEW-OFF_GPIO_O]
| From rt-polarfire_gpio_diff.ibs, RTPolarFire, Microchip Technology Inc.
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|   Model PPDS33_3mA_SLEW-OFF_GPIO_O
[Model]   PPDS33_3mA_SLEW-OFF_GPIO_O
Model_type   Output
Polarity   Non-Inverting
Enable   Active-High
Vmeas =   0.8
Cref =   5p
Rref =   100
|   typ   min   max
C_comp_pullup   2.605e-12   2.605e-12   2.76e-12
C_comp_pulldown  2.605e-12   2.605e-12   2.76e-12
[Temperature Range]  25C   125C   -55C
[Voltage Range]  3.3   3.15   3.45
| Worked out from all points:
|   slope of the pulldown table from 0 to 0.495 V, typ, clamps not added: 168 ohm
|   slope of the pullup table from 0 to 0.495 V, typ, clamps not added: 176 ohm
|   rising waveform, R_fixture 50, V_fixture 0.799420: 20-80 % time 211ps typ, 207ps min, 211ps max; typ from 0.648 V to 0.954 V
|   falling waveform, R_fixture 50, V_fixture 0.799420: 20-80 % time 410ps typ, 413ps min, 405ps max; typ from 0.954 V to 0.648 V
[Pulldown]
|Voltage   I(typ)   I(min)   I(max)
-3.3V     -3.224A    -2.962A    -3.688A
-1.2V     -469mA     -550.4mA   -416.1mA
-1.05V    -275mA     -380.2mA   -186.5mA
-900mV    -90.52mA   -210.1mA   -65.04mA
-750mV    -30.57mA   -57.34mA   -39.88mA
-600mV    -17.3mA    -14.85mA   -22.9mA
150mV     1.829mA    1.486mA    2.227mA
4.5V      53.84mA    53.79mA    53.38mA
5.1V      117.8mA    106.9mA    124.9mA
6V        247.5mA    218.7mA    275mA
6.15V     272mA      239.9mA    302.4mA
6.6V      351.2mA    306.6mA    389.3mA
[Pullup]
|Voltage   I(typ)   I(min)   I(max)
-3.3V     376.9mA    307.9mA    446.7mA
-1.65V    110.7mA    87.08mA    138.5mA
-600mV    11.45mA    9.777mA    14.94mA
3.75V     -3.367mA   -7.747mA   -3.199mA
3.9V      -6.549mA   -51.75mA   -3.386mA
4.05V     -17.34mA   -207.3mA   -6.924mA
4.2V      -82.6mA    -377.2mA   -20.53mA
4.35V     -270.5mA   -547.1mA   -44.21mA
4.5V      -464.2mA   -717mA     -179.9mA
4.65V     -658.2mA   -887mA     -409.3mA
4.8V      -852.3mA   -1.057A    -638.7mA
6.6V      -3.216A    -3.129A    -3.441A
[Ramp]
| variable   typ   min   max
dV/dt_r 0.2050/0.2111e-9   0.1991/0.2150e-9   0.2132/0.2113e-9
dV/dt_f 0.1872/0.4072e-9   0.1864/0.4118e-9   0.1898/0.4022e-9
R_load = 50
[Rising waveform]
R_fixture= 50
V_fixture= 0.799420
V_fixture_min= 0.761896
V_fixture_max= 0.846877
|Time   V(typ)   V(min)   V(max)
0s        647.9mV    611mV      692.1mV
1.07ns    647.9mV    611mV      698.6mV
1.21ns    649.3mV    611mV      649.1mV
1.37ns    625.9mV    610.9mV    860mV
1.45ns    620.2mV    611.6mV    916.8mV
1.59ns    797.1mV    612.3mV    963.7mV
1.73ns    892.4mV    584.5mV    980.8mV
1.97ns    938.5mV    808.8mV    993.5mV
2.2ns     948.5mV    897.5mV    997.7mV
4ns       954.3mV    915.9mV    1.003V
[Falling waveform]
R_fixture= 50
V_fixture= 0.799420
V_fixture_min= 0.761896
V_fixture_max= 0.846877
|Time   V(typ)   V(min)   V(max)
0s        954.2mV    916.1mV    1.003V
1.1ns     954.1mV    916.1mV    1.007V
1.17ns    954mV      916.1mV    988.4mV
1.24ns    957.4mV    916.1mV    886.5mV
1.3ns     958.6mV    916.1mV    854.2mV
1.49ns    816.8mV    918mV      785.3mV
1.61ns    766.9mV    914.4mV    754mV
1.92ns    693.5mV    722.4mV    713.7mV
2.51ns    655.7mV    628.8mV    697.2mV
4ns       648.1mV    611.3mV    692.3mV
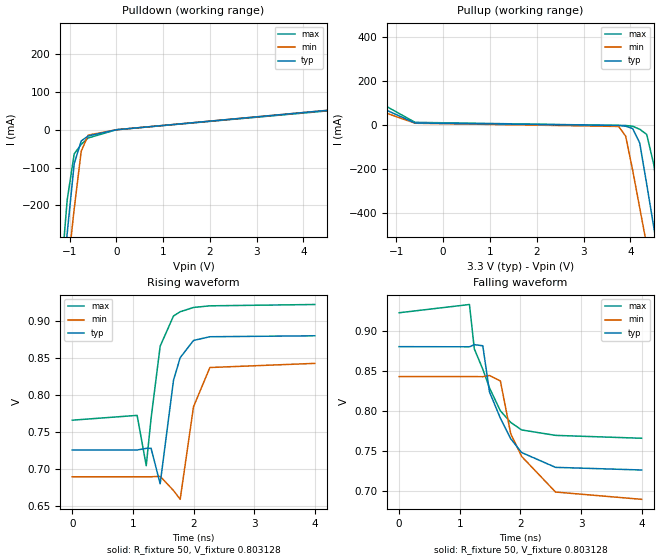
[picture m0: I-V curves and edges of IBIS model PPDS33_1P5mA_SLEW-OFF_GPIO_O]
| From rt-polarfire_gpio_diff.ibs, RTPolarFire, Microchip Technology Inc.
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|   Model PPDS33_1P5mA_SLEW-OFF_GPIO_O
[Model]   PPDS33_1P5mA_SLEW-OFF_GPIO_O
Model_type   Output
Polarity   Non-Inverting
Enable   Active-High
Vmeas =   0.8
Cref =   5p
Rref =   100
|   typ   min   max
C_comp_pullup   2.605e-12   2.605e-12   2.76e-12
C_comp_pulldown  2.605e-12   2.605e-12   2.76e-12
[Temperature Range]  25C   125C   -55C
[Voltage Range]  3.3   3.15   3.45
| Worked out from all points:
|   slope of the pulldown table from 0 to 0.495 V, typ, clamps not added: 340 ohm
|   slope of the pullup table from 0 to 0.495 V, typ, clamps not added: 335 ohm
|   rising waveform, R_fixture 50, V_fixture 0.803128: 20-80 % time 212ps typ, 206ps min, 213ps max; typ from 0.726 V to 0.881 V
|   falling waveform, R_fixture 50, V_fixture 0.803128: 20-80 % time 472ps typ, 477ps min, 474ps max; typ from 0.881 V to 0.727 V
[Pulldown]
|Voltage   I(typ)   I(min)   I(max)
-3.3V     -3.224A    -2.962A    -3.688A
-1.2V     -468.6mA   -550.1mA   -415.7mA
-1.05V    -274.6mA   -379.8mA   -186mA
-900mV    -89.88mA   -209.7mA   -63.8mA
-750mV    -29.68mA   -56.81mA   -38.68mA
-600mV    -16.48mA   -14.21mA   -21.78mA
0V        -40.3uA    -35.02uA   -49.28uA
4.5V      51.24mA    51.17mA    49.77mA
5.1V      116.3mA    105.3mA    123.3mA
6V        245.7mA    216.9mA    273.2mA
6.15V     270.1mA    238mA      300.5mA
6.6V      349.2mA    304.6mA    387.3mA
[Pullup]
|Voltage   I(typ)   I(min)   I(max)
-3.3V     376.5mA    307.6mA    446.1mA
-1.65V    109.1mA    86.61mA    136.5mA
-600mV    9.45mA     8.298mA    12.35mA
3.75V     -1.821mA   -6.232mA   -1.633mA
3.9V      -5.021mA   -50.35mA   -1.823mA
4.05V     -15.84mA   -206mA     -5.381mA
4.2V      -81.25mA   -375.8mA   -19.02mA
4.35V     -269.2mA   -545.8mA   -42.68mA
4.5V      -462.9mA   -715.6mA   -178.6mA
4.65V     -656.8mA   -885.7mA   -408mA
4.8V      -851mA     -1.056A    -637.3mA
6.6V      -3.215A    -3.128A    -3.44A
[Ramp]
| variable   typ   min   max
dV/dt_r 0.1210/0.2130e-9   0.1148/0.5777e-9   0.1309/0.2187e-9
dV/dt_f 95.4105e-3/0.4683e-9   94.8240e-3/0.4754e-9   0.1003/0.4662e-9
R_load = 50
[Rising waveform]
R_fixture= 50
V_fixture= 0.803128
V_fixture_min= 0.766108
V_fixture_max= 0.844613
|Time   V(typ)   V(min)   V(max)
0s        726.2mV    690mV      766.5mV
1.07ns    726.2mV    690mV      773mV
1.22ns    728.4mV    690mV      704.9mV
1.3ns     728.5mV    690mV      768.9mV
1.45ns    680.5mV    690.6mV    866.6mV
1.67ns    820.5mV    671.4mV    907.4mV
1.78ns    851mV      659.5mV    913.1mV
2ns       874.3mV    784.7mV    918.9mV
2.27ns    879.3mV    837.7mV    921.1mV
4ns       880.6mV    843.3mV    922.9mV
[Falling waveform]
R_fixture= 50
V_fixture= 0.803128
V_fixture_min= 0.766108
V_fixture_max= 0.844613
|Time   V(typ)   V(min)   V(max)
0s        880.6mV    843.3mV    922.9mV
1.16ns    880.4mV    843.3mV    933.2mV
1.24ns    883.1mV    843.3mV    877.8mV
1.38ns    881.7mV    843.1mV    852.4mV
1.49ns    824.1mV    844.6mV    829.2mV
1.67ns    791.3mV    837.8mV    800.5mV
1.84ns    765.8mV    772.1mV    786.1mV
2.02ns    748.5mV    743.7mV    776.7mV
2.58ns    730mV      699.2mV    769.9mV
4ns       726.7mV    690.1mV    766.3mV
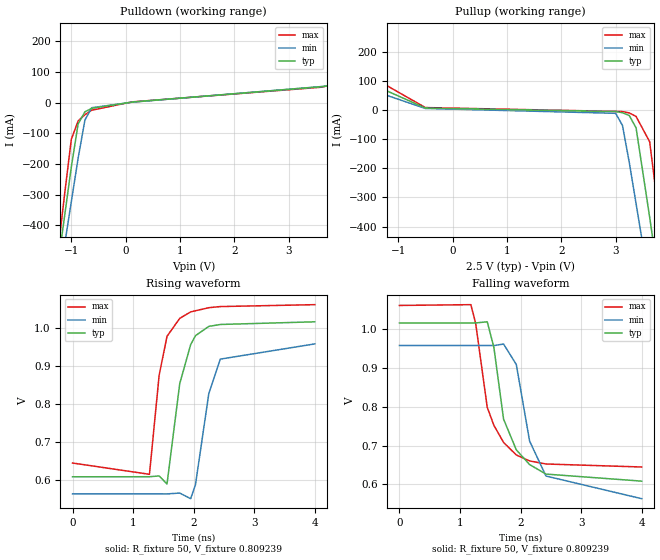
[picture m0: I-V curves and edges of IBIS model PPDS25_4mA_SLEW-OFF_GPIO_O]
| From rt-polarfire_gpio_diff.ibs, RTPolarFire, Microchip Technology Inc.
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|   Model PPDS25_4mA_SLEW-OFF_GPIO_O
[Model]   PPDS25_4mA_SLEW-OFF_GPIO_O
Model_type   Output
Polarity   Non-Inverting
Enable   Active-High
Vmeas =   0.8
Cref =   5p
Rref =   100
|   typ   min   max
C_comp_pullup   2.605e-12   2.605e-12   2.76e-12
C_comp_pulldown  2.605e-12   2.605e-12   2.76e-12
[Temperature Range]  25C   125C   -55C
[Voltage Range]  2.5   2.375   2.625
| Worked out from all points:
|   slope of the pulldown table from 0 to 0.375 V, typ, clamps not added: 101 ohm
|   slope of the pullup table from 0 to 0.375 V, typ, clamps not added: 129 ohm
|   rising waveform, R_fixture 50, V_fixture 0.809239: 20-80 % time 236ps typ, 255ps min, 215ps max; typ from 0.608 V to 1.01 V
|   falling waveform, R_fixture 50, V_fixture 0.809239: 20-80 % time 347ps typ, 350ps min, 353ps max; typ from 1.01 V to 0.609 V
[Pulldown]
|Voltage   I(typ)   I(min)   I(max)
-2.5V     -2.163A    -2.035A    -2.424A
-1.25V    -533.5mA   -606.9mA   -492.6mA
-1.125V   -371.8mA   -465.1mA   -301.1mA
-1V       -210.3mA   -323.3mA   -119.8mA
-875mV    -69.77mA   -181.6mA   -59.95mA
-750mV    -30.28mA   -57.09mA   -39.68mA
-625mV    -18.77mA   -16.89mA   -24.93mA
125mV     1.765mA    1.355mA    2.313mA
3.625V    52.16mA    52.62mA    50.44mA
3.75V     55.47mA    54.03mA    57.54mA
4.25V     110.3mA    97.46mA    120.6mA
5V        214.3mA    185.1mA    242.3mA
[Pullup]
|Voltage   I(typ)   I(min)   I(max)
-2.5V     229.6mA    182.6mA    282.6mA
-1.5V     90.62mA    69.34mA    115.4mA
-500mV    7.419mA    5.914mA    9.009mA
3V        -4.839mA   -10.77mA   -4.255mA
3.125V    -8.74mA    -52.66mA   -4.879mA
3.25V     -18.34mA   -179.9mA   -9.401mA
3.375V    -60.89mA   -321.4mA   -21.54mA
3.625V    -368.2mA   -604.6mA   -108.7mA
3.75V     -529.7mA   -746.2mA   -295.4mA
3.875V    -691.4mA   -887.9mA   -486.7mA
4V        -853.2mA   -1.03A     -677.8mA
5V        -2.158A    -2.175A    -2.22A
[Ramp]
| variable   typ   min   max
dV/dt_r 0.2559/0.2374e-9   0.2439/0.2591e-9   0.2677/0.2168e-9
dV/dt_f 0.2474/0.3463e-9   0.2401/0.3528e-9   0.2518/0.3511e-9
R_load = 50
[Rising waveform]
R_fixture= 50
V_fixture= 0.809239
V_fixture_min= 0.755346
V_fixture_max= 0.851368
|Time   V(typ)   V(min)   V(max)
0s        608.3mV    563.4mV    644.4mV
1.27ns    608.4mV    563.4mV    614.8mV
1.43ns    610.5mV    563.4mV    874.7mV
1.56ns    589.4mV    563.3mV    977mV
1.77ns    852.8mV    565.6mV    1.024V
1.95ns    954.8mV    550.8mV    1.041V
2.03ns    978.6mV    587.6mV    1.044V
2.25ns    1.003V     826.5mV    1.052V
2.44ns    1.008V     917.1mV    1.055V
4ns       1.015V     957mV      1.06V
[Falling waveform]
R_fixture= 50
V_fixture= 0.809239
V_fixture_min= 0.755346
V_fixture_max= 0.851368
|Time   V(typ)   V(min)   V(max)
0s        1.015V     957.1mV    1.06V
1.18ns    1.015V     957.1mV    1.062V
1.26ns    1.015V     957.1mV    1.013V
1.45ns    1.018V     957.1mV    798.4mV
1.56ns    952.2mV    956.9mV    751.9mV
1.72ns    767.8mV    960.8mV    708mV
1.93ns    689mV      908.3mV    675.8mV
2.15ns    651.1mV    711.4mV    660.5mV
2.42ns    626.7mV    621.7mV    652.6mV
4ns       608.6mV    563.5mV    644.9mV
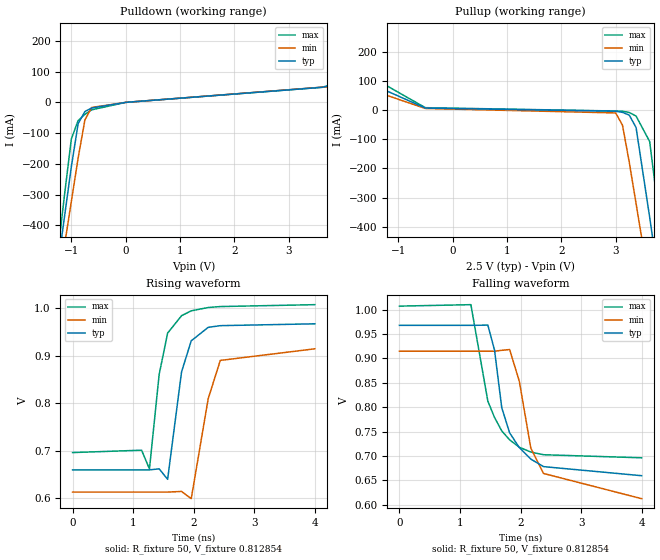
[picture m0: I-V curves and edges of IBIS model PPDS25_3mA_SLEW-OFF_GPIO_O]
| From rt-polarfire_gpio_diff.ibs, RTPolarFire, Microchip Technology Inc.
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|   Model PPDS25_3mA_SLEW-OFF_GPIO_O
[Model]   PPDS25_3mA_SLEW-OFF_GPIO_O
Model_type   Output
Polarity   Non-Inverting
Enable   Active-High
Vmeas =   0.8
Cref =   5p
Rref =   100
|   typ   min   max
C_comp_pullup   2.605e-12   2.605e-12   2.76e-12
C_comp_pulldown  2.605e-12   2.605e-12   2.76e-12
[Temperature Range]  25C   125C   -55C
[Voltage Range]  2.5   2.375   2.625
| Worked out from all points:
|   slope of the pulldown table from 0 to 0.375 V, typ, clamps not added: 131 ohm
|   slope of the pullup table from 0 to 0.375 V, typ, clamps not added: 158 ohm
|   rising waveform, R_fixture 50, V_fixture 0.812854: 20-80 % time 211ps typ, 241ps min, 210ps max; typ from 0.659 V to 0.968 V
|   falling waveform, R_fixture 50, V_fixture 0.812854: 20-80 % time 367ps typ, 354ps min, 364ps max; typ from 0.968 V to 0.659 V
[Pulldown]
|Voltage   I(typ)   I(min)   I(max)
-2.5V     -2.163A    -2.035A    -2.424A
-1.25V    -533.3mA   -606.8mA   -492.4mA
-1.125V   -371.6mA   -465mA     -300.8mA
-1V       -210.1mA   -323.1mA   -119.3mA
-875mV    -69.4mA    -181.4mA   -59.31mA
-750mV    -29.85mA   -56.84mA   -39.07mA
-625mV    -18.36mA   -16.59mA   -24.36mA
0V        -43.61uA   -37.06uA   -53.29uA
3.625V    49.16mA    49.65mA    49.34mA
3.75V     54.47mA    51.05mA    56.45mA
4.25V     109.2mA    96.46mA    119.5mA
5V        213.2mA    184mA      241.1mA
[Pullup]
|Voltage   I(typ)   I(min)   I(max)
-2.5V     229.1mA    182.5mA    281.2mA
-1.5V     89.57mA    68.73mA    114mA
-500mV    6.786mA    5.484mA    8.188mA
3V        -3.815mA   -9.794mA   -3.215mA
3.125V    -7.728mA   -51.74mA   -3.843mA
3.25V     -17.34mA   -179mA     -8.379mA
3.375V    -59.97mA   -320.5mA   -20.53mA
3.625V    -367.3mA   -603.8mA   -107.8mA
3.75V     -528.8mA   -745.3mA   -294.6mA
3.875V    -690.5mA   -887mA     -485.8mA
4V        -852.3mA   -1.029A    -676.9mA
5V        -2.157A    -2.174A    -2.22A
[Ramp]
| variable   typ   min   max
dV/dt_r 0.1979/0.2167e-9   0.1914/0.2499e-9   0.2078/0.2130e-9
dV/dt_f 0.1882/0.3635e-9   0.1848/0.3565e-9   0.1897/0.3625e-9
R_load = 50
[Rising waveform]
R_fixture= 50
V_fixture= 0.812854
V_fixture_min= 0.761145
V_fixture_max= 0.851022
|Time   V(typ)   V(min)   V(max)
0s        659.3mV    612.5mV    695.9mV
1.14ns    659.3mV    612.5mV    700.9mV
1.27ns    659.3mV    612.5mV    661.4mV
1.43ns    661.6mV    612.5mV    860.6mV
1.57ns    639.5mV    612.5mV    948mV
1.8ns     866.1mV    613.9mV    984.7mV
1.96ns    931.8mV    598.6mV    995mV
2.24ns    960.1mV    809.5mV    1.002V
2.44ns    963.7mV    890.4mV    1.004V
4ns       967.6mV    914.8mV    1.008V
[Falling waveform]
R_fixture= 50
V_fixture= 0.812854
V_fixture_min= 0.761145
V_fixture_max= 0.851022
|Time   V(typ)   V(min)   V(max)
0s        967.6mV    914.7mV    1.007V
1.18ns    967.6mV    914.7mV    1.01V
1.46ns    968.1mV    914.7mV    812.2mV
1.57ns    917.1mV    914.5mV    778.9mV
1.69ns    798.8mV    916.4mV    751.2mV
1.82ns    747.2mV    918mV      732.9mV
1.98ns    717mV      852.9mV    717.7mV
2.17ns    693.4mV    715.7mV    707.9mV
2.38ns    678mV      664mV      702.4mV
4ns       659.4mV    612.3mV    696.1mV
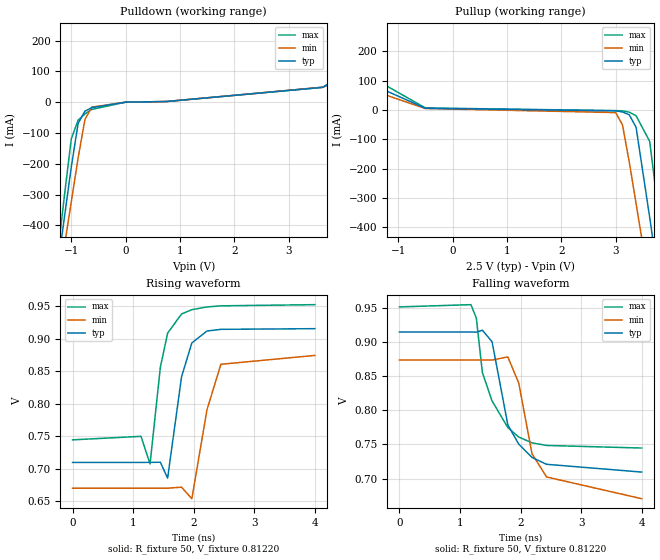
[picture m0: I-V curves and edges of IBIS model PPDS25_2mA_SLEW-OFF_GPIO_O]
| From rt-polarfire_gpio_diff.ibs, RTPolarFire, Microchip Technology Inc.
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|   Model PPDS25_2mA_SLEW-OFF_GPIO_O
[Model]   PPDS25_2mA_SLEW-OFF_GPIO_O
Model_type   Output
Polarity   Non-Inverting
Enable   Active-High
Vmeas =   0.8
Cref =   5p
Rref =   100
|   typ   min   max
C_comp_pullup   2.605e-12   2.605e-12   2.76e-12
C_comp_pulldown  2.605e-12   2.605e-12   2.76e-12
[Temperature Range]  25C   125C   -55C
[Voltage Range]  2.5   2.375   2.625
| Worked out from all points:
|   slope of the pulldown table from 0 to 0.375 V, typ, clamps not added: 198 ohm
|   slope of the pullup table from 0 to 0.375 V, typ, clamps not added: 218 ohm
|   rising waveform, R_fixture 50, V_fixture 0.81220: 20-80 % time 200ps typ, 233ps min, 204ps max; typ from 0.71 V to 0.915 V
|   falling waveform, R_fixture 50, V_fixture 0.81220: 20-80 % time 377ps typ, 363ps min, 395ps max; typ from 0.915 V to 0.709 V
[Pulldown]
|Voltage   I(typ)   I(min)   I(max)
-2.5V     -2.163A    -2.035A    -2.424A
-1.25V    -533.1mA   -606.6mA   -492.1mA
-1.125V   -371.4mA   -464.8mA   -300.6mA
-1V       -209.9mA   -322.9mA   -118.7mA
-875mV    -68.95mA   -181.3mA   -58.57mA
-750mV    -29.32mA   -56.54mA   -38.35mA
-625mV    -17.86mA   -16.22mA   -23.68mA
0V        -41.32uA   -35.48uA   -50.45uA
750mV     2.077mA    2.059mA    2.063mA
3.625V    48.1mA     48.62mA    48.26mA
4.25V     108.2mA    95.42mA    118.4mA
5V        212mA      182.9mA    239.9mA
[Pullup]
|Voltage   I(typ)   I(min)   I(max)
-2.5V     228.8mA    182.4mA    280mA
-1.5V     88.51mA    68.27mA    112.6mA
-500mV    5.874mA    5.07mA     7.008mA
3V        -2.783mA   -8.795mA   -2.166mA
3.125V    -6.708mA   -50.81mA   -2.799mA
3.25V     -16.34mA   -178.1mA   -7.349mA
3.375V    -59.03mA   -319.6mA   -19.52mA
3.625V    -366.4mA   -602.9mA   -106.9mA
3.75V     -528mA     -744.4mA   -293.7mA
3.875V    -689.6mA   -886.1mA   -484.9mA
4V        -851.4mA   -1.028A    -676mA
5V        -2.156A    -2.174A    -2.219A
[Ramp]
| variable   typ   min   max
dV/dt_r 0.1380/0.2087e-9   0.1348/0.2525e-9   0.1473/0.2097e-9
dV/dt_f 0.1266/0.3750e-9   0.1251/0.3637e-9   0.1272/0.3909e-9
R_load = 50
[Rising waveform]
R_fixture= 50
V_fixture= 0.81220
V_fixture_min= 0.771210
V_fixture_max= 0.848018
|Time   V(typ)   V(min)   V(max)
0s        709.7mV    670.1mV    744.4mV
1.13ns    709.7mV    670.1mV    749.8mV
1.28ns    709.8mV    670.1mV    707.4mV
1.45ns    710mV      670.1mV    856.1mV
1.57ns    685.5mV    670.1mV    908.3mV
1.8ns     841.3mV    671.7mV    937.8mV
1.97ns    893.3mV    654mV      944.4mV
2.22ns    911.6mV    790.7mV    948.6mV
2.45ns    914.2mV    860.5mV    950.3mV
4ns       915.2mV    874.1mV    952.1mV
[Falling waveform]
R_fixture= 50
V_fixture= 0.81220
V_fixture_min= 0.771210
V_fixture_max= 0.848018
|Time   V(typ)   V(min)   V(max)
0s        915.3mV    874.1mV    952.1mV
1.18ns    915.3mV    874.1mV    955.4mV
1.27ns    915mV      874.1mV    935.7mV
1.37ns    917.8mV    874.1mV    855.5mV
1.53ns    900.9mV    874mV      813.9mV
1.79ns    778.9mV    878.7mV    774.9mV
1.97ns    750.6mV    840.3mV    761mV
2.19ns    730.9mV    736.2mV    752.4mV
2.43ns    720.9mV    702.3mV    748.6mV
4ns       709.5mV    670.4mV    744.8mV
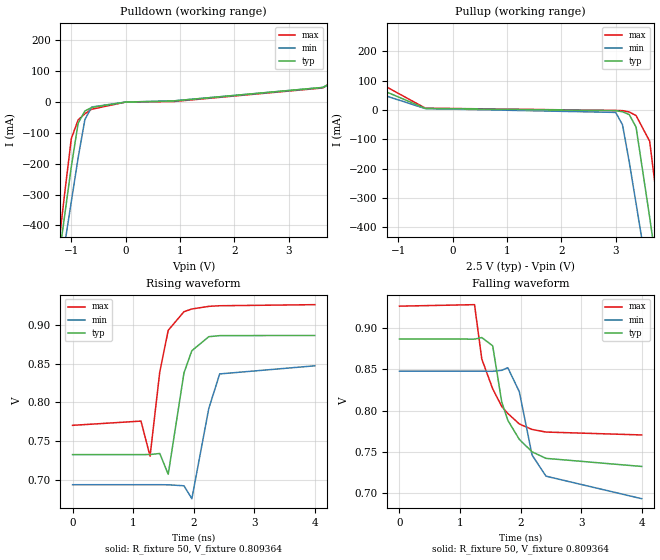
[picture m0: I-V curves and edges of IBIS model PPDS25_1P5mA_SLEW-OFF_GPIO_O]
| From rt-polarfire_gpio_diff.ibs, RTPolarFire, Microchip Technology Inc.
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|   Model PPDS25_1P5mA_SLEW-OFF_GPIO_O
[Model]   PPDS25_1P5mA_SLEW-OFF_GPIO_O
Model_type   Output
Polarity   Non-Inverting
Enable   Active-High
Vmeas =   0.8
Cref =   5p
Rref =   100
|   typ   min   max
C_comp_pullup   2.605e-12   2.605e-12   2.76e-12
C_comp_pulldown  2.605e-12   2.605e-12   2.76e-12
[Temperature Range]  25C   125C   -55C
[Voltage Range]  2.5   2.375   2.625
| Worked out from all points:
|   slope of the pulldown table from 0 to 0.375 V, typ, clamps not added: 267 ohm
|   slope of the pullup table from 0 to 0.375 V, typ, clamps not added: 279 ohm
|   rising waveform, R_fixture 50, V_fixture 0.809364: 20-80 % time 207ps typ, 217ps min, 206ps max; typ from 0.732 V to 0.887 V
|   falling waveform, R_fixture 50, V_fixture 0.809364: 20-80 % time 400ps typ, 379ps min, 423ps max; typ from 0.887 V to 0.732 V
[Pulldown]
|Voltage   I(typ)   I(min)   I(max)
-2.5V     -2.163A    -2.035A    -2.424A
-1.25V    -533mA     -606.5mA   -491.9mA
-1.125V   -371.3mA   -464.7mA   -300.4mA
-1V       -209.7mA   -322.8mA   -118.4mA
-875mV    -68.68mA   -181.1mA   -58.14mA
-750mV    -29mA      -56.36mA   -37.93mA
-625mV    -17.57mA   -16.01mA   -23.28mA
0V        -40.08uA   -34.45uA   -49.15uA
875mV     3.612mA    3.615mA    1.623mA
3.625V    47.55mA    47.11mA    45.73mA
4.25V     107.6mA    94.89mA    117.9mA
5V        211.4mA    182.3mA    239.3mA
[Pullup]
|Voltage   I(typ)   I(min)   I(max)
-2.5V     228.7mA    182.3mA    279.5mA
-1.375V   74.04mA    56.89mA    94.91mA
-500mV    5.245mA    4.624mA    6.194mA
3V        -2.274mA   -8.295mA   -1.65mA
3.125V    -6.204mA   -50.35mA   -2.285mA
3.25V     -15.84mA   -177.7mA   -6.842mA
3.375V    -58.57mA   -319.2mA   -19.02mA
3.625V    -366mA     -602.4mA   -106.5mA
3.75V     -527.5mA   -744mA     -293.3mA
3.875V    -689.2mA   -885.7mA   -484.5mA
4V        -851mA     -1.028A    -675.6mA
5V        -2.155A    -2.173A    -2.218A
[Ramp]
| variable   typ   min   max
dV/dt_r 0.1083/0.2206e-9   0.1060/0.2431e-9   0.1182/0.2107e-9
dV/dt_f 95.6821e-3/0.3939e-9   95.4387e-3/0.3799e-9   96.4958e-3/0.4168e-9
R_load = 50
[Rising waveform]
R_fixture= 50
V_fixture= 0.809364
V_fixture_min= 0.770384
V_fixture_max= 0.848355
|Time   V(typ)   V(min)   V(max)
0s        732.5mV    693.5mV    770.4mV
1.13ns    732.5mV    693.5mV    775.9mV
1.28ns    732.6mV    693.5mV    730.5mV
1.44ns    734mV      693.5mV    839.4mV
1.58ns    707mV      693.4mV    893.5mV
1.84ns    838.3mV    692.1mV    917.6mV
1.97ns    867.1mV    675.4mV    921.1mV
2.25ns    885.2mV    792.3mV    924.5mV
2.43ns    886.6mV    837mV      925.3mV
4ns       886.8mV    847.5mV    926.7mV
[Falling waveform]
R_fixture= 50
V_fixture= 0.809364
V_fixture_min= 0.770384
V_fixture_max= 0.848355
|Time   V(typ)   V(min)   V(max)
0s        886.9mV    847.8mV    926.7mV
1.24ns    886.7mV    847.8mV    928.5mV
1.36ns    888.6mV    847.8mV    862.6mV
1.54ns    878.6mV    847.7mV    826.4mV
1.69ns    810.3mV    848.9mV    805mV
1.79ns    788.3mV    852mV      796.6mV
1.98ns    765.1mV    822.9mV    783.8mV
2.19ns    750mV      746.2mV    777.2mV
2.42ns    742.1mV    720.5mV    774mV
4ns       732.3mV    693.2mV    770.5mV
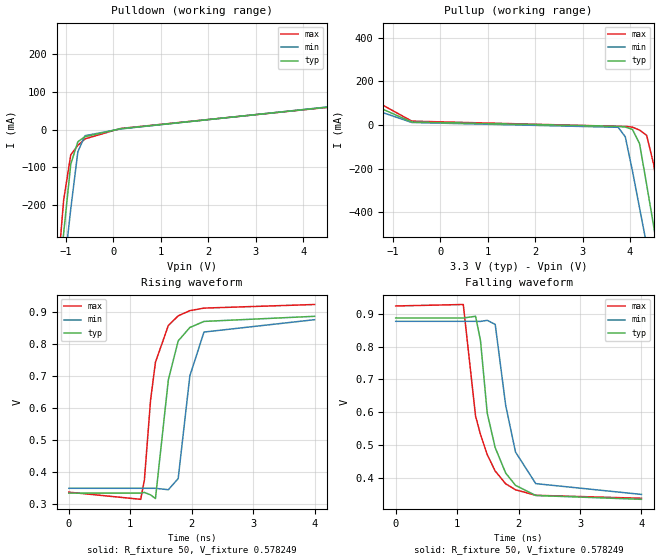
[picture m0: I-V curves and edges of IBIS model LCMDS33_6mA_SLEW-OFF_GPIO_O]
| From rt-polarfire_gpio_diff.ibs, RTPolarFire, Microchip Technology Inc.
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|   Model LCMDS33_6mA_SLEW-OFF_GPIO_O
[Model]   LCMDS33_6mA_SLEW-OFF_GPIO_O
Model_type   Output
Polarity   Non-Inverting
Enable   Active-High
Vmeas =   0.6
Cref =   5p
Rref =   100
|   typ   min   max
C_comp_pullup   2.605e-12   2.605e-12   2.76e-12
C_comp_pulldown  2.605e-12   2.605e-12   2.76e-12
[Temperature Range]  25C   125C   -55C
[Voltage Range]  3.3   3.15   3.45
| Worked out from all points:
|   slope of the pulldown table from 0 to 0.495 V, typ, clamps not added: 77.7 ohm
|   slope of the pullup table from 0 to 0.495 V, typ, clamps not added: 102 ohm
|   rising waveform, R_fixture 50, V_fixture 0.578249: 20-80 % time 220ps typ, 221ps min, 228ps max; typ from 0.334 V to 0.888 V
|   falling waveform, R_fixture 50, V_fixture 0.578249: 20-80 % time 313ps typ, 299ps min, 339ps max; typ from 0.888 V to 0.334 V
[Pulldown]
|Voltage   I(typ)   I(min)   I(max)
-3.3V     -3.224A    -2.962A    -3.689A
-1.2V     -469.5mA   -550.9mA   -416.7mA
-1.05V    -275.5mA   -380.7mA   -187.2mA
-900mV    -91.41mA   -210.6mA   -66.63mA
-750mV    -31.78mA   -58.19mA   -41.41mA
-600mV    -18.42mA   -15.86mA   -24.32mA
150mV     2.619mA    2.12mA     3.37mA
4.5V      59.83mA    60.33mA    59.33mA
5.1V      120.8mA    110.5mA    127.8mA
6V        250.9mA    222.6mA    278.2mA
6.3V      301mA      265.9mA    334mA
6.6V      355mA      311mA      393mA
[Pullup]
|Voltage   I(typ)   I(min)   I(max)
-3.3V     378.7mA    308.8mA    450mA
-1.65V    114.2mA    88.9mA     143.2mA
-600mV    13.42mA    11.3mA     17.5mA
3.75V     -6.446mA   -10.76mA   -6.319mA
3.9V      -9.578mA   -54.56mA   -6.497mA
4.05V     -20.33mA   -210mA     -9.975mA
4.2V      -85.27mA   -379.9mA   -23.54mA
4.35V     -273.1mA   -549.8mA   -47.21mA
4.5V      -466.8mA   -719.7mA   -182.4mA
4.65V     -660.7mA   -889.7mA   -411.8mA
4.8V      -854.9mA   -1.06A     -641mA
6.6V      -3.219A    -3.132A    -3.444A
[Ramp]
| variable   typ   min   max
dV/dt_r 0.3445/0.2211e-9   0.3273/0.2235e-9   0.3667/0.2266e-9
dV/dt_f 0.3369/0.3114e-9   0.3217/0.2996e-9   0.3565/0.3378e-9
R_load = 50
[Rising waveform]
R_fixture= 50
V_fixture= 0.578249
V_fixture_min= 0.569220
V_fixture_max= 0.611558
|Time   V(typ)   V(min)   V(max)
0s        333.9mV    349.1mV    336.9mV
1.17ns    334mV      349.1mV    314.5mV
1.23ns    336.2mV    349.1mV    375mV
1.33ns    328.5mV    349.1mV    624.2mV
1.41ns    317mV      349.1mV    744mV
1.62ns    688.9mV    344.6mV    859.3mV
1.78ns    810.8mV    379.6mV    889.3mV
1.97ns    852.9mV    701.4mV    905.6mV
2.2ns     871.9mV    838.6mV    913.6mV
4ns       887.9mV    877.3mV    924.9mV
[Falling waveform]
R_fixture= 50
V_fixture= 0.578249
V_fixture_min= 0.569220
V_fixture_max= 0.611558
|Time   V(typ)   V(min)   V(max)
0s        887.6mV    877.4mV    924.2mV
1.1ns     887.5mV    877.4mV    928.7mV
1.3ns     892.8mV    877.4mV    588mV
1.38ns    819mV      877.1mV    532.4mV
1.49ns    597mV      880.4mV    470.5mV
1.62ns    491.7mV    867.9mV    420.3mV
1.79ns    414.4mV    621.3mV    381.7mV
1.95ns    376.9mV    478.5mV    363.4mV
2.28ns    345.9mV    382.1mV    346.5mV
4ns       334.2mV    349.2mV    337.4mV
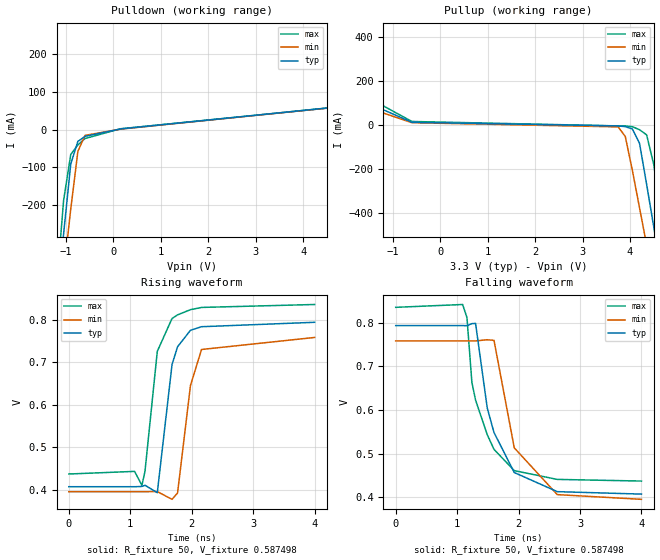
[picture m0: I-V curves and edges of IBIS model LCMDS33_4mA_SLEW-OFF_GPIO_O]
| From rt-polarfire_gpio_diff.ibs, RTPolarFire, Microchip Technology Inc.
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|   Model LCMDS33_4mA_SLEW-OFF_GPIO_O
[Model]   LCMDS33_4mA_SLEW-OFF_GPIO_O
Model_type   Output
Polarity   Non-Inverting
Enable   Active-High
Vmeas =   0.6
Cref =   5p
Rref =   100
|   typ   min   max
C_comp_pullup   2.605e-12   2.605e-12   2.76e-12
C_comp_pulldown  2.605e-12   2.605e-12   2.76e-12
[Temperature Range]  25C   125C   -55C
[Voltage Range]  3.3   3.15   3.45
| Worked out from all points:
|   slope of the pulldown table from 0 to 0.495 V, typ, clamps not added: 114 ohm
|   slope of the pullup table from 0 to 0.495 V, typ, clamps not added: 138 ohm
|   rising waveform, R_fixture 50, V_fixture 0.587498: 20-80 % time 208ps typ, 207ps min, 217ps max; typ from 0.407 V to 0.794 V
|   falling waveform, R_fixture 50, V_fixture 0.587498: 20-80 % time 388ps typ, 386ps min, 383ps max; typ from 0.794 V to 0.407 V
[Pulldown]
|Voltage   I(typ)   I(min)   I(max)
-3.3V     -3.224A    -2.962A    -3.688A
-1.2V     -469.1mA   -550.5mA   -416.3mA
-1.05V    -275.1mA   -380.2mA   -186.7mA
-900mV    -90.76mA   -210.1mA   -65.55mA
-750mV    -30.91mA   -57.45mA   -40.37mA
-600mV    -17.61mA   -14.99mA   -23.36mA
150mV     2.094mA    1.602mA    2.643mA
4.5V      57.62mA    57.23mA    57.27mA
5.1V      118.7mA    107.4mA    125.8mA
6V        248.5mA    219.3mA    276mA
6.15V     273mA      240.6mA    303.4mA
6.6V      352.4mA    307.4mA    390.6mA
[Pullup]
|Voltage   I(typ)   I(min)   I(max)
-3.3V     377.9mA    308.4mA    448mA
-1.65V    112mA      87.63mA    140.3mA
-600mV    12.31mA    10.44mA    16.07mA
3.75V     -4.383mA   -8.729mA   -4.23mA
3.9V      -7.534mA   -52.66mA   -4.412mA
4.05V     -18.3mA    -208.2mA   -7.916mA
4.2V      -83.46mA   -378mA     -21.49mA
4.35V     -271.3mA   -548mA     -45.17mA
4.5V      -465mA     -717.9mA   -180.7mA
4.65V     -659mA     -887.9mA   -410.1mA
4.8V      -853.2mA   -1.058A    -639.3mA
6.6V      -3.217A    -3.13A     -3.442A
[Ramp]
| variable   typ   min   max
dV/dt_r 0.2467/0.2099e-9   0.2303/0.2122e-9   0.2568/0.2121e-9
dV/dt_f 0.2364/0.3859e-9   0.2225/0.3844e-9   0.2433/0.3802e-9
R_load = 50
[Rising waveform]
R_fixture= 50
V_fixture= 0.587498
V_fixture_min= 0.553047
V_fixture_max= 0.627253
|Time   V(typ)   V(min)   V(max)
0s        406.9mV    395.1mV    436.8mV
1.07ns    406.9mV    395.1mV    443mV
1.19ns    407.5mV    395.1mV    410.2mV
1.24ns    410.4mV    395.1mV    443.4mV
1.44ns    392.8mV    395.4mV    725.6mV
1.68ns    694.6mV    377.2mV    803mV
1.77ns    736.4mV    392.2mV    811.5mV
1.98ns    775.2mV    645.3mV    823.8mV
2.16ns    783.6mV    730mV      829mV
4ns       794mV      758.3mV    835.9mV
[Falling waveform]
R_fixture= 50
V_fixture= 0.587498
V_fixture_min= 0.553047
V_fixture_max= 0.627253
|Time   V(typ)   V(min)   V(max)
0s        793.7mV    758.6mV    835.6mV
1.09ns    793.7mV    758.6mV    842.1mV
1.16ns    793.5mV    758.6mV    812.2mV
1.24ns    798.2mV    758.6mV    663.7mV
1.3ns     798.8mV    758.6mV    622.7mV
1.49ns    604.8mV    761.3mV    543.6mV
1.6ns     548.6mV    759.8mV    509.9mV
1.93ns    456.7mV    513.3mV    461.1mV
2.63ns    412.9mV    406.1mV    441mV
4ns       407.3mV    395.3mV    437.2mV
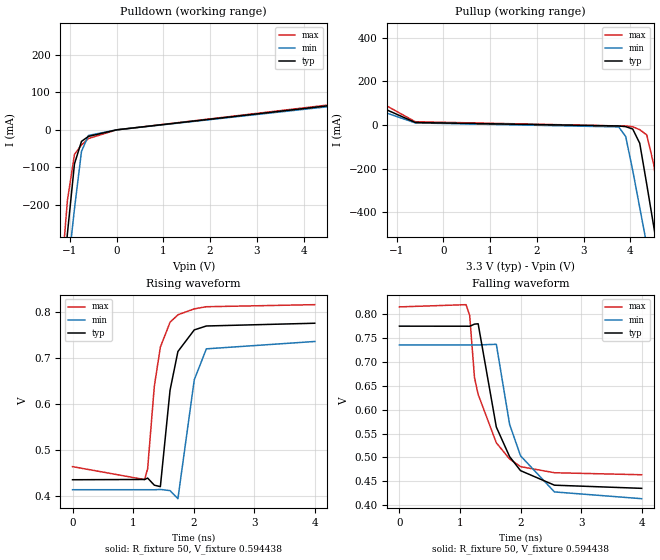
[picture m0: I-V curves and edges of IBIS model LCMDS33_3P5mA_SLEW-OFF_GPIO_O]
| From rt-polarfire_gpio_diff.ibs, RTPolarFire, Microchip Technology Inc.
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|   Model LCMDS33_3P5mA_SLEW-OFF_GPIO_O
[Model]   LCMDS33_3P5mA_SLEW-OFF_GPIO_O
Model_type   Output
Polarity   Non-Inverting
Enable   Active-High
Vmeas =   0.6
Cref =   5p
Rref =   100
|   typ   min   max
C_comp_pullup   2.605e-12   2.605e-12   2.76e-12
C_comp_pulldown  2.605e-12   2.605e-12   2.76e-12
[Temperature Range]  25C   125C   -55C
[Voltage Range]  3.3   3.15   3.45
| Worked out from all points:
|   slope of the pulldown table from 0 to 0.495 V, typ, clamps not added: 127 ohm
|   slope of the pullup table from 0 to 0.495 V, typ, clamps not added: 154 ohm
|   rising waveform, R_fixture 50, V_fixture 0.594438: 20-80 % time 204ps typ, 207ps min, 214ps max; typ from 0.435 V to 0.775 V
|   falling waveform, R_fixture 50, V_fixture 0.594438: 20-80 % time 404ps typ, 408ps min, 394ps max; typ from 0.775 V to 0.435 V
[Pulldown]
|Voltage   I(typ)   I(min)   I(max)
-3.3V     -3.224A    -2.962A    -3.688A
-1.2V     -469mA     -550.4mA   -416.2mA
-1.05V    -275mA     -380.1mA   -186.6mA
-900mV    -90.59mA   -210mA     -65.27mA
-750mV    -30.68mA   -57.32mA   -40.1mA
-600mV    -17.41mA   -14.83mA   -23.11mA
0V        -35.48uA   -30.6uA    -43.51uA
4.65V     65.77mA    63.31mA    67.9mA
5.1V      118.2mA    106.9mA    125.3mA
6V        247.9mA    218.8mA    275.5mA
6.15V     272.4mA    240.1mA    302.9mA
6.6V      351.8mA    306.9mA    390mA
[Pullup]
|Voltage   I(typ)   I(min)   I(max)
-3.3V     377.7mA    308.3mA    447.7mA
-1.65V    111.5mA    87.38mA    139.6mA
-600mV    11.93mA    10.14mA    15.58mA
3.75V     -3.874mA   -8.227mA   -3.716mA
3.9V      -7.032mA   -52.2mA    -3.899mA
4.05V     -17.8mA    -207.7mA   -7.41mA
4.2V      -83.02mA   -377.6mA   -20.99mA
4.35V     -270.9mA   -547.6mA   -44.67mA
4.5V      -464.6mA   -717.4mA   -180.2mA
4.65V     -658.6mA   -887.4mA   -409.6mA
4.8V      -852.7mA   -1.058A    -638.9mA
6.6V      -3.216A    -3.13A     -3.442A
[Ramp]
| variable   typ   min   max
dV/dt_r 0.2201/0.2070e-9   0.2068/0.2116e-9   0.2289/0.2138e-9
dV/dt_f 0.2085/0.4013e-9   0.1978/0.4059e-9   0.2155/0.3916e-9
R_load = 50
[Rising waveform]
R_fixture= 50
V_fixture= 0.594438
V_fixture_min= 0.555667
V_fixture_max= 0.632869
|Time   V(typ)   V(min)   V(max)
0s        434.8mV    413.1mV    463.3mV
1.19ns    435.4mV    413.1mV    435.2mV
1.24ns    438.4mV    413.1mV    458.8mV
1.35ns    423mV      413mV      638mV
1.45ns    419.8mV    413.7mV    723.3mV
1.61ns    629.5mV    411.1mV    777.4mV
1.74ns    713.8mV    393.6mV    793.7mV
2.01ns    760.8mV    652.2mV    806.6mV
2.21ns    769.3mV    719.6mV    811.2mV
4ns       775.3mV    735.6mV    815.7mV
[Falling waveform]
R_fixture= 50
V_fixture= 0.594438
V_fixture_min= 0.555667
V_fixture_max= 0.632869
|Time   V(typ)   V(min)   V(max)
0s        775.2mV    735.8mV    815.6mV
1.1ns     775.1mV    735.8mV    820.3mV
1.16ns    775mV      735.8mV    798mV
1.24ns    779.5mV    735.8mV    667mV
1.3ns     780.2mV    735.8mV    632.1mV
1.6ns     563.6mV    737.2mV    530.6mV
1.82ns    501.5mV    569mV      496.6mV
2ns       472.2mV    503.3mV    480.6mV
2.56ns    441.7mV    427.6mV    467.8mV
4ns       435.1mV    413.4mV    463.6mV
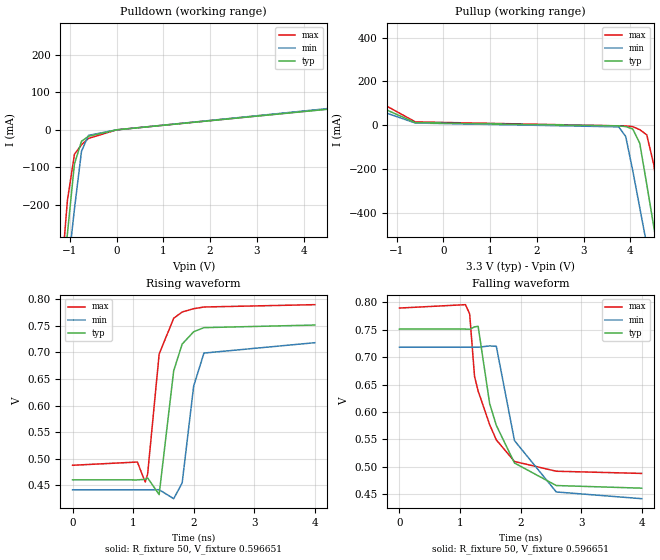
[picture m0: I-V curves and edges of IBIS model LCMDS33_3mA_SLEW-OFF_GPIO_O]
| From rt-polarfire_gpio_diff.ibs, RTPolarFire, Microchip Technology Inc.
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|   Model LCMDS33_3mA_SLEW-OFF_GPIO_O
[Model]   LCMDS33_3mA_SLEW-OFF_GPIO_O
Model_type   Output
Polarity   Non-Inverting
Enable   Active-High
Vmeas =   0.6
Cref =   5p
Rref =   100
|   typ   min   max
C_comp_pullup   2.605e-12   2.605e-12   2.76e-12
C_comp_pulldown  2.605e-12   2.605e-12   2.76e-12
[Temperature Range]  25C   125C   -55C
[Voltage Range]  3.3   3.15   3.45
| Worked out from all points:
|   slope of the pulldown table from 0 to 0.495 V, typ, clamps not added: 177 ohm
|   slope of the pullup table from 0 to 0.495 V, typ, clamps not added: 176 ohm
|   rising waveform, R_fixture 50, V_fixture 0.596651: 20-80 % time 208ps typ, 209ps min, 210ps max; typ from 0.46 V to 0.751 V
|   falling waveform, R_fixture 50, V_fixture 0.596651: 20-80 % time 416ps typ, 429ps min, 408ps max; typ from 0.751 V to 0.461 V
[Pulldown]
|Voltage   I(typ)   I(min)   I(max)
-3.3V     -3.224A    -2.962A    -3.688A
-1.2V     -468.9mA   -550.3mA   -416mA
-1.05V    -274.9mA   -380mA     -186.5mA
-900mV    -90.41mA   -209.9mA   -64.92mA
-750mV    -30.43mA   -57.17mA   -39.77mA
-600mV    -17.17mA   -14.65mA   -22.8mA
0V        -34.4uA    -29.88uA   -42.15uA
4.5V      54.61mA    56.28mA    55.29mA
5.1V      117.7mA    106.4mA    124.8mA
6V        247.4mA    218.2mA    274.9mA
6.15V     271.8mA    239.5mA    302.3mA
6.6V      351.1mA    306.2mA    389.3mA
[Pullup]
|Voltage   I(typ)   I(min)   I(max)
-3.3V     377.5mA    308.2mA    447.5mA
-1.65V    110.9mA    87.15mA    138.8mA
-600mV    11.46mA    9.784mA    14.98mA
3.75V     -3.354mA   -7.718mA   -3.188mA
3.9V      -6.518mA   -51.72mA   -3.372mA
4.05V     -17.29mA   -207.3mA   -6.89mA
4.2V      -82.56mA   -377.2mA   -20.47mA
4.35V     -270.4mA   -547.1mA   -44.16mA
4.5V      -464.2mA   -717mA     -179.8mA
4.65V     -658.1mA   -887mA     -409.2mA
4.8V      -852.3mA   -1.057A    -638.4mA
6.6V      -3.216A    -3.129A    -3.441A
[Ramp]
| variable   typ   min   max
dV/dt_r 0.1920/0.2118e-9   0.1809/0.2165e-9   0.2005/0.2106e-9
dV/dt_f 0.1784/0.4137e-9   0.1700/0.4259e-9   0.1851/0.4044e-9
R_load = 50
[Rising waveform]
R_fixture= 50
V_fixture= 0.596651
V_fixture_min= 0.564122
V_fixture_max= 0.633370
|Time   V(typ)   V(min)   V(max)
0s        460.4mV    441.7mV    487.8mV
1.07ns    460.3mV    441.7mV    493.9mV
1.2ns     461.4mV    441.7mV    456.3mV
1.24ns    464mV      441.7mV    471.4mV
1.43ns    432.7mV    441.9mV    696.7mV
1.67ns    665.3mV    425mV      764.2mV
1.81ns    715.6mV    454.5mV    775.9mV
2ns       738.8mV    636.6mV    782.1mV
2.17ns    746.5mV    698.7mV    785.3mV
4ns       751.4mV    718.2mV    789.7mV
[Falling waveform]
R_fixture= 50
V_fixture= 0.596651
V_fixture_min= 0.564122
V_fixture_max= 0.633370
|Time   V(typ)   V(min)   V(max)
0s        751.4mV    718.4mV    789.8mV
1.09ns    751.4mV    718.4mV    796mV
1.16ns    751.2mV    718.4mV    779.1mV
1.24ns    755.5mV    718.4mV    665.4mV
1.3ns     756.4mV    718.4mV    638.3mV
1.49ns    615.4mV    720.7mV    577mV
1.6ns     575.7mV    720mV      549.2mV
1.9ns     507mV      547.9mV    509.8mV
2.59ns    465.9mV    454.2mV    492mV
4ns       461.1mV    441.9mV    488mV
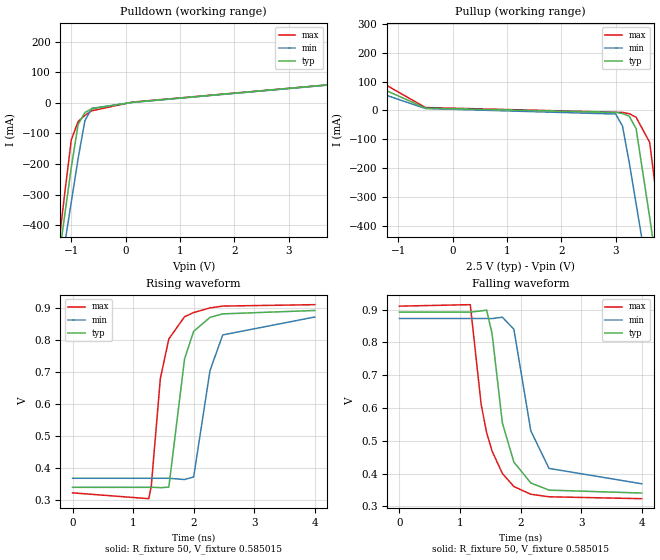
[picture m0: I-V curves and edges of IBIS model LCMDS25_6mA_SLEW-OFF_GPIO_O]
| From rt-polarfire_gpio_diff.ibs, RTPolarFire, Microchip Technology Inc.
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|   Model LCMDS25_6mA_SLEW-OFF_GPIO_O
[Model]   LCMDS25_6mA_SLEW-OFF_GPIO_O
Model_type   Output
Polarity   Non-Inverting
Enable   Active-High
Vmeas =   0.6
Cref =   5p
Rref =   100
|   typ   min   max
C_comp_pullup   2.605e-12   2.605e-12   2.76e-12
C_comp_pulldown  2.605e-12   2.605e-12   2.76e-12
[Temperature Range]  25C   125C   -55C
[Voltage Range]  2.5   2.375   2.625
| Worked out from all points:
|   slope of the pulldown table from 0 to 0.375 V, typ, clamps not added: 71.4 ohm
|   slope of the pullup table from 0 to 0.375 V, typ, clamps not added: 103 ohm
|   rising waveform, R_fixture 50, V_fixture 0.585015: 20-80 % time 245ps typ, 282ps min, 231ps max; typ from 0.34 V to 0.893 V
|   falling waveform, R_fixture 50, V_fixture 0.585015: 20-80 % time 291ps typ, 320ps min, 317ps max; typ from 0.893 V to 0.341 V
[Pulldown]
|Voltage   I(typ)   I(min)   I(max)
-2.5V     -2.164A    -2.035A    -2.425A
-1.25V    -533.9mA   -607.3mA   -492.9mA
-1.125V   -372.1mA   -465.5mA   -301.4mA
-1V       -210.6mA   -323.6mA   -120.4mA
-875mV    -70.44mA   -181.9mA   -60.88mA
-750mV    -31.07mA   -57.69mA   -40.58mA
-625mV    -19.5mA    -17.6mA    -25.78mA
125mV     2.146mA    1.678mA    2.834mA
3.75V     59.74mA    58.91mA    59.58mA
3.875V    69.99mA    65.17mA    73.84mA
4.375V    128.6mA    113.4mA    141mA
5V        216.7mA    188.2mA    244.5mA
[Pullup]
|Voltage   I(typ)   I(min)   I(max)
-2.5V     231.4mA    183.1mA    285.4mA
-1.5V     92.41mA    70.59mA    117.7mA
-500mV    8.252mA    6.469mA    10.09mA
3V        -6.861mA   -12.53mA   -6.329mA
3.125V    -10.73mA   -54.31mA   -6.936mA
3.25V     -20.31mA   -181.5mA   -11.41mA
3.375V    -62.71mA   -323mA     -23.53mA
3.625V    -369.9mA   -606.2mA   -110.4mA
3.75V     -531.4mA   -747.8mA   -297.1mA
3.875V    -693.1mA   -889.5mA   -488.2mA
4V        -854.9mA   -1.031A    -679.3mA
5V        -2.159A    -2.177A    -2.222A
[Ramp]
| variable   typ   min   max
dV/dt_r 0.3404/0.2472e-9   0.3089/0.2846e-9   0.3648/0.2307e-9
dV/dt_f 0.3362/0.2921e-9   0.3077/0.3214e-9   0.3566/0.3162e-9
R_load = 50
[Rising waveform]
R_fixture= 50
V_fixture= 0.585015
V_fixture_min= 0.585090
V_fixture_max= 0.598333
|Time   V(typ)   V(min)   V(max)
0s        340.5mV    368.8mV    323.2mV
1.26ns    340.5mV    368.8mV    305mV
1.3ns     340.9mV    368.8mV    344.9mV
1.45ns    339.4mV    368.8mV    680.8mV
1.59ns    341.1mV    368.8mV    804.3mV
1.85ns    742.3mV    364.9mV    873.8mV
2ns       828.1mV    373mV      886.7mV
2.27ns    871.7mV    705.7mV    901.2mV
2.48ns    882.6mV    816.8mV    907mV
4ns       893.2mV    872.8mV    911.4mV
[Falling waveform]
R_fixture= 50
V_fixture= 0.585015
V_fixture_min= 0.585090
V_fixture_max= 0.598333
|Time   V(typ)   V(min)   V(max)
0s        892.6mV    873mV      910.7mV
1.17ns    892.6mV    873mV      915.2mV
1.35ns    896.1mV    873mV      610.3mV
1.44ns    898.5mV    873mV      525.1mV
1.53ns    826.6mV    872.8mV    468.7mV
1.7ns     554.4mV    876.9mV    400.5mV
1.89ns    435.2mV    840.4mV    360.6mV
2.17ns    371.5mV    530.4mV    337.1mV
2.47ns    349.7mV    415.9mV    329.4mV
4ns       340.8mV    369.1mV    323.6mV
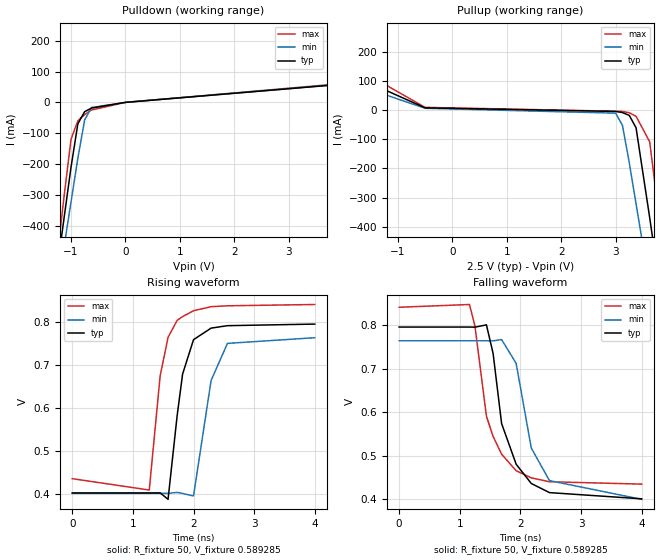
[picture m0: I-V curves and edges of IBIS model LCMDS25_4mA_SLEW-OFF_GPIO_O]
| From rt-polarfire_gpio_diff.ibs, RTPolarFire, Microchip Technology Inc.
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|   Model LCMDS25_4mA_SLEW-OFF_GPIO_O
[Model]   LCMDS25_4mA_SLEW-OFF_GPIO_O
Model_type   Output
Polarity   Non-Inverting
Enable   Active-High
Vmeas =   0.6
Cref =   5p
Rref =   100
|   typ   min   max
C_comp_pullup   2.605e-12   2.605e-12   2.76e-12
C_comp_pulldown  2.605e-12   2.605e-12   2.76e-12
[Temperature Range]  25C   125C   -55C
[Voltage Range]  2.5   2.375   2.625
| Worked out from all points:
|   slope of the pulldown table from 0 to 0.375 V, typ, clamps not added: 101 ohm
|   slope of the pullup table from 0 to 0.375 V, typ, clamps not added: 130 ohm
|   rising waveform, R_fixture 50, V_fixture 0.589285: 20-80 % time 224ps typ, 252ps min, 221ps max; typ from 0.402 V to 0.795 V
|   falling waveform, R_fixture 50, V_fixture 0.589285: 20-80 % time 366ps typ, 363ps min, 365ps max; typ from 0.795 V to 0.401 V
[Pulldown]
|Voltage   I(typ)   I(min)   I(max)
-2.5V     -2.163A    -2.035A    -2.424A
-1.25V    -533.5mA   -606.9mA   -492.5mA
-1.125V   -371.8mA   -465.1mA   -301mA
-1V       -210.2mA   -323.2mA   -119.7mA
-875mV    -69.72mA   -181.5mA   -59.87mA
-750mV    -30.23mA   -57mA      -39.61mA
-625mV    -18.72mA   -16.78mA   -24.87mA
0V        -35.98uA   -31.13uA   -44.56uA
3.75V     55.42mA    55.72mA    57.47mA
3.875V    67.66mA    61.98mA    71.74mA
4.375V    126.3mA    110.1mA    138.9mA
5V        214.3mA    184.8mA    242.3mA
[Pullup]
|Voltage   I(typ)   I(min)   I(max)
-2.5V     229.7mA    182.7mA    282.7mA
-1.5V     90.63mA    69.35mA    115.4mA
-500mV    7.428mA    5.919mA    9.02mA
3V        -4.82mA    -10.74mA   -4.244mA
3.125V    -8.703mA   -52.63mA   -4.86mA
3.25V     -18.3mA    -179.9mA   -9.36mA
3.375V    -60.85mA   -321.4mA   -21.49mA
3.625V    -368.1mA   -604.6mA   -108.6mA
3.75V     -529.7mA   -746.2mA   -295.4mA
3.875V    -691.4mA   -887.9mA   -486.5mA
4V        -853.2mA   -1.03A     -677.5mA
5V        -2.158A    -2.175A    -2.22A
[Ramp]
| variable   typ   min   max
dV/dt_r 0.2475/0.2268e-9   0.2270/0.2585e-9   0.2603/0.2221e-9
dV/dt_f 0.2408/0.3646e-9   0.2229/0.3651e-9   0.2476/0.3632e-9
R_load = 50
[Rising waveform]
R_fixture= 50
V_fixture= 0.589285
V_fixture_min= 0.561204
V_fixture_max= 0.632521
|Time   V(typ)   V(min)   V(max)
0s        401.5mV    400.6mV    434.8mV
1.27ns    401.5mV    400.6mV    408.3mV
1.45ns    401.7mV    400.5mV    675mV
1.58ns    386.6mV    400.5mV    764.4mV
1.73ns    581.7mV    402.8mV    804.1mV
1.82ns    678.9mV    400.3mV    812.9mV
2ns       759mV      394.4mV    826.5mV
2.29ns    786mV      663.9mV    836mV
2.56ns    791.7mV    750.4mV    838.1mV
4ns       795.4mV    763.6mV    841.1mV
[Falling waveform]
R_fixture= 50
V_fixture= 0.589285
V_fixture_min= 0.561204
V_fixture_max= 0.632521
|Time   V(typ)   V(min)   V(max)
0s        795.4mV    763.9mV    840.8mV
1.16ns    795.4mV    763.9mV    847.1mV
1.25ns    795.1mV    763.9mV    797.9mV
1.44ns    800.4mV    763.9mV    590.7mV
1.55ns    734.8mV    763.7mV    544.7mV
1.69ns    574.2mV    766.7mV    503.8mV
1.93ns    480.8mV    712.1mV    465.9mV
2.18ns    436.6mV    517.8mV    449.6mV
2.48ns    415.7mV    443.2mV    440.6mV
4ns       401.5mV    400.3mV    435.2mV
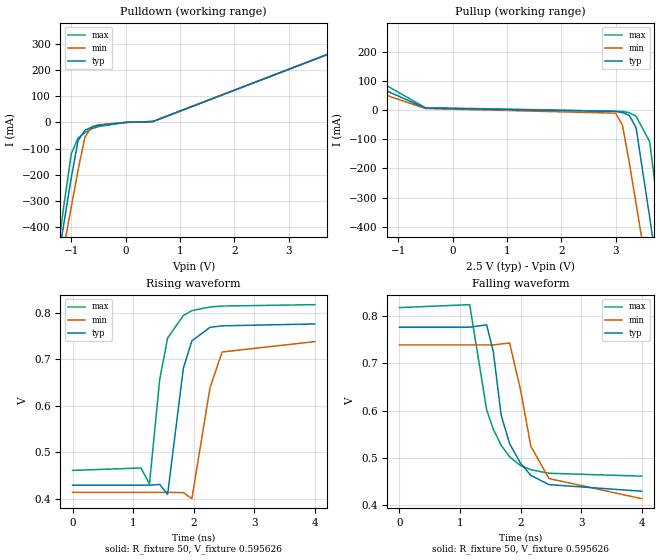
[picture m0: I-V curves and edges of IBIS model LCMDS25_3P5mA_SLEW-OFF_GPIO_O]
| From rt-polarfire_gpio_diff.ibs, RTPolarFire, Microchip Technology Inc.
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|   Model LCMDS25_3P5mA_SLEW-OFF_GPIO_O
[Model]   LCMDS25_3P5mA_SLEW-OFF_GPIO_O
Model_type   Output
Polarity   Non-Inverting
Enable   Active-High
Vmeas =   0.6
Cref =   5p
Rref =   100
|   typ   min   max
C_comp_pullup   2.605e-12   2.605e-12   2.76e-12
C_comp_pulldown  2.605e-12   2.605e-12   2.76e-12
[Temperature Range]  25C   125C   -55C
[Voltage Range]  2.5   2.375   2.625
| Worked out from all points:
|   slope of the pulldown table from 0 to 0.375 V, typ, clamps not added: 115 ohm
|   slope of the pullup table from 0 to 0.375 V, typ, clamps not added: 141 ohm
|   rising waveform, R_fixture 50, V_fixture 0.595626: 20-80 % time 210ps typ, 244ps min, 216ps max; typ from 0.429 V to 0.776 V
|   falling waveform, R_fixture 50, V_fixture 0.595626: 20-80 % time 373ps typ, 375ps min, 373ps max; typ from 0.776 V to 0.43 V
[Pulldown]
|Voltage   I(typ)   I(min)   I(max)
-2.5V     -2.163A    -2.035A    -2.424A
-1.25V    -533.4mA   -606.8mA   -492.4mA
-1.125V   -371.7mA   -465mA     -300.9mA
-1V       -210.2mA   -323.1mA   -119.5mA
-875mV    -69.53mA   -181.5mA   -59.58mA
-750mV    -30.01mA   -56.87mA   -39.32mA
-625mV    -18.51mA   -16.63mA   -24.6mA
-500mV    -11.82mA   -9.151mA   -16.2mA
0V        -35.14uA   -30.14uA   -43.36uA
500mV     3.412mA    3.092mA    3.519mA
5V        363mA      363mA      363mA
[Pullup]
|Voltage   I(typ)   I(min)   I(max)
-2.5V     229.5mA    182.6mA    282.1mA
-1.5V     90.13mA    69.04mA    114.7mA
-500mV    7.143mA    5.725mA    8.651mA
3V        -4.314mA   -10.26mA   -3.73mA
3.125V    -8.203mA   -52.18mA   -4.349mA
3.25V     -17.8mA    -179.4mA   -8.857mA
3.375V    -60.39mA   -320.9mA   -20.98mA
3.625V    -367.7mA   -604.2mA   -108.2mA
3.75V     -529.2mA   -745.7mA   -294.9mA
3.875V    -690.9mA   -887.4mA   -486.1mA
4V        -852.7mA   -1.029A    -677.1mA
5V        -2.157A    -2.175A    -2.22A
[Ramp]
| variable   typ   min   max
dV/dt_r 0.2203/0.2133e-9   0.2054/0.2547e-9   0.2319/0.2179e-9
dV/dt_f 0.2124/0.3700e-9   0.1996/0.3776e-9   0.2179/0.3709e-9
R_load = 50
[Rising waveform]
R_fixture= 50
V_fixture= 0.595626
V_fixture_min= 0.560112
V_fixture_max= 0.635056
|Time   V(typ)   V(min)   V(max)
0s        429.3mV    413.9mV    461.1mV
1.13ns    429.3mV    413.9mV    466.3mV
1.27ns    429.3mV    413.9mV    431.9mV
1.44ns    430.8mV    413.9mV    657.9mV
1.57ns    409.5mV    413.9mV    746.1mV
1.83ns    681mV      413.2mV    794.7mV
1.97ns    739.8mV    400.2mV    804.9mV
2.27ns    769.1mV    639mV      813mV
2.47ns    772.3mV    716mV      814.9mV
4ns       776.4mV    738.4mV    817.9mV
[Falling waveform]
R_fixture= 50
V_fixture= 0.595626
V_fixture_min= 0.560112
V_fixture_max= 0.635056
|Time   V(typ)   V(min)   V(max)
0s        776.4mV    738.9mV    817.8mV
1.16ns    776.4mV    738.9mV    824mV
1.44ns    781.3mV    738.9mV    601.8mV
1.55ns    725.1mV    738.7mV    560.7mV
1.68ns    590.3mV    740.9mV    526.5mV
1.82ns    529.9mV    742.8mV    502.1mV
2ns       488.7mV    644.1mV    483.7mV
2.17ns    463mV      524.7mV    475mV
2.47ns    443.4mV    456.3mV    467.4mV
4ns       429.5mV    413.7mV    461.4mV
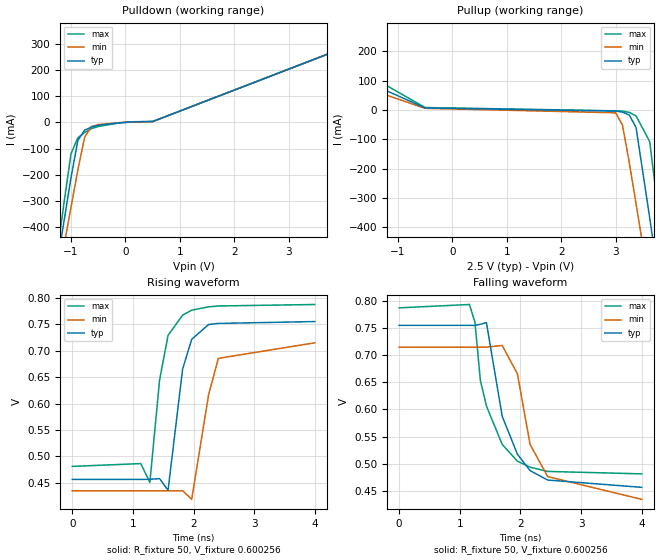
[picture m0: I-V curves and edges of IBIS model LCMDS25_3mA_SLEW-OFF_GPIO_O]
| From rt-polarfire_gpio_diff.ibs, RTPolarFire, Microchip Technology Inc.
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|   Model LCMDS25_3mA_SLEW-OFF_GPIO_O
[Model]   LCMDS25_3mA_SLEW-OFF_GPIO_O
Model_type   Output
Polarity   Non-Inverting
Enable   Active-High
Vmeas =   0.6
Cref =   5p
Rref =   100
|   typ   min   max
C_comp_pullup   2.605e-12   2.605e-12   2.76e-12
C_comp_pulldown  2.605e-12   2.605e-12   2.76e-12
[Temperature Range]  25C   125C   -55C
[Voltage Range]  2.5   2.375   2.625
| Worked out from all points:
|   slope of the pulldown table from 0 to 0.375 V, typ, clamps not added: 133 ohm
|   slope of the pullup table from 0 to 0.375 V, typ, clamps not added: 158 ohm
|   rising waveform, R_fixture 50, V_fixture 0.600256: 20-80 % time 212ps typ, 237ps min, 213ps max; typ from 0.456 V to 0.755 V
|   falling waveform, R_fixture 50, V_fixture 0.600256: 20-80 % time 387ps typ, 387ps min, 384ps max; typ from 0.755 V to 0.457 V
[Pulldown]
|Voltage   I(typ)   I(min)   I(max)
-2.5V     -2.163A    -2.035A    -2.424A
-1.25V    -533.3mA   -606.7mA   -492.3mA
-1.125V   -371.6mA   -464.9mA   -300.8mA
-1V       -210.1mA   -323mA     -119.2mA
-875mV    -69.33mA   -181.4mA   -59.26mA
-750mV    -29.77mA   -56.73mA   -39.02mA
-625mV    -18.3mA    -16.45mA   -24.32mA
-500mV    -11.62mA   -8.992mA   -15.93mA
-125mV    -2.2mA     -1.608mA   -3.067mA
125mV     1.514mA    1.131mA    1.94mA
500mV     2.915mA    2.599mA    3.006mA
5V        362mA      362mA      363mA
[Pullup]
|Voltage   I(typ)   I(min)   I(max)
-2.5V     229.2mA    182.5mA    281.4mA
-1.5V     89.58mA    68.74mA    114mA
-500mV    6.795mA    5.489mA    8.199mA
3V        -3.797mA   -9.764mA   -3.203mA
3.125V    -7.691mA   -51.72mA   -3.824mA
3.25V     -17.29mA   -179mA     -8.338mA
3.375V    -59.92mA   -320.5mA   -20.47mA
3.625V    -367.3mA   -603.7mA   -107.7mA
3.75V     -528.8mA   -745.3mA   -294.5mA
3.875V    -690.5mA   -887mA     -485.6mA
4V        -852.3mA   -1.029A    -676.6mA
5V        -2.157A    -2.174A    -2.22A
[Ramp]
| variable   typ   min   max
dV/dt_r 0.1921/0.2163e-9   0.1801/0.2501e-9   0.2028/0.2155e-9
dV/dt_f 0.1833/0.3840e-9   0.1724/0.3901e-9   0.1876/0.3821e-9
R_load = 50
[Rising waveform]
R_fixture= 50
V_fixture= 0.600256
V_fixture_min= 0.561027
V_fixture_max= 0.63081
|Time   V(typ)   V(min)   V(max)
0s        456.4mV    434.7mV    481mV
1.13ns    456.4mV    434.7mV    486.3mV
1.28ns    456.6mV    434.7mV    450.6mV
1.44ns    457.9mV    434.7mV    644.4mV
1.58ns    435.8mV    434.7mV    729mV
1.82ns    665.1mV    435mV      767.2mV
1.97ns    721.4mV    418.7mV    776.6mV
2.25ns    749.5mV    617.3mV    782.9mV
2.41ns    751.5mV    685.4mV    784.5mV
4ns       755mV      714.8mV    787.3mV
[Falling waveform]
R_fixture= 50
V_fixture= 0.600256
V_fixture_min= 0.561027
V_fixture_max= 0.63081
|Time   V(typ)   V(min)   V(max)
0s        755mV      714.9mV    787.2mV
1.16ns    755mV      714.9mV    793.4mV
1.25ns    754.8mV    714.9mV    760.8mV
1.34ns    757mV      714.9mV    653.6mV
1.44ns    759.9mV    714.9mV    606.3mV
1.7ns     587.4mV    717.9mV    535.7mV
1.95ns    517.8mV    665.9mV    504.9mV
2.16ns    487.4mV    535.7mV    493.7mV
2.45ns    470mV      476.4mV    485.9mV
4ns       456.6mV    434.5mV    481.4mV
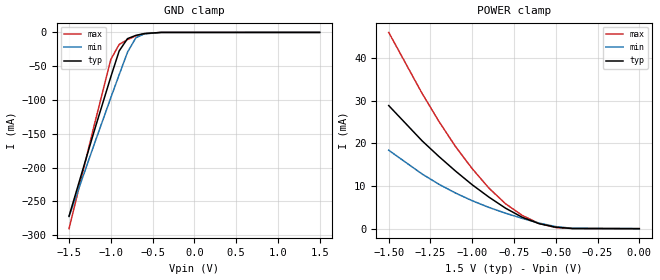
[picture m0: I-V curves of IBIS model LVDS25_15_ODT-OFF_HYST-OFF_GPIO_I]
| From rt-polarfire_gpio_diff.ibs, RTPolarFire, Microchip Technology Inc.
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|   Model LVDS25_15_ODT-OFF_HYST-OFF_GPIO_I
[Model]   LVDS25_15_ODT-OFF_HYST-OFF_GPIO_I
Model_type   Input
Vinl =   1.125
Vinh =   1.375
|   typ   min   max
C_comp_pullup   2.605e-12   2.605e-12   2.76e-12
C_comp_pulldown  2.605e-12   2.605e-12   2.76e-12
[Temperature Range]  25C   125C   -55C
[Voltage Range]  1.5   1.425   1.575
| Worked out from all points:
|   GND clamp passes 1 mA (typ) near -0.54 V on its own axis
|   POWER clamp passes 1 mA (typ) near -0.58 V on its own axis
[GND_clamp]
|Voltage   I(typ)   I(min)   I(max)
-1.5V     -271.7mA   -272.4mA   -290.3mA
-1.2V     -146.4mA   -165.9mA   -137.9mA
-1V       -65.7mA    -96.62mA   -40.05mA
-900mV    -27.42mA   -62.61mA   -17.84mA
-800mV    -9.225mA   -29.24mA   -10.57mA
-700mV    -4.388mA   -7.931mA   -5.239mA
-600mV    -1.737mA   -2.257mA   -1.848mA
-400mV    -40.61uA   -95.11uA   -27.52uA
1.5V      576.4nA    686.1nA    514.8nA
[POWER_clamp]
|Voltage   I(typ)   I(min)   I(max)
-1.5V     28.88mA    18.4mA     46.05mA
-1.3V     20.6mA     12.82mA    31.72mA
-1.2V     16.95mA    10.43mA    25.19mA
-1.1V     13.51mA    8.36mA     19.25mA
-1V       10.29mA    6.552mA    14.07mA
-900mV    7.398mA    4.981mA    9.508mA
-800mV    4.79mA     3.619mA    5.822mA
-700mV    2.654mA    2.403mA    3.095mA
-600mV    1.175mA    1.307mA    1.213mA
-500mV    340uA      481.9uA    268.3uA
-400mV    35.83uA    80.36uA    24.18uA
0V        0A         0A         0A
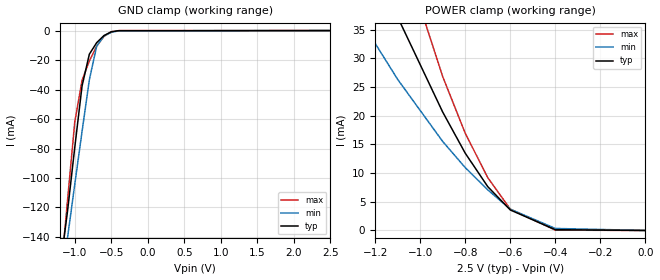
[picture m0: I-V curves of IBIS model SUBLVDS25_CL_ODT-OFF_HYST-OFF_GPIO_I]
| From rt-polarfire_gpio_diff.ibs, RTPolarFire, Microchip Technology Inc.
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|   Model SUBLVDS25_CL_ODT-OFF_HYST-OFF_GPIO_I
[Model]   SUBLVDS25_CL_ODT-OFF_HYST-OFF_GPIO_I
Model_type   Input
Vinl =   0.775
Vinh =   1.025
|   typ   min   max
C_comp_pullup   2.605e-12   2.605e-12   2.76e-12
C_comp_pulldown  2.605e-12   2.605e-12   2.76e-12
[Temperature Range]  25C   125C   -55C
[Voltage Range]  2.5   2.375   2.625
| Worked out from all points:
|   GND clamp passes 1 mA (typ) near -0.51 V on its own axis
|   POWER clamp passes 1 mA (typ) near -0.48 V on its own axis
[GND_clamp]
|Voltage   I(typ)   I(min)   I(max)
-1.9V     -487.4mA   -457.5mA   -585.9mA
-1.2V     -160.7mA   -178.2mA   -170.6mA
-1.1V     -122.9mA   -140.9mA   -115.6mA
-1V       -79.29mA   -104.3mA   -62.07mA
-900mV    -37.54mA   -68.37mA   -33.69mA
-800mV    -15.98mA   -33.32mA   -20.57mA
-700mV    -8.2mA     -10.56mA   -10.56mA
-600mV    -3.375mA   -3.672mA   -3.935mA
-500mV    -848.9uA   -1.164mA   -760.6uA
-400mV    -80.63uA   -204.2uA   -42.89uA
2.5V      1.001uA    1.433uA    853.7nA
[POWER_clamp]
|Voltage   I(typ)   I(min)   I(max)
-2.5V     229.2mA    166.9mA    313.7mA
-1.5V     78.88mA    54.95mA    113.3mA
-1.4V     67.48mA    46.92mA    96.27mA
-1.3V     56.73mA    39.47mA    80.06mA
-1.2V     46.63mA    32.6mA     64.91mA
-1.1V     37.17mA    26.32mA    51mA
-900mV    20.62mA    15.5mA     26.8mA
-800mV    13.46mA    10.95mA    16.93mA
-700mV    7.632mA    7.075mA    9.206mA
-600mV    3.576mA    3.711mA    3.714mA
-400mV    133.2uA    352.4uA    61.19uA
0V        0A         0A         0A
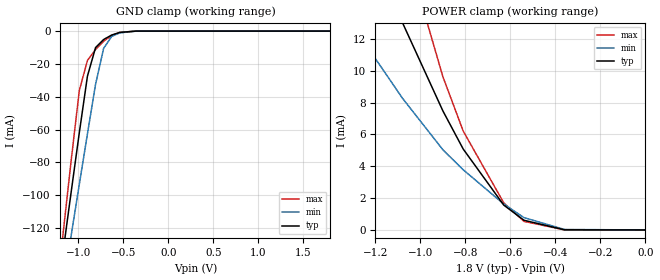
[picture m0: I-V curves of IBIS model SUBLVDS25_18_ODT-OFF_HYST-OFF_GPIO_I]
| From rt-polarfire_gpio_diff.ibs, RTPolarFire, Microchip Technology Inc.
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|   Model SUBLVDS25_18_ODT-OFF_HYST-OFF_GPIO_I
[Model]   SUBLVDS25_18_ODT-OFF_HYST-OFF_GPIO_I
Model_type   Input
Vinl =   0.775
Vinh =   1.025
|   typ   min   max
C_comp_pullup   2.605e-12   2.605e-12   2.76e-12
C_comp_pulldown  2.605e-12   2.605e-12   2.76e-12
[Temperature Range]  25C   125C   -55C
[Voltage Range]  1.8   1.71   1.89
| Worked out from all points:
|   GND clamp passes 1 mA (typ) near -0.55 V on its own axis
|   POWER clamp passes 1 mA (typ) near -0.58 V on its own axis
[GND_clamp]
|Voltage   I(typ)   I(min)   I(max)
-1.8V     -400.9mA   -382.4mA   -447.7mA
-1.17V    -134.2mA   -155.4mA   -123.1mA
-1.08V    -97.7mA    -124.2mA   -78.5mA
-990mV    -61.78mA   -93.22mA   -36.09mA
-900mV    -27.45mA   -62.63mA   -17.88mA
-810mV    -10.06mA   -32.48mA   -11.23mA
-720mV    -5.122mA   -10.52mA   -6.17mA
-630mV    -2.387mA   -3.217mA   -2.663mA
-540mV    -812.6uA   -1.096mA   -764.3uA
-360mV    -11.27uA   -36.3uA    -5.712uA
1.8V      703.8nA    850.3nA    616.2nA
[POWER_clamp]
|Voltage   I(typ)   I(min)   I(max)
-1.8V     43.47mA    29.04mA    69.07mA
-1.53V    30.5mA     19.63mA    49.01mA
-1.44V    26.56mA    16.86mA    42.22mA
-1.26V    19.47mA    11.97mA    29.38mA
-1.17V    16.17mA    10.13mA    23.67mA
-1.08V    13.01mA    8.267mA    18.34mA
-900mV    7.463mA    5.029mA    9.603mA
-810mV    5.079mA    3.779mA    6.207mA
-630mV    1.563mA    1.63mA     1.705mA
-540mV    609.2uA    775.7uA    539.6uA
-360mV    10.61uA    31.35uA    5.839uA
0V        0A         0A         0A
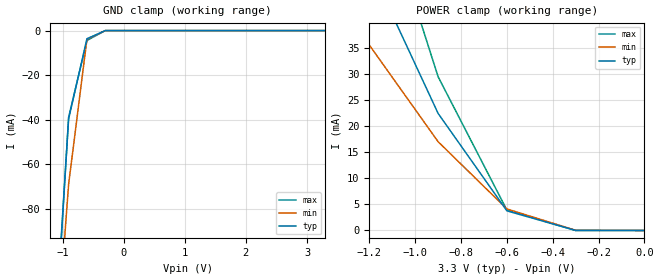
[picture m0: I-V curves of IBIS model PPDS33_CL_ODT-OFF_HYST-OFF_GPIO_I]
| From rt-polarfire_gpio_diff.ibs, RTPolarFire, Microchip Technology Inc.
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|   Model PPDS33_CL_ODT-OFF_HYST-OFF_GPIO_I
[Model]   PPDS33_CL_ODT-OFF_HYST-OFF_GPIO_I
Model_type   Input
Vinl =   0.675
Vinh =   0.925
|   typ   min   max
C_comp_pullup   2.605e-12   2.605e-12   2.76e-12
C_comp_pulldown  2.605e-12   2.605e-12   2.76e-12
[Temperature Range]  25C   125C   -55C
[Voltage Range]  3.3   3.15   3.45
[GND_clamp]
|Voltage   I(typ)   I(min)   I(max)
-1.8V     -463.2mA   -403.4mA   -537.2mA
-1.2V     -171.2mA   -180mA     -176.7mA
-900mV    -39.7mA    -69.11mA   -38.98mA
-600mV    -3.657mA   -3.84mA    -4.435mA
-300mV    -2.517uA   -17.73uA   -530.4nA
3.3V      1.341uA    2.115uA    1.126uA
[POWER_clamp]
|Voltage   I(typ)   I(min)   I(max)
-3.3V     410.6mA    321.6mA    524mA
-3V       342.4mA    264.8mA    450.1mA
-2.7V     283.6mA    213mA      379.6mA
-2.4V     228.4mA    167.6mA    310.2mA
-2.1V     176.1mA    126.8mA    243.9mA
-1.8V     128.3mA    90.83mA    182.1mA
-1.5V     86.43mA    60.31mA    123.8mA
-1.2V     50.84mA    35.58mA    70.87mA
-900mV    22.47mA    17.04mA    29.51mA
-600mV    3.773mA    4.134mA    3.924mA
-300mV    6.226uA    35.4uA     2.384uA
0V        0A         0A         0A
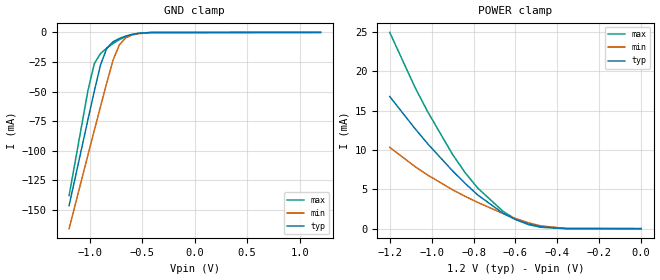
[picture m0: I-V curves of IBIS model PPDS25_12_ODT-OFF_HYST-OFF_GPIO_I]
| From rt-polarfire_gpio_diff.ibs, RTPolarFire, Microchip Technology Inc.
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|   Model PPDS25_12_ODT-OFF_HYST-OFF_GPIO_I
[Model]   PPDS25_12_ODT-OFF_HYST-OFF_GPIO_I
Model_type   Input
Vinl =   0.675
Vinh =   0.925
|   typ   min   max
C_comp_pullup   2.605e-12   2.605e-12   2.76e-12
C_comp_pulldown  2.605e-12   2.605e-12   2.76e-12
[Temperature Range]  25C   125C   -55C
[Voltage Range]  1.2   1.14   1.26
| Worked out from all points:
|   GND clamp passes 1 mA (typ) near -0.55 V on its own axis
|   POWER clamp passes 1 mA (typ) near -0.58 V on its own axis
[GND_clamp]
|Voltage   I(typ)   I(min)   I(max)
-1.2V     -146.3mA   -165.8mA   -137.8mA
-1.02V    -73.6mA    -103.5mA   -49.07mA
-960mV    -49.88mA   -82.94mA   -26.52mA
-900mV    -27.4mA    -62.59mA   -17.8mA
-840mV    -13.44mA   -42.44mA   -13.19mA
-780mV    -7.876mA   -23.29mA   -9.335mA
-720mV    -5.095mA   -10.5mA    -6.138mA
-660mV    -3.139mA   -4.633mA   -3.63mA
-600mV    -1.73mA    -2.25mA    -1.84mA
-540mV    -803.3uA   -1.085mA   -755.1uA
-420mV    -71.33uA   -146.7uA   -51.8uA
1.2V      449.6nA    526.9nA    413nA
[POWER_clamp]
|Voltage   I(typ)   I(min)   I(max)
-1.2V     16.81mA    10.34mA    24.97mA
-1.08V    12.75mA    7.914mA    18.01mA
-1.02V    10.84mA    6.839mA    14.93mA
-900mV    7.347mA    4.943mA    9.436mA
-840mV    5.757mA    4.109mA    7.118mA
-780mV    4.286mA    3.342mA    5.165mA
-660mV    1.966mA    1.93mA     2.22mA
-600mV    1.165mA    1.297mA    1.201mA
-540mV    595.8uA    760.8uA    525.7uA
-480mV    238.4uA    359.9uA    179.8uA
-360mV    9.858uA    29.84uA    5.257uA
0V        0A         0A         0A
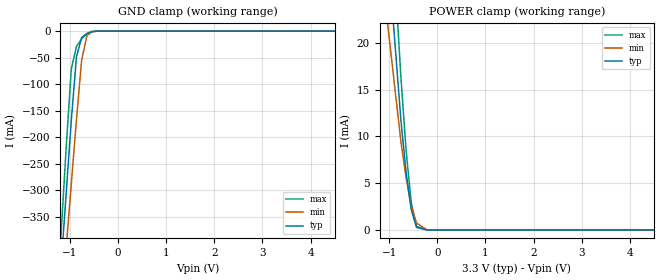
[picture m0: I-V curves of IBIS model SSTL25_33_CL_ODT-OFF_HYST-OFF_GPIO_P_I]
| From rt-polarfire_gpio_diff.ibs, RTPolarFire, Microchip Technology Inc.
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|   Model SSTL25_33_CL_ODT-OFF_HYST-OFF_GPIO_P_I
[Model]   SSTL25_33_CL_ODT-OFF_HYST-OFF_GPIO_P_I
Model_type   Input
Vinl =   1.1
Vinh =   1.4
|   typ   min   max
C_comp_pullup   2.605e-12   2.605e-12   2.76e-12
C_comp_pulldown  2.605e-12   2.605e-12   2.76e-12
[Temperature Range]  25C   125C   -55C
[Voltage Range]  3.3   3.135   3.465
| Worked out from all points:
|   GND clamp passes 1 mA (typ) near -0.55 V on its own axis
|   POWER clamp passes 1 mA (typ) near -0.48 V on its own axis
[GND Clamp]
| Voltage   I(typ)   I(min)   I(max)
-3.3V     -3.213A    -2.952A    -3.676A
-1.408V   -729.5mA   -779.3mA   -722.3mA
-1.083V   -308.8mA   -411.3mA   -222.9mA
-974.5mV  -168.6mA   -288.5mA   -71.36mA
-866.2mV  -47.95mA   -165.8mA   -28.75mA
-758mV    -12.25mA   -53.96mA   -14.52mA
-649.7mV  -4.29mA    -8.694mA   -5.098mA
-541.4mV  -856.5uA   -1.234mA   -956.1uA
-433.1mV  -54.68uA   -117.6uA   -52.81uA
6.6V      0A         0A         0A
[POWER Clamp]
| Voltage   I(typ)   I(min)   I(max)
-3.3V     269.6mA    207.9mA    330.9mA
-1.516V   67.8mA     49.84mA    87.75mA
-1.408V   58.45mA    43mA       75.97mA
-1.299V   49.71mA    36.49mA    64.88mA
-1.191V   41.64mA    30.17mA    54.55mA
-1.083V   33.36mA    24.27mA    44.28mA
-758mV    11.75mA    9.462mA    16.36mA
-649.7mV  6.134mA    5.589mA    8.485mA
-541.4mV  2.135mA    2.546mA    2.852mA
-433.1mV  274.1uA    756.9uA    392.2uA
-216.6mV  99.06nA    6.49uA     21.58nA
6.6V      0A         0A         0A
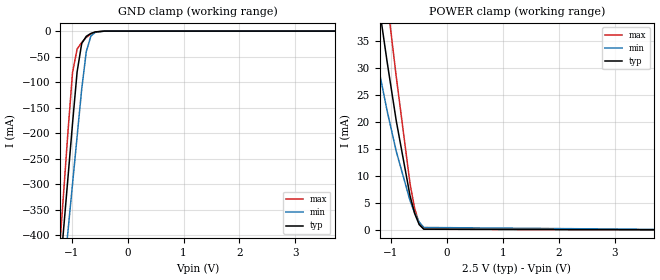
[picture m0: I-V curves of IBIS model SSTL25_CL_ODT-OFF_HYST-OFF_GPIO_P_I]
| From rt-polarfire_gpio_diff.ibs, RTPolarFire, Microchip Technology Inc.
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|   Model SSTL25_CL_ODT-OFF_HYST-OFF_GPIO_P_I
[Model]   SSTL25_CL_ODT-OFF_HYST-OFF_GPIO_P_I
Model_type   Input
Vinl =   1.1
Vinh =   1.4
|   typ   min   max
C_comp_pullup   2.605e-12   2.605e-12   2.76e-12
C_comp_pulldown  2.605e-12   2.605e-12   2.76e-12
[Temperature Range]  25C   125C   -55C
[Voltage Range]  2.5   2.375   2.625
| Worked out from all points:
|   GND clamp passes 1 mA (typ) near -0.54 V on its own axis
|   POWER clamp passes 1 mA (typ) near -0.49 V on its own axis
[GND Clamp]
| Voltage   I(typ)   I(min)   I(max)
-2.5V     -2.154A    -2.027A    -2.413A
-1.23V    -500mA     -578.6mA   -449.8mA
-1.066V   -287.6mA   -392.7mA   -197.7mA
-984.4mV  -181.4mA   -299.6mA   -81.42mA
-902.3mV  -80mA      -206.7mA   -35.21mA
-820.3mV  -24.5mA    -113.9mA   -22.16mA
-738.3mV  -10.19mA   -40.16mA   -12.42mA
-656.2mV  -4.611mA   -9.76mA    -5.513mA
-574.2mV  -1.55mA    -2.291mA   -1.729mA
-410.2mV  -27.4uA    -68.51uA   -22.46uA
5V        0A         0A         0A
[POWER Clamp]
| Voltage   I(typ)   I(min)   I(max)
-2.5V     164.6mA    122.6mA    208.5mA
-1.559V   69.3mA     49.79mA    90.65mA
-1.477V   62.31mA    44.62mA    81.77mA
-1.312V   49.01mA    35mA       64.78mA
-1.23V    42.93mA    30.54mA    56.91mA
-1.066V   31.14mA    22.06mA    42.59mA
-902.3mV  20.18mA    14.54mA    28.35mA
-656.2mV  6.301mA    5.435mA    8.526mA
-574.2mV  3.071mA    3.165mA    4.011mA
-492.2mV  984.8uA    1.457mA    1.158mA
-410.2mV  145.9uA    463uA      141.8uA
5V        0A         0A         0A
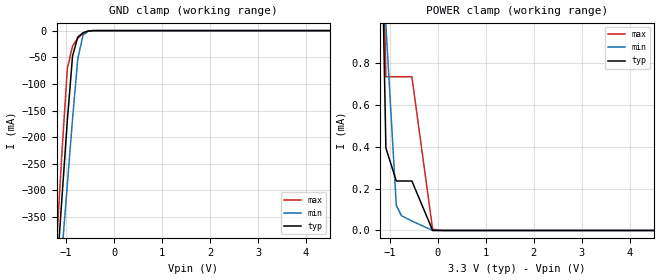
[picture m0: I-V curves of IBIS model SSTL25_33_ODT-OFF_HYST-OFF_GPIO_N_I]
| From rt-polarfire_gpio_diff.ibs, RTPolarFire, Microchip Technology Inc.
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|   Model SSTL25_33_ODT-OFF_HYST-OFF_GPIO_N_I
[Model]   SSTL25_33_ODT-OFF_HYST-OFF_GPIO_N_I
Model_type   Input
Vinl =   1.1
Vinh =   1.4
|   typ   min   max
C_comp_pullup   2.605e-12   2.605e-12   2.76e-12
C_comp_pulldown  2.605e-12   2.605e-12   2.76e-12
[Temperature Range]  25C   125C   -55C
[Voltage Range]  3.3   3.135   3.465
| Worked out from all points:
|   GND clamp passes 1 mA (typ) near -0.55 V on its own axis
|   POWER clamp passes 1 mA (typ) near -1.13 V on its own axis
[GND Clamp]
| Voltage   I(typ)   I(min)   I(max)
-3.3V     -3.213A    -2.953A    -3.676A
-1.408V   -729.6mA   -779.4mA   -722.4mA
-1.083V   -308.9mA   -411.3mA   -222.9mA
-974.5mV  -168.7mA   -288.5mA   -71.37mA
-866.2mV  -47.95mA   -165.8mA   -28.76mA
-758mV    -12.25mA   -53.97mA   -14.53mA
-649.7mV  -4.29mA    -8.693mA   -5.099mA
-541.4mV  -856.6uA   -1.234mA   -956.2uA
-433.1mV  -54.68uA   -117.6uA   -52.81uA
6.6V      0A         0A         0A
[POWER Clamp]
| Voltage   I(typ)   I(min)   I(max)
-3.3V     115.5mA    74.26mA    162.8mA
-1.191V   1.687mA    1.787mA    1.903mA
-1.083V   393.3uA    980uA      733.8uA
-866.2mV  236.1uA    120.2uA    733.8uA
-758mV    236.1uA    70.72uA    733.8uA
-541.4mV  236.1uA    45uA       733.8uA
-108.3mV  1.95nA     231.4nA    5.408uA
103.1mV   0A         0A         0A
6.6V      0A         0A         0A
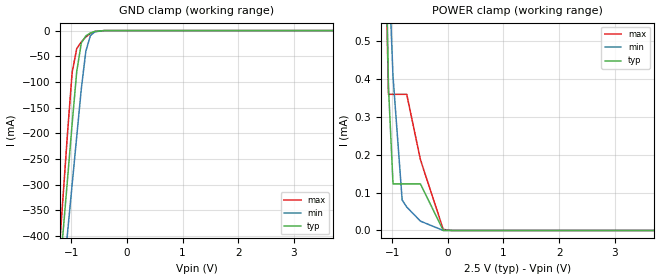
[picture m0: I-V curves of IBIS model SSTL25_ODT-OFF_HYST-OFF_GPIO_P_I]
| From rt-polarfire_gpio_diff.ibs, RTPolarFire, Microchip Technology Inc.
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|   Model SSTL25_ODT-OFF_HYST-OFF_GPIO_P_I
[Model]   SSTL25_ODT-OFF_HYST-OFF_GPIO_P_I
Model_type   Input
Vinl =   1.1
Vinh =   1.4
|   typ   min   max
C_comp_pullup   2.605e-12   2.605e-12   2.76e-12
C_comp_pulldown  2.605e-12   2.605e-12   2.76e-12
[Temperature Range]  25C   125C   -55C
[Voltage Range]  2.5   2.375   2.625
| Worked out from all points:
|   GND clamp passes 1 mA (typ) near -0.54 V on its own axis
|   POWER clamp passes 1 mA (typ) near -1.14 V on its own axis
[GND Clamp]
| Voltage   I(typ)   I(min)   I(max)
-2.5V     -2.154A    -2.027A    -2.413A
-1.23V    -500mA     -578.6mA   -449.8mA
-1.066V   -287.6mA   -392.7mA   -197.7mA
-984.4mV  -181.4mA   -299.6mA   -81.42mA
-902.3mV  -80mA      -206.7mA   -35.21mA
-820.3mV  -24.5mA    -113.9mA   -22.16mA
-738.3mV  -10.19mA   -40.16mA   -12.42mA
-656.2mV  -4.611mA   -9.76mA    -5.513mA
-574.2mV  -1.55mA    -2.291mA   -1.729mA
-410.2mV  -27.4uA    -68.51uA   -22.46uA
5V        0A         0A         0A
[POWER Clamp]
| Voltage   I(typ)   I(min)   I(max)
-2.5V     54.31mA    27.4mA     81.62mA
-1.148V   1.058mA    1.079mA    913.4uA
-1.066V   376.6uA    707.7uA    358.8uA
-984.4mV  122.8uA    405.2uA    358.8uA
-820.3mV  122.8uA    80.23uA    358.8uA
-738.3mV  122.8uA    61.81uA    358.8uA
-492.2mV  122.8uA    24.63uA    186.7uA
-82.03mV  935.3pA    68.31nA    2.754uA
78.12mV   0A         0A         0A
5V        0A         0A         0A
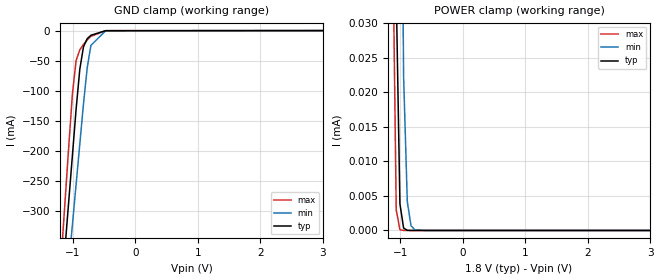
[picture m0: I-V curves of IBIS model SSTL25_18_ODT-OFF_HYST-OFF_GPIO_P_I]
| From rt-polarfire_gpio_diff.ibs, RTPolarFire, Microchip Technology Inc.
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|   Model SSTL25_18_ODT-OFF_HYST-OFF_GPIO_P_I
[Model]   SSTL25_18_ODT-OFF_HYST-OFF_GPIO_P_I
Model_type   Input
Vinl =   1.1
Vinh =   1.4
|   typ   min   max
C_comp_pullup   2.605e-12   2.605e-12   2.76e-12
C_comp_pulldown  2.605e-12   2.605e-12   2.76e-12
[Temperature Range]  25C   125C   -55C
[Voltage Range]  1.8   1.71   1.89
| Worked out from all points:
|   GND clamp passes 1 mA (typ) near -0.55 V on its own axis
[GND Clamp]
| Voltage   I(typ)   I(min)   I(max)
-1.8V     -1.238A    -1.225A    -1.326A
-1.181V   -436.3mA   -522.9mA   -374.2mA
-1.122V   -359.8mA   -455.9mA   -283.4mA
-1.063V   -283.3mA   -388.9mA   -192.7mA
-1.004V   -206.9mA   -322mA     -105.2mA
-945mV    -130.4mA   -255mA     -49.56mA
-885.9mV  -63.98mA   -188.1mA   -32.02mA
-826.9mV  -26.79mA   -121.3mA   -23.04mA
-767.8mV  -13.47mA   -61.88mA   -15.63mA
-708.7mV  -7.776mA   -24.65mA   -9.577mA
-472.5mV  -167uA     -289.4uA   -187.5uA
3.6V      0A         0A         0A
[POWER Clamp]
| Voltage   I(typ)   I(min)   I(max)
-1.8V     649.5uA    1.017mA    581.8uA
-1.122V   212.8uA    139.5uA    45.28uA
-1.063V   34.52uA    139.5uA    2.991uA
-1.004V   3.863uA    86.67uA    115.7nA
-945mV    344.1nA    22.28uA    4.519nA
-885.9mV  28.92nA    4.176uA    802.8pA
-826.9mV  2.961nA    696.1nA    638.5pA
-767.8mV  808.2pA    110.9nA    596.6pA
-590.6mV  511.9pA    3.576nA    488.6pA
3.6V      0A         0A         0A
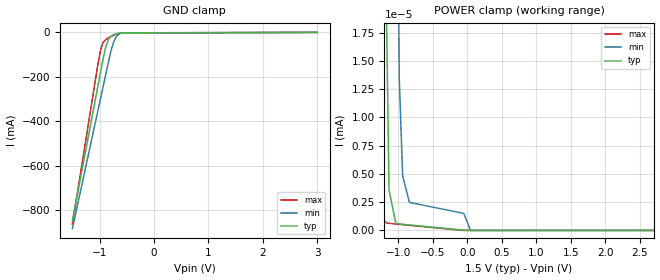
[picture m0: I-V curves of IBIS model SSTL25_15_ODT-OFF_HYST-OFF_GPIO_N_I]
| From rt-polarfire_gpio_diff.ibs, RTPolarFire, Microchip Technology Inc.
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|   Model SSTL25_15_ODT-OFF_HYST-OFF_GPIO_N_I
[Model]   SSTL25_15_ODT-OFF_HYST-OFF_GPIO_N_I
Model_type   Input
Vinl =   1.1
Vinh =   1.4
|   typ   min   max
C_comp_pullup   2.605e-12   2.605e-12   2.76e-12
C_comp_pulldown  2.605e-12   2.605e-12   2.76e-12
[Temperature Range]  25C   125C   -55C
[Voltage Range]  1.5   1.425   1.575
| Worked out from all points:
|   GND clamp passes 1 mA (typ) near -0.55 V on its own axis
[GND Clamp]
| Voltage   I(typ)   I(min)   I(max)
-1.5V     -849.2mA   -884.2mA   -864.5mA
-1.034V   -245.1mA   -355.5mA   -147.4mA
-984.4mV  -181.4mA   -299.7mA   -81.43mA
-935.2mV  -118mA     -243.9mA   -44.92mA
-885.9mV  -63.99mA   -188.1mA   -32.03mA
-836.7mV  -30.82mA   -132.4mA   -24.4mA
-787.5mV  -16.5mA    -79.61mA   -17.96mA
-738.3mV  -10.2mA    -40.17mA   -12.42mA
-689.1mV  -6.453mA   -17.46mA   -7.902mA
-639.8mV  -3.834mA   -7.312mA   -4.513mA
-590.6mV  -2.005mA   -3.08mA    -2.255mA
3V        0A         0A         0A
[POWER Clamp]
| Voltage   I(typ)   I(min)   I(max)
-1.5V     246.9uA    120uA      286.5uA
-1.329V   10.22uA    120uA      161.2nA
-1.23V    189.5nA    21uA       1.247nA
-1.181V   24.12nA    5.193uA    693.8pA
-1.132V   3.562nA    1.179uA    630.3pA
-1.034V   642.6pA    55.74nA    566.4pA
-984.4mV  574.2pA    13.6nA     536.4pA
-935.2mV  539.7pA    4.823nA    506.8pA
-836.7mV  480.5pA    2.474nA    448.5pA
-49.22mV  18.54pA    1.505nA    -6.808pA
46.88mV   0A         0A         0A
3V        0A         0A         0A
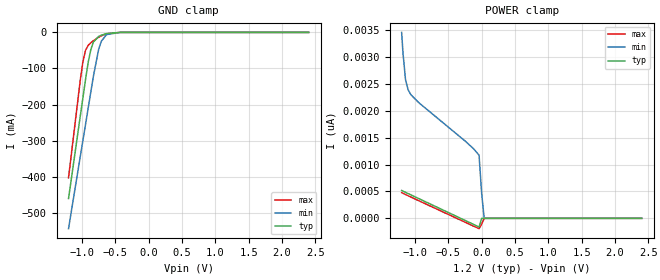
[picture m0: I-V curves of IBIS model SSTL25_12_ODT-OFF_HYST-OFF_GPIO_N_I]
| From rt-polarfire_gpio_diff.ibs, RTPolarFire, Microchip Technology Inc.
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|   Model SSTL25_12_ODT-OFF_HYST-OFF_GPIO_N_I
[Model]   SSTL25_12_ODT-OFF_HYST-OFF_GPIO_N_I
Model_type   Input
Vinl =   1.1
Vinh =   1.4
|   typ   min   max
C_comp_pullup   2.605e-12   2.605e-12   2.76e-12
C_comp_pulldown  2.605e-12   2.605e-12   2.76e-12
[Temperature Range]  25C   125C   -55C
[Voltage Range]  1.2   1.14   1.26
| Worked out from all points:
|   GND clamp passes 1 mA (typ) near -0.55 V on its own axis
[GND Clamp]
| Voltage   I(typ)   I(min)   I(max)
-1.2V     -460.6mA   -544.2mA   -403mA
-1.024V   -232.4mA   -344.3mA   -132.8mA
-984.4mV  -181.4mA   -299.7mA   -81.43mA
-945mV    -130.5mA   -255mA     -49.57mA
-905.6mV  -83.48mA   -210.4mA   -35.94mA
-866.2mV  -47.95mA   -165.8mA   -28.75mA
-826.9mV  -26.79mA   -121.3mA   -23.04mA
-748.1mV  -11.16mA   -46.72mA   -13.45mA
-708.7mV  -7.776mA   -24.65mA   -9.578mA
-630mV    -3.41mA    -6.155mA   -3.974mA
-433.1mV  -54.62uA   -117.5uA   -52.73uA
2.4V      0A         0A         0A
[POWER Clamp]
| Voltage   I(typ)   I(min)   I(max)
-1.2V     518.8pA    3.463nA    477.6pA
-1.181V   507.5pA    3.092nA    466.5pA
-1.142V   484.2pA    2.582nA    443.4pA
-1.103V   461pA      2.394nA    420.3pA
-1.063V   437.8pA    2.304nA    397.3pA
-945mV    368.6pA    2.156nA    328.8pA
-236.2mV  -46.29pA   1.427nA    -79.55pA
-118.1mV  -115.6pA   1.291nA    -147.4pA
-39.38mV  -162.4pA   1.176nA    -192.4pA
0V        0A         458.8pA    -106.9pA
37.5mV    0A         0A         0A
2.4V      0A         0A         0A
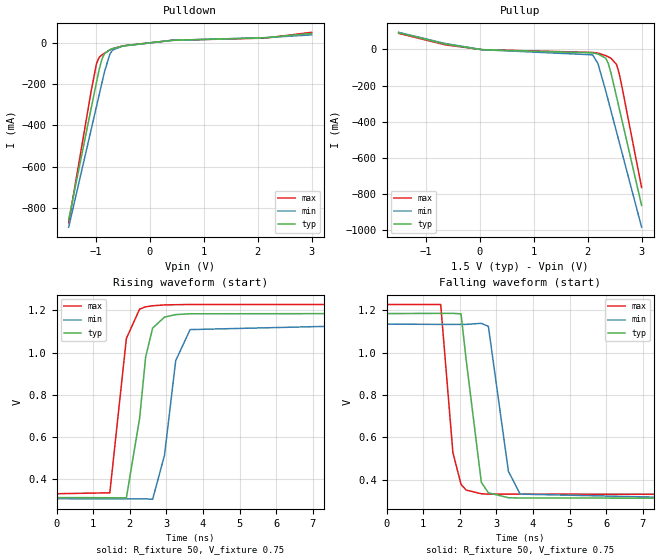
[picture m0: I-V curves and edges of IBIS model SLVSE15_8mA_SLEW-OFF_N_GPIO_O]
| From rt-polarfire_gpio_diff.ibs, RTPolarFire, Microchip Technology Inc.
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|   Model SLVSE15_8mA_SLEW-OFF_N_GPIO_O
[Model]   SLVSE15_8mA_SLEW-OFF_N_GPIO_O
Model_type   Output
Polarity   Inverting
Enable   Active-High
Vmeas =   0.2
Cref =   5p
Rref =   100
|   typ   min   max
C_comp_pullup   2.605e-12   2.605e-12   2.76e-12
C_comp_pulldown  2.605e-12   2.605e-12   2.76e-12
[Temperature Range]  25C   125C   -55C
[Voltage Range]  1.5   1.425   1.575
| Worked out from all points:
|   slope of the pulldown table from 0 to 0.225 V, typ, clamps not added: 34.2 ohm
|   slope of the pullup table from 0 to 0.225 V, typ, clamps not added: 34 ohm
|   rising waveform, R_fixture 50, V_fixture 0.75: 20-80 % time 318ps typ, 359ps min, 289ps max; typ from 0.312 V to 1.19 V
|   falling waveform, R_fixture 50, V_fixture 0.75: 20-80 % time 301ps typ, 366ps min, 234ps max; typ from 1.19 V to 0.312 V
[Pulldown]
| Voltage   I(typ)   I(min)   I(max)
-1.5V     -857.6mA   -893.6mA   -872.8mA
-1.083V   -317.8mA   -420.4mA   -234.4mA
-984.4mV  -191.2mA   -308.6mA   -101.8mA
-935.2mV  -130.7mA   -252.8mA   -71.57mA
-885.9mV  -81.84mA   -197mA     -59.88mA
-836.7mV  -53.8mA    -141.9mA   -51.2mA
-738.3mV  -34.61mA   -56.51mA   -36.09mA
-689.1mV  -29.46mA   -36.59mA   -29.9mA
-492.2mV  -16.37mA   -16.28mA   -15.56mA
421.9mV   11.24mA    10.59mA    11.15mA
2.14V     23.46mA    23.71mA    21.72mA
3V        44.03mA    37.37mA    49.63mA
[Pullup]
| Voltage   I(typ)   I(min)   I(max)
-1.5V     92.43mA    94.53mA    88.78mA
-639.8mV  29.78mA    32.87mA    25.37mA
46.88mV   -1.545mA   -1.593mA   -1.419mA
2.091V    -19.29mA   -29.85mA   -16.67mA
2.189V    -24.88mA   -76.05mA   -20.35mA
2.337V    -48.95mA   -231.2mA   -34.67mA
2.386V    -80.32mA   -287mA     -41.67mA
2.435V    -132.9mA   -342.7mA   -49.59mA
2.534V    -259.4mA   -454.4mA   -82.58mA
2.583V    -322.9mA   -510.1mA   -131mA
2.632V    -386.5mA   -565.9mA   -200.4mA
3V        -862.6mA   -983.1mA   -763.9mA
[Ramp]
dV/dt_r   0.523959/0.317622n  0.496933/0.35944n  0.538451/0.288831n
dV/dt_f   0.523956/0.301166n  0.496908/0.365876n  0.538448/0.234197n
R_load = 50
[Rising Waveform]
R_fixture = 50
V_fixture = 0.75
V_fixture_min = 0.7125
V_fixture_max = 0.7875
| Time   V(typ)   V(min)   V(max)
0s        311.9mV    306.6mV    330.2mV
1.456ns   311.2mV    306.2mV    334.6mV
1.908ns   310.4mV    306mV      1.067V
2.27ns    688.1mV    305.9mV    1.206V
2.434ns   978.2mV    305.9mV    1.217V
2.625ns   1.116V     303.6mV    1.222V
2.949ns   1.168V     512.2mV    1.226V
3.256ns   1.18V      961.9mV    1.227V
3.65ns    1.184V     1.109V     1.228V
10ns      1.185V     1.135V     1.228V
[Falling Waveform]
R_fixture = 50
V_fixture = 0.75
V_fixture_min = 0.7125
V_fixture_max = 0.7875
| Time   V(typ)   V(min)   V(max)
0s        1.185V     1.135V     1.228V
1.48ns    1.186V     1.134V     1.228V
1.813ns   1.186V     1.134V     528mV
2.035ns   1.184V     1.134V     377.4mV
2.175ns   967.2mV    1.134V     350.3mV
2.59ns    386.9mV    1.139V     333mV
2.782ns   337.5mV    1.125V     331.1mV
3.329ns   314.2mV    439.5mV    331mV
3.65ns    312.9mV    331.3mV    331mV
10ns      311.9mV    306.6mV    330.2mV
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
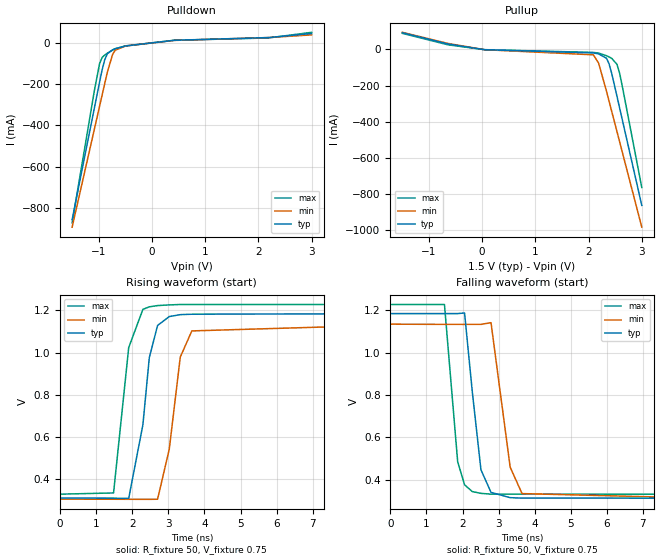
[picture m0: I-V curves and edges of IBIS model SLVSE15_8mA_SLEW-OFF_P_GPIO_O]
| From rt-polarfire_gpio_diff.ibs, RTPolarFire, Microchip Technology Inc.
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|   Model SLVSE15_8mA_SLEW-OFF_P_GPIO_O
[Model]   SLVSE15_8mA_SLEW-OFF_P_GPIO_O
Model_type   Output
Polarity   Non-Inverting
Enable   Active-High
Vmeas =   0.2
Cref =   5p
Rref =   100
|   typ   min   max
C_comp_pullup   2.605e-12   2.605e-12   2.76e-12
C_comp_pulldown  2.605e-12   2.605e-12   2.76e-12
[Temperature Range]  25C   125C   -55C
[Voltage Range]  1.5   1.425   1.575
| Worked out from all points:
|   slope of the pulldown table from 0 to 0.225 V, typ, clamps not added: 34.2 ohm
|   slope of the pullup table from 0 to 0.225 V, typ, clamps not added: 34 ohm
|   rising waveform, R_fixture 50, V_fixture 0.75: 20-80 % time 322ps typ, 372ps min, 297ps max; typ from 0.312 V to 1.19 V
|   falling waveform, R_fixture 50, V_fixture 0.75: 20-80 % time 300ps typ, 356ps min, 235ps max; typ from 1.19 V to 0.312 V
[Pullup]
| Voltage   I(typ)   I(min)   I(max)
-1.5V     92.45mA    94.53mA    88.84mA
-639.8mV  29.78mA    32.87mA    25.36mA
46.88mV   -1.545mA   -1.593mA   -1.419mA
2.091V    -19.29mA   -29.85mA   -16.67mA
2.189V    -24.89mA   -76.04mA   -20.35mA
2.337V    -48.94mA   -231.2mA   -34.67mA
2.386V    -80.3mA    -286.9mA   -41.68mA
2.435V    -132.9mA   -342.7mA   -49.6mA
2.534V    -259.3mA   -454.3mA   -82.57mA
2.583V    -322.9mA   -510.1mA   -131mA
2.632V    -386.4mA   -565.8mA   -200.4mA
3V        -862.5mA   -983mA     -763.8mA
[Pulldown]
| Voltage   I(typ)   I(min)   I(max)
-1.5V     -857.5mA   -893.5mA   -872.7mA
-1.083V   -317.7mA   -420.3mA   -234.3mA
-984.4mV  -191.2mA   -308.6mA   -101.8mA
-935.2mV  -130.6mA   -252.7mA   -71.58mA
-885.9mV  -81.82mA   -196.9mA   -59.89mA
-836.7mV  -53.8mA    -141.9mA   -51.21mA
-738.3mV  -34.62mA   -56.51mA   -36.09mA
-689.1mV  -29.47mA   -36.59mA   -29.9mA
-492.2mV  -16.37mA   -16.28mA   -15.56mA
421.9mV   11.24mA    10.59mA    11.15mA
2.189V    24.26mA    24.33mA    22.46mA
3V        44.04mA    37.37mA    49.69mA
[Ramp]
dV/dt_r   0.523958/0.322109n  0.496896/0.372312n  0.538451/0.29728n
dV/dt_f   0.523957/0.299559n  0.496915/0.356251n  0.538448/0.235238n
R_load = 50
[Rising Waveform]
R_fixture = 50
V_fixture = 0.75
V_fixture_min = 0.7125
V_fixture_max = 0.7875
| Time   V(typ)   V(min)   V(max)
0s        311.9mV    306.6mV    330.2mV
1.48ns    311.2mV    306.1mV    335.9mV
1.9ns     310.1mV    305.9mV    1.024V
2.293ns   658.6mV    305.8mV    1.205V
2.471ns   976.5mV    305.7mV    1.217V
2.7ns     1.129V     306.2mV    1.223V
3.024ns   1.171V     543.1mV    1.226V
3.329ns   1.18V      979.2mV    1.228V
3.65ns    1.182V     1.103V     1.228V
10ns      1.185V     1.135V     1.228V
[Falling Waveform]
R_fixture = 50
V_fixture = 0.75
V_fixture_min = 0.7125
V_fixture_max = 0.7875
| Time   V(typ)   V(min)   V(max)
0s        1.185V     1.135V     1.228V
1.5ns     1.185V     1.134V     1.228V
1.866ns   1.185V     1.134V     484.4mV
2.057ns   1.188V     1.134V     375.3mV
2.27ns    817.5mV    1.134V     343.5mV
2.511ns   446.4mV    1.134V     334.8mV
2.79ns    339.5mV    1.142V     331.1mV
3.321ns   314.5mV    458.7mV    331mV
3.65ns    312.4mV    333.7mV    331mV
10ns      311.9mV    306.6mV    330.2mV
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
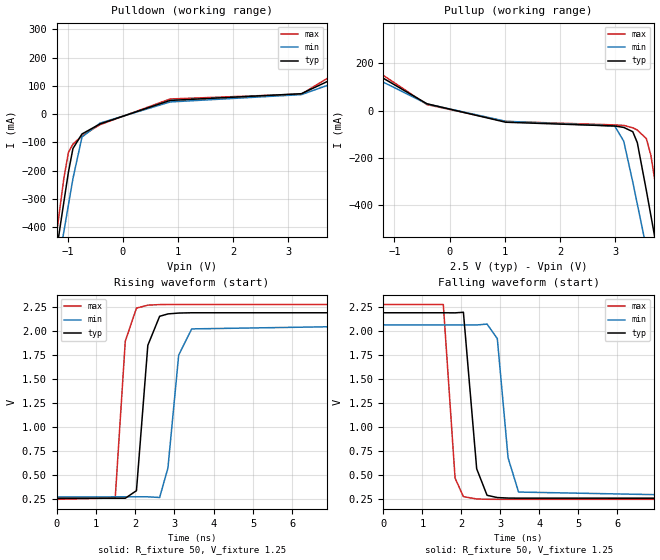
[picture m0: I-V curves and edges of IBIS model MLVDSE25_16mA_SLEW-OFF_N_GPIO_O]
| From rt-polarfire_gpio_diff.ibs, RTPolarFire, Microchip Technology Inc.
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|   Model MLVDSE25_16mA_SLEW-OFF_N_GPIO_O
[Model]   MLVDSE25_16mA_SLEW-OFF_N_GPIO_O
Model_type   Output
Polarity   Inverting
Enable   Active-High
Vmeas =   1.25
Cref =   5p
Rref =   100
|   typ   min   max
C_comp_pullup   2.605e-12   2.605e-12   2.76e-12
C_comp_pulldown  2.605e-12   2.605e-12   2.76e-12
[Temperature Range]  25C   125C   -55C
[Voltage Range]  2.5   2.375   2.625
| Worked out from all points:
|   slope of the pulldown table from 0 to 0.375 V, typ, clamps not added: 14 ohm
|   slope of the pullup table from 0 to 0.375 V, typ, clamps not added: 16.7 ohm
|   rising waveform, R_fixture 50, V_fixture 1.25: 20-80 % time 194ps typ, 242ps min, 157ps max; typ from 0.262 V to 2.19 V
|   falling waveform, R_fixture 50, V_fixture 1.25: 20-80 % time 176ps typ, 226ps min, 155ps max; typ from 2.19 V to 0.262 V
[Pulldown]
| Voltage   I(typ)   I(min)   I(max)
-2.5V     -2.176A    -2.052A    -2.433A
-1.312V   -627.8mA   -694.3mA   -597.9mA
-1.148V   -415.5mA   -507.9mA   -346.5mA
-1.066V   -309.4mA   -414.6mA   -225.8mA
-984.4mV  -205.2mA   -321.2mA   -135.7mA
-902.3mV  -121.7mA   -227.9mA   -106.1mA
-738.3mV  -70.31mA   -81.03mA   -76.95mA
-410.2mV  -34.69mA   -31.79mA   -37.31mA
859.4mV   48.28mA    42.87mA    53.39mA
3.238V    72.04mA    68.83mA    70.68mA
4.059V    147.4mA    125.5mA    167.8mA
5V        263.2mA    223.9mA    306.8mA
[Pullup]
| Voltage   I(typ)   I(min)   I(max)
-2.5V     314.9mA    272.4mA    352.8mA
-410.2mV  29.2mA     28.51mA    25.77mA
1.016V    -48.96mA   -44.92mA   -45.69mA
2.992V    -64.92mA   -65.1mA    -60.35mA
3.156V    -70.95mA   -129.4mA   -62.32mA
3.32V     -89.11mA   -302.7mA   -72.68mA
3.402V    -135.6mA   -395.7mA   -82.18mA
3.566V    -338.4mA   -581.8mA   -118.5mA
3.648V    -444.4mA   -674.8mA   -189.2mA
3.812V    -656.7mA   -860.9mA   -431.6mA
3.977V    -869.2mA   -1.047A    -683mA
5V        -2.206A    -2.221A    -2.263A
[Ramp]
dV/dt_r   1.15846/0.193968n  1.07437/0.242226n  1.21687/0.156866n
dV/dt_f   1.15845/0.175849n  1.07436/0.225959n  1.21687/0.154511n
R_load = 50
[Rising Waveform]
R_fixture = 50
V_fixture = 1.25
V_fixture_min = 1.1875
V_fixture_max = 1.3125
| Time   V(typ)   V(min)   V(max)
0s        261.7mV    275.4mV    250.1mV
1.493ns   261.5mV    276mV      264.4mV
1.749ns   261.5mV    276.1mV    1.897V
2.033ns   340.2mV    276.2mV    2.24V
2.322ns   1.853V     276.3mV    2.271V
2.622ns   2.155V     269.2mV    2.277V
2.833ns   2.18V      574.9mV    2.278V
3.107ns   2.189V     1.751V     2.278V
3.438ns   2.192V     2.024V     2.278V
10ns      2.192V     2.066V     2.278V
[Falling Waveform]
R_fixture = 50
V_fixture = 1.25
V_fixture_min = 1.1875
V_fixture_max = 1.3125
| Time   V(typ)   V(min)   V(max)
0s        2.192V     2.066V     2.278V
1.536ns   2.192V     2.065V     2.278V
1.837ns   2.191V     2.065V     471.4mV
2.051ns   2.197V     2.065V     278.1mV
2.391ns   568.2mV    2.065V     253.8mV
2.657ns   292mV      2.074V     250.8mV
2.92ns    268.6mV    1.923V     250.2mV
3.196ns   263.3mV    681.5mV    250.2mV
3.465ns   262.2mV    325.8mV    250.2mV
10ns      261.7mV    275.4mV    250.1mV
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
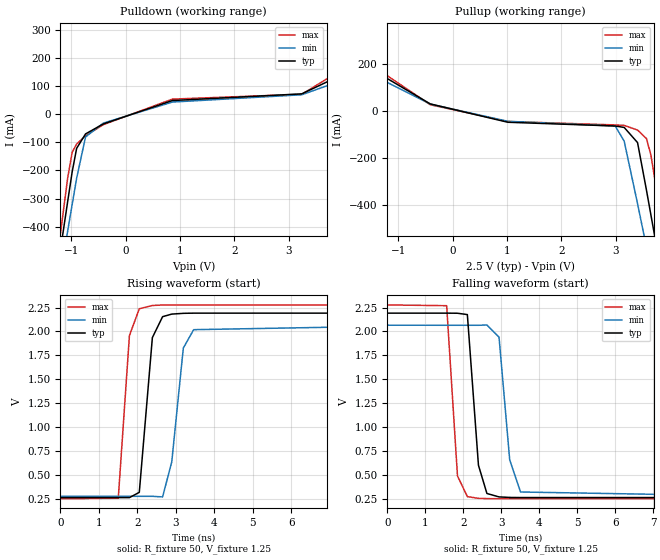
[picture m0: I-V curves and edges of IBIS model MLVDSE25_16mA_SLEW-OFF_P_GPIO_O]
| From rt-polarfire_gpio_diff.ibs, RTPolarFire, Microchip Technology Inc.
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|   Model MLVDSE25_16mA_SLEW-OFF_P_GPIO_O
[Model]   MLVDSE25_16mA_SLEW-OFF_P_GPIO_O
Model_type   Output
Polarity   Non-Inverting
Enable   Active-High
Vmeas =   1.25
Cref =   5p
Rref =   100
|   typ   min   max
C_comp_pullup   2.605e-12   2.605e-12   2.76e-12
C_comp_pulldown  2.605e-12   2.605e-12   2.76e-12
[Temperature Range]  25C   125C   -55C
[Voltage Range]  2.5   2.375   2.625
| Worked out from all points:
|   slope of the pulldown table from 0 to 0.375 V, typ, clamps not added: 14 ohm
|   slope of the pullup table from 0 to 0.375 V, typ, clamps not added: 16.7 ohm
|   rising waveform, R_fixture 50, V_fixture 1.25: 20-80 % time 197ps typ, 250ps min, 159ps max; typ from 0.262 V to 2.19 V
|   falling waveform, R_fixture 50, V_fixture 1.25: 20-80 % time 173ps typ, 220ps min, 155ps max; typ from 2.19 V to 0.262 V
[Pullup]
| Voltage   I(typ)   I(min)   I(max)
-2.5V     314.9mA    272.5mA    352.9mA
-410.2mV  29.2mA     28.51mA    25.77mA
1.016V    -48.96mA   -44.92mA   -45.69mA
2.992V    -64.92mA   -65.1mA    -60.35mA
3.156V    -70.96mA   -129.4mA   -62.32mA
3.402V    -135.6mA   -395.6mA   -82.19mA
3.566V    -338.3mA   -581.7mA   -118.5mA
3.648V    -444.3mA   -674.7mA   -189.2mA
3.73V     -550.4mA   -767.7mA   -305.9mA
3.895V    -762.8mA   -953.9mA   -557.2mA
4.059V    -975.4mA   -1.14A     -808.7mA
5V        -2.206A    -2.221A    -2.262A
[Pulldown]
| Voltage   I(typ)   I(min)   I(max)
-2.5V     -2.176A    -2.052A    -2.432A
-1.23V    -521.5mA   -601.1mA   -472.1mA
-1.148V   -415.4mA   -507.9mA   -346.5mA
-1.066V   -309.4mA   -414.5mA   -225.7mA
-984.4mV  -205.2mA   -321.2mA   -135.7mA
-902.3mV  -121.7mA   -227.9mA   -106.1mA
-738.3mV  -70.31mA   -81.03mA   -76.95mA
-410.2mV  -34.69mA   -31.79mA   -37.31mA
859.4mV   48.28mA    42.87mA    53.39mA
3.238V    72.04mA    68.83mA    70.67mA
4.059V    147.4mA    125.5mA    167.9mA
5V        263.2mA    223.9mA    306.8mA
[Ramp]
dV/dt_r   1.15846/0.197184n  1.07436/0.250295n  1.21687/0.159031n
dV/dt_f   1.15845/0.172724n  1.07436/0.220163n  1.21687/0.154686n
R_load = 50
[Rising Waveform]
R_fixture = 50
V_fixture = 1.25
V_fixture_min = 1.1875
V_fixture_max = 1.3125
| Time   V(typ)   V(min)   V(max)
0s        261.7mV    275.4mV    250.1mV
1.504ns   261.5mV    275.1mV    254.7mV
1.794ns   261.5mV    275.1mV    1.957V
2.051ns   316.7mV    275mV      2.238V
2.391ns   1.936V     274.9mV    2.272V
2.657ns   2.155V     268.9mV    2.277V
2.895ns   2.182V     634.5mV    2.278V
3.196ns   2.19V      1.827V     2.278V
3.465ns   2.192V     2.019V     2.278V
10ns      2.192V     2.066V     2.278V
[Falling Waveform]
R_fixture = 50
V_fixture = 1.25
V_fixture_min = 1.1875
V_fixture_max = 1.3125
| Time   V(typ)   V(min)   V(max)
0s        2.192V     2.066V     2.278V
1.562ns   2.192V     2.065V     2.27V
1.847ns   2.191V     2.065V     488.4mV
2.107ns   2.177V     2.065V     271.7mV
2.399ns   600.4mV    2.065V     253.8mV
2.622ns   304.6mV    2.068V     251.2mV
2.941ns   268.8mV    1.94V      250.2mV
3.222ns   263.3mV    656.2mV    250.2mV
3.507ns   262.1mV    320.2mV    250.2mV
10ns      261.7mV    275.4mV    250.1mV
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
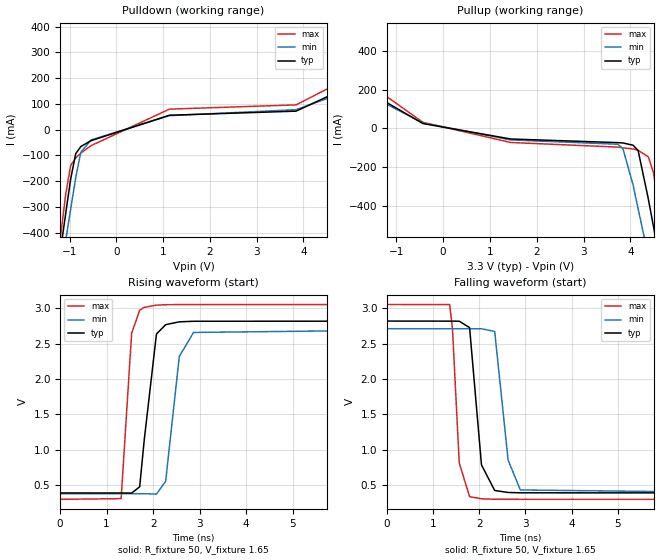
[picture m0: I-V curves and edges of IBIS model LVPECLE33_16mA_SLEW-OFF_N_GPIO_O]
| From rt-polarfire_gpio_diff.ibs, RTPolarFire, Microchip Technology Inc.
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|   Model LVPECLE33_16mA_SLEW-OFF_N_GPIO_O
[Model]   LVPECLE33_16mA_SLEW-OFF_N_GPIO_O
Model_type   Output
Polarity   Inverting
Enable   Active-High
Vmeas =   1.65
Cref =   5p
Rref =   100
|   typ   min   max
C_comp_pullup   2.605e-12   2.605e-12   2.76e-12
C_comp_pulldown  2.605e-12   2.605e-12   2.76e-12
[Temperature Range]  25C   125C   -55C
[Voltage Range]  3.3   3.135   3.465
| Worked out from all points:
|   slope of the pulldown table from 0 to 0.495 V, typ, clamps not added: 16 ohm
|   slope of the pullup table from 0 to 0.495 V, typ, clamps not added: 20.7 ohm
|   rising waveform, R_fixture 50, V_fixture 1.65: 20-80 % time 178ps typ, 216ps min, 130ps max; typ from 0.389 V to 2.82 V
|   falling waveform, R_fixture 50, V_fixture 1.65: 20-80 % time 174ps typ, 184ps min, 125ps max; typ from 2.82 V to 0.389 V
[Pulldown]
| Voltage   I(typ)   I(min)   I(max)
-3.3V     -3.233A    -2.976A    -3.698A
-1.191V   -467.4mA   -554.1mA   -414.1mA
-1.083V   -327.3mA   -431mA     -253mA
-974.5mV  -190.4mA   -307.8mA   -138.3mA
-866.2mV  -92.33mA   -185.2mA   -109.4mA
-758mV    -65.3mA    -87.67mA   -90.81mA
-541.4mV  -42.48mA   -39.9mA    -61.98mA
1.134V    56.29mA    54.69mA    79.96mA
3.841V    72.17mA    77.85mA    96.61mA
4.708V    145.2mA    134.5mA    177.1mA
6.115V    327.1mA    291.8mA    396mA
6.6V      407.5mA    361.6mA    485.6mA
[Pullup]
| Voltage   I(typ)   I(min)   I(max)
-3.3V     426.9mA    383.6mA    524.5mA
-433.1mV  24.19mA    27.89mA    30.49mA
1.444V    -55.61mA   -60.21mA   -73.6mA
3.733V    -74.41mA   -82.78mA   -97.58mA
3.841V    -76.08mA   -105.2mA   -101.4mA
4.058V    -87.8mA    -292.7mA   -107.2mA
4.166V    -115mA     -415.4mA   -114mA
4.383V    -363.9mA   -661.2mA   -147.6mA
4.491V    -503.9mA   -784mA     -227.2mA
4.708V    -784.2mA   -1.03A     -541.7mA
4.924V    -1.065A    -1.276A    -873.9mA
6.6V      -3.278A    -3.224A    -3.498A
[Ramp]
dV/dt_r   1.45721/0.178348n  1.39869/0.215516n  1.65157/0.129979n
dV/dt_f   1.45721/0.173569n  1.39868/0.18376n  1.65157/0.125273n
R_load = 50
[Rising Waveform]
R_fixture = 50
V_fixture = 1.65
V_fixture_min = 1.5675
V_fixture_max = 1.7325
| Time   V(typ)   V(min)   V(max)
0s        388.9mV    378.8mV    299mV
1.312ns   388.5mV    378.9mV    308.6mV
1.538ns   387mV      378.9mV    2.646V
1.711ns   476.4mV    379mV      2.971V
1.81ns    1.145V     379mV      3.012V
2.072ns   2.635V     372.3mV    3.043V
2.27ns    2.767V     555mV      3.049V
2.563ns   2.807V     2.317V     3.051V
2.869ns   2.815V     2.657V     3.051V
10ns      2.818V     2.71V      3.052V
[Falling Waveform]
R_fixture = 50
V_fixture = 1.65
V_fixture_min = 1.5675
V_fixture_max = 1.7325
| Time   V(typ)   V(min)   V(max)
0s        2.818V     2.71V      3.052V
1.358ns   2.817V     2.709V     3.051V
1.419ns   2.817V     2.709V     2.7V
1.565ns   2.816V     2.709V     813.1mV
1.789ns   2.725V     2.709V     337.3mV
2.047ns   785.3mV    2.709V     306.2mV
2.333ns   424.2mV    2.671V     300.3mV
2.624ns   395.9mV    853.1mV    299.7mV
2.89ns    391mV      431.3mV    299.3mV
10ns      389mV      378.8mV    299mV
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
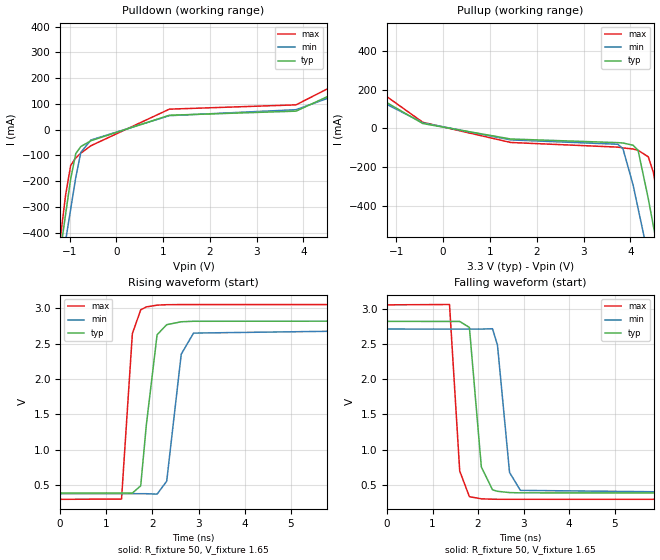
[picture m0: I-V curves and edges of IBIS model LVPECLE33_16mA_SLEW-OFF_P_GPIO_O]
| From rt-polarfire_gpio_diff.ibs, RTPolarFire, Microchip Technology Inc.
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|   Model LVPECLE33_16mA_SLEW-OFF_P_GPIO_O
[Model]   LVPECLE33_16mA_SLEW-OFF_P_GPIO_O
Model_type   Output
Polarity   Non-Inverting
Enable   Active-High
Vmeas =   1.65
Cref =   5p
Rref =   100
|   typ   min   max
C_comp_pullup   2.605e-12   2.605e-12   2.76e-12
C_comp_pulldown  2.605e-12   2.605e-12   2.76e-12
[Temperature Range]  25C   125C   -55C
[Voltage Range]  3.3   3.135   3.465
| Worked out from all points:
|   slope of the pulldown table from 0 to 0.495 V, typ, clamps not added: 16 ohm
|   slope of the pullup table from 0 to 0.495 V, typ, clamps not added: 20.7 ohm
|   rising waveform, R_fixture 50, V_fixture 1.65: 20-80 % time 181ps typ, 222ps min, 132ps max; typ from 0.389 V to 2.82 V
|   falling waveform, R_fixture 50, V_fixture 1.65: 20-80 % time 172ps typ, 183ps min, 125ps max; typ from 2.82 V to 0.389 V
[Pullup]
| Voltage   I(typ)   I(min)   I(max)
-3.3V     426.9mA    383.6mA    524.6mA
-433.1mV  24.19mA    27.89mA    30.49mA
1.444V    -55.61mA   -60.21mA   -73.6mA
3.733V    -74.42mA   -82.78mA   -97.59mA
3.841V    -76.09mA   -105.2mA   -101.5mA
4.058V    -87.8mA    -292.6mA   -107.3mA
4.166V    -114.9mA   -415.4mA   -114.1mA
4.383V    -363.8mA   -661.1mA   -147.6mA
4.491V    -503.8mA   -783.9mA   -227.1mA
4.708V    -784.1mA   -1.03A     -541.6mA
4.924V    -1.065A    -1.276A    -873.8mA
6.6V      -3.277A    -3.223A    -3.497A
[Pulldown]
| Voltage   I(typ)   I(min)   I(max)
-3.3V     -3.232A    -2.976A    -3.698A
-1.191V   -467.3mA   -554.1mA   -414mA
-1.083V   -327.3mA   -431mA     -252.9mA
-974.5mV  -190.3mA   -307.8mA   -138.3mA
-866.2mV  -92.32mA   -185.2mA   -109.4mA
-758mV    -65.3mA    -87.66mA   -90.83mA
-541.4mV  -42.49mA   -39.9mA    -62.01mA
1.134V    56.29mA    54.69mA    79.96mA
3.841V    72.16mA    77.84mA    96.61mA
4.708V    145.2mA    134.6mA    177.1mA
6.115V    327.1mA    291.8mA    396mA
6.6V      407.5mA    361.7mA    485.7mA
[Ramp]
dV/dt_r   1.45721/0.181254n  1.39869/0.221593n  1.65157/0.132015n
dV/dt_f   1.4572/0.171945n  1.39868/0.182901n  1.65156/0.125417n
R_load = 50
[Rising Waveform]
R_fixture = 50
V_fixture = 1.65
V_fixture_min = 1.5675
V_fixture_max = 1.7325
| Time   V(typ)   V(min)   V(max)
0s        389mV      378.8mV    299mV
1.33ns    388.9mV    378.4mV    303mV
1.565ns   387.3mV    378.4mV    2.641V
1.746ns   490.2mV    378.3mV    2.976V
1.867ns   1.347V     378.3mV    3.018V
2.101ns   2.625V     373mV      3.043V
2.309ns   2.767V     555mV      3.049V
2.624ns   2.808V     2.35V      3.051V
2.89ns    2.815V     2.648V     3.051V
10ns      2.818V     2.71V      3.052V
[Falling Waveform]
R_fixture = 50
V_fixture = 1.65
V_fixture_min = 1.5675
V_fixture_max = 1.7325
| Time   V(typ)   V(min)   V(max)
0s        2.818V     2.71V      3.052V
1.373ns   2.817V     2.709V     3.057V
1.597ns   2.817V     2.709V     699.8mV
1.81ns    2.732V     2.709V     336mV
2.072ns   757.2mV    2.709V     306.2mV
2.318ns   433.3mV    2.714V     300.8mV
2.427ns   412.8mV    2.48V      299.9mV
2.692ns   394.4mV    679.2mV    299.6mV
2.93ns    390.7mV    425.8mV    299.6mV
10ns      389mV      378.8mV    299mV
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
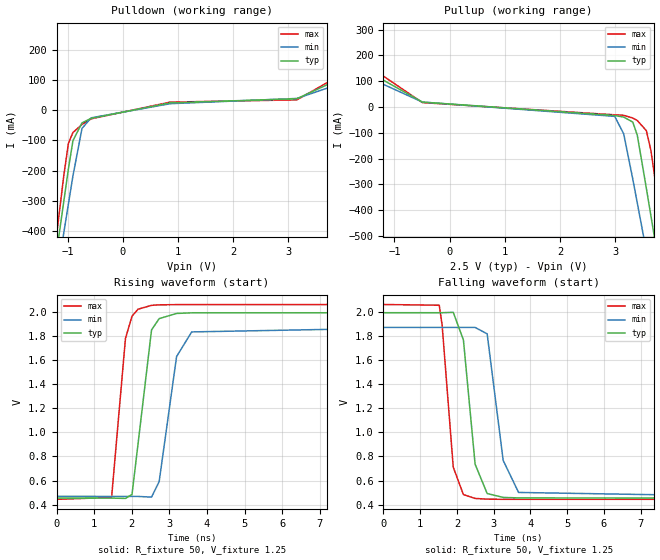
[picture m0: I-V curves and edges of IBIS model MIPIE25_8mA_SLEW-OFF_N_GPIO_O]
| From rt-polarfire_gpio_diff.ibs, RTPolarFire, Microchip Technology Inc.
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|   Model MIPIE25_8mA_SLEW-OFF_N_GPIO_O
[Model]   MIPIE25_8mA_SLEW-OFF_N_GPIO_O
Model_type   Output
Polarity   Inverting
Enable   Active-High
Vmeas =   0.2
Cref =   5p
Rref =   100
|   typ   min   max
C_comp_pullup   2.605e-12   2.605e-12   2.76e-12
C_comp_pulldown  2.605e-12   2.605e-12   2.76e-12
[Temperature Range]  25C   125C   -55C
[Voltage Range]  2.5   2.375   2.625
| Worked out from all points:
|   slope of the pulldown table from 0 to 0.375 V, typ, clamps not added: 27.6 ohm
|   slope of the pullup table from 0 to 0.375 V, typ, clamps not added: 33.1 ohm
|   rising waveform, R_fixture 50, V_fixture 1.25: 20-80 % time 281ps typ, 360ps min, 232ps max; typ from 0.455 V to 1.99 V
|   falling waveform, R_fixture 50, V_fixture 1.25: 20-80 % time 279ps typ, 320ps min, 244ps max; typ from 1.99 V to 0.455 V
[Pulldown]
| Voltage   I(typ)   I(min)   I(max)
-2.5V     -2.166A    -2.04A     -2.423A
-1.23V    -511.5mA   -590mA     -462.8mA
-1.148V   -405.4mA   -497mA     -337.2mA
-1.066V   -299.4mA   -403.8mA   -213.7mA
-984.4mV  -194.1mA   -310.7mA   -109.8mA
-902.3mV  -100.9mA   -217.6mA   -74mA
-738.3mV  -42.04mA   -60.47mA   -47.16mA
-574.2mV  -27.1mA    -25.37mA   -28.75mA
859.4mV   24.29mA    21.54mA    26.84mA
3.156V    37.94mA    38.95mA    34.22mA
3.812V    93.41mA    79.69mA    102.7mA
5V        233.3mA    197mA      274.3mA
[Pullup]
| Voltage   I(typ)   I(min)   I(max)
-2.5V     259.2mA    213.9mA    307.6mA
-492.2mV  19.08mA    19.03mA    17.04mA
2.992V    -32.89mA   -36.15mA   -30.21mA
3.156V    -38.96mA   -104.2mA   -32.12mA
3.32V     -58.4mA    -279mA     -42.71mA
3.402V    -109.4mA   -372mA     -52.35mA
3.566V    -314.5mA   -558mA     -91.54mA
3.648V    -420.5mA   -651mA     -167.1mA
3.812V    -632.7mA   -836.9mA   -411.8mA
3.895V    -738.9mA   -930mA     -537.5mA
3.977V    -845.1mA   -1.023A    -663.2mA
5V        -2.181A    -2.196A    -2.242A
[Ramp]
dV/dt_r   0.920739/0.28096n  0.839051/0.360034n  0.968026/0.231965n
dV/dt_f   0.920735/0.278827n  0.839044/0.319905n  0.968023/0.243978n
R_load = 50
[Rising Waveform]
R_fixture = 50
V_fixture = 1.25
V_fixture_min = 1.1875
V_fixture_max = 1.3125
| Time   V(typ)   V(min)   V(max)
0s        455.3mV    469.4mV    444.6mV
1.464ns   455mV      468.8mV    460mV
1.833ns   452mV      468.7mV    1.777V
2.007ns   485.6mV    468.6mV    1.961V
2.167ns   903.4mV    468.6mV    2.019V
2.526ns   1.847V     462.9mV    2.051V
2.729ns   1.941V     591.5mV    2.055V
3.192ns   1.984V     1.627V     2.057V
3.594ns   1.989V     1.831V     2.057V
10ns      1.99V      1.868V     2.058V
[Falling Waveform]
R_fixture = 50
V_fixture = 1.25
V_fixture_min = 1.1875
V_fixture_max = 1.3125
| Time   V(typ)   V(min)   V(max)
0s        1.99V      1.868V     2.058V
1.52ns    1.99V      1.868V     2.052V
1.598ns   1.99V      1.868V     1.889V
1.901ns   1.993V     1.868V     710.6mV
2.178ns   1.764V     1.868V     483.6mV
2.496ns   735.1mV    1.868V     451.8mV
2.824ns   492.5mV    1.815V     446mV
3.26ns    460.2mV    766.6mV    444.4mV
3.679ns   456.1mV    501.4mV    444.4mV
10ns      455.3mV    469.4mV    444.6mV
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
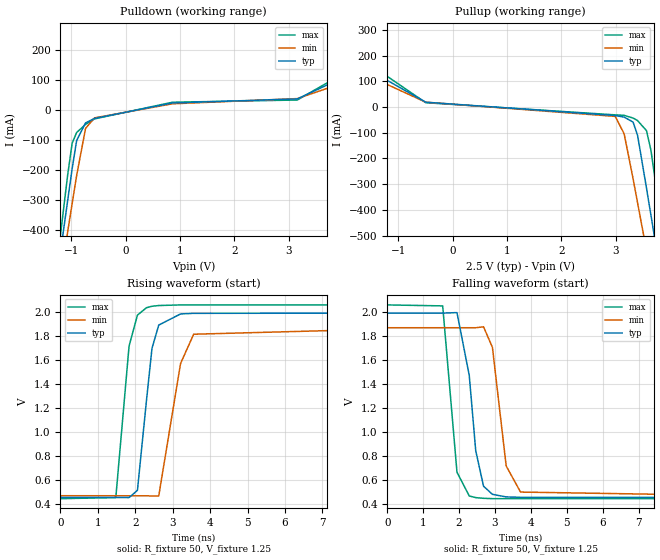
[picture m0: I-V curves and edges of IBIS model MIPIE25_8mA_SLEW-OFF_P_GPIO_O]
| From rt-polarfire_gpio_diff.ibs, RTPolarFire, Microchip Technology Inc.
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|   Model MIPIE25_8mA_SLEW-OFF_P_GPIO_O
[Model]   MIPIE25_8mA_SLEW-OFF_P_GPIO_O
Model_type   Output
Polarity   Non-Inverting
Enable   Active-High
Vmeas =   0.2
Cref =   5p
Rref =   100
|   typ   min   max
C_comp_pullup   2.605e-12   2.605e-12   2.76e-12
C_comp_pulldown  2.605e-12   2.605e-12   2.76e-12
[Temperature Range]  25C   125C   -55C
[Voltage Range]  2.5   2.375   2.625
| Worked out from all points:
|   slope of the pulldown table from 0 to 0.375 V, typ, clamps not added: 27.6 ohm
|   slope of the pullup table from 0 to 0.375 V, typ, clamps not added: 33.1 ohm
|   rising waveform, R_fixture 50, V_fixture 1.25: 20-80 % time 285ps typ, 372ps min, 236ps max; typ from 0.455 V to 1.99 V
|   falling waveform, R_fixture 50, V_fixture 1.25: 20-80 % time 277ps typ, 315ps min, 243ps max; typ from 1.99 V to 0.455 V
[Pullup]
| Voltage   I(typ)   I(min)   I(max)
-2.5V     259.3mA    213.9mA    307.6mA
-492.2mV  19.08mA    19.03mA    17.04mA
2.992V    -32.89mA   -36.15mA   -30.21mA
3.156V    -38.96mA   -104.2mA   -32.12mA
3.32V     -58.4mA    -279mA     -42.71mA
3.402V    -109.4mA   -372mA     -52.36mA
3.566V    -314.5mA   -557.9mA   -91.52mA
3.648V    -420.5mA   -650.9mA   -167.1mA
3.812V    -632.6mA   -836.9mA   -411.7mA
3.895V    -738.8mA   -929.9mA   -537.4mA
4.059V    -951.3mA   -1.116A    -788.8mA
5V        -2.181A    -2.196A    -2.242A
[Pulldown]
| Voltage   I(typ)   I(min)   I(max)
-2.5V     -2.165A    -2.04A     -2.423A
-1.23V    -511.4mA   -590mA     -462.7mA
-1.148V   -405.4mA   -496.9mA   -337.1mA
-1.066V   -299.4mA   -403.8mA   -213.7mA
-984.4mV  -194mA     -310.6mA   -109.7mA
-902.3mV  -100.9mA   -217.5mA   -74.01mA
-738.3mV  -42.04mA   -60.46mA   -47.17mA
-574.2mV  -27.1mA    -25.37mA   -28.75mA
859.4mV   24.29mA    21.54mA    26.84mA
3.156V    37.94mA    38.95mA    34.22mA
3.812V    93.42mA    79.7mA     102.7mA
5V        233.3mA    197mA      274.3mA
[Ramp]
dV/dt_r   0.920739/0.285323n  0.83905/0.372262n  0.968025/0.235624n
dV/dt_f   0.920735/0.277447n  0.839043/0.314684n  0.968023/0.24289n
R_load = 50
[Rising Waveform]
R_fixture = 50
V_fixture = 1.25
V_fixture_min = 1.1875
V_fixture_max = 1.3125
| Time   V(typ)   V(min)   V(max)
0s        455.3mV    469.4mV    444.6mV
1.479ns   454.6mV    469.1mV    454.2mV
1.833ns   454mV      469mV      1.715V
2.057ns   514.2mV    469mV      1.973V
2.299ns   1.265V     469mV      2.035V
2.446ns   1.697V     467mV      2.047V
2.626ns   1.89V      467.1mV    2.053V
3.209ns   1.983V     1.57V      2.058V
3.559ns   1.988V     1.814V     2.058V
10ns      1.99V      1.868V     2.058V
[Falling Waveform]
R_fixture = 50
V_fixture = 1.25
V_fixture_min = 1.1875
V_fixture_max = 1.3125
| Time   V(typ)   V(min)   V(max)
0s        1.99V      1.868V     2.058V
1.543ns   1.99V      1.868V     2.05V
1.941ns   1.994V     1.868V     665.1mV
2.283ns   1.471V     1.868V     467.4mV
2.463ns   845mV      1.868V     453.6mV
2.681ns   548.4mV    1.876V     447.8mV
2.929ns   481mV      1.704V     445.1mV
3.312ns   459.5mV    717.1mV    445.1mV
3.712ns   456.1mV    499.8mV    445.1mV
10ns      455.3mV    469.4mV    444.6mV
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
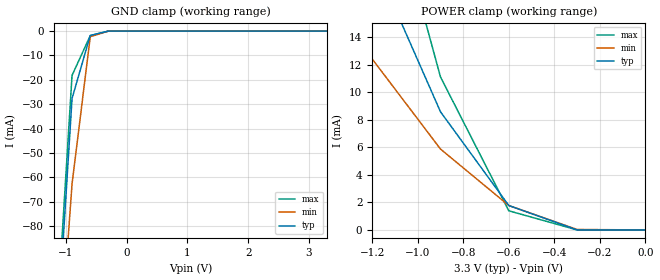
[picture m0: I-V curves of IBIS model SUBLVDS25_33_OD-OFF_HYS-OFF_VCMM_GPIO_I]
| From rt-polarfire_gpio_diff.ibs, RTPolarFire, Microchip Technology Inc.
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|   SUBLVDS25_33_OD-OFF_HYS-OFF_VCMM_GPIO_I
[Model]   SUBLVDS25_33_OD-OFF_HYS-OFF_VCMM_GPIO_I
Model_type  Input
Vinl =   0.775
Vinh =   1.025
|   typ   min   max
C_comp_pullup   2.605e-12   2.605e-12   2.76e-12
C_comp_pulldown  2.605e-12   2.605e-12   2.76e-12
[Temperature Range]  25C   125C   -55C
[Voltage Range]  3.3V   3.15V   3.45V
[GND_clamp]
|Voltage   I(typ)   I(min)   I(max)
-3.3V     -1.138A    -1.009A    -1.358A
-1.2V     -147.1mA   -166.4mA   -139.1mA
-900mV    -27.64mA   -62.75mA   -18.17mA
-600mV    -1.775mA   -2.295mA   -1.891mA
-300mV    -1.462uA   -7.897uA   -459.7nA
3.3V      1.341uA    2.115uA    1.126uA
[POWER_clamp]
|Voltage   I(typ)   I(min)   I(max)
-3.3V     238mA      176.4mA    330.8mA
-3V       189mA      137.1mA    275mA
-2.7V     150.7mA    103.8mA    226mA
-2.4V     116.7mA    77.61mA    180.2mA
-2.1V     85.28mA    55.93mA    135mA
-1.8V     55.36mA    37.15mA    89.04mA
-1.5V     34.04mA    22.18mA    54.21mA
-1.2V     19.85mA    12.42mA    29.33mA
-900mV    8.583mA    5.877mA    11.11mA
-600mV    1.775mA    1.776mA    1.392mA
-300mV    6.226uA    35.39uA    2.384uA
0V        0A         0A         0A
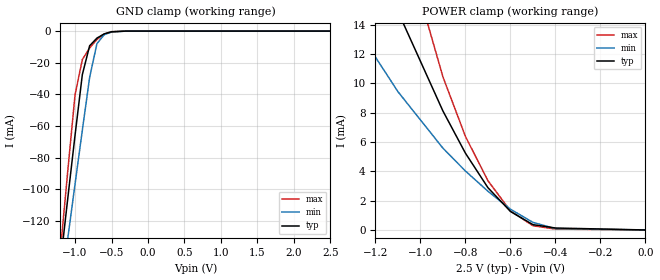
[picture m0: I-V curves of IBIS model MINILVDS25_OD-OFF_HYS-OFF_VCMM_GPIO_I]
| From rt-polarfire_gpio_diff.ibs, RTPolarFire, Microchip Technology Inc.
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|   MINILVDS25_OD-OFF_HYS-OFF_VCMM_GPIO_I
[Model]   MINILVDS25_OD-OFF_HYS-OFF_VCMM_GPIO_I
Model_type  Input
Vinl =   1.125
Vinh =   1.375
|   typ   min   max
C_comp_pullup   2.605e-12   2.605e-12   2.76e-12
C_comp_pulldown  2.605e-12   2.605e-12   2.76e-12
[Temperature Range]  25C   125C   -55C
[Voltage Range]  2.5V   2.375V   2.625V
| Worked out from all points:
|   GND clamp passes 1 mA (typ) near -0.54 V on its own axis
|   POWER clamp passes 1 mA (typ) near -0.57 V on its own axis
[GND_clamp]
|Voltage   I(typ)   I(min)   I(max)
-2.5V     -723.9mA   -655.9mA   -843mA
-1.2V     -146.7mA   -166.1mA   -138.5mA
-1.1V     -105.9mA   -131.2mA   -88.64mA
-1V       -65.86mA   -96.73mA   -40.3mA
-900mV    -27.52mA   -62.67mA   -17.99mA
-800mV    -9.29mA    -29.27mA   -10.66mA
-700mV    -4.426mA   -7.958mA   -5.286mA
-600mV    -1.758mA   -2.278mA   -1.872mA
-500mV    -435uA     -639uA     -372.1uA
-300mV    -1.407uA   -7.674uA   -410.7nA
2.5V      1.001uA    1.433uA    853.7nA
[POWER_clamp]
|Voltage   I(typ)   I(min)   I(max)
-2.5V     120.1mA    80.97mA    182.9mA
-1.5V     32mA       20.97mA    50.83mA
-1.3V     22.82mA    14.44mA    34.81mA
-1.2V     18.73mA    11.78mA    27.63mA
-1.1V     14.89mA    9.426mA    21.12mA
-900mV    8.105mA    5.574mA    10.43mA
-800mV    5.232mA    4.017mA    6.372mA
-700mV    2.88mA     2.638mA    3.356mA
-600mV    1.26mA     1.416mA    1.299mA
-500mV    363.1uA    518.9uA    287.4uA
-400mV    133.1uA    88.93uA    61.18uA
0V        0A         0A         0A
